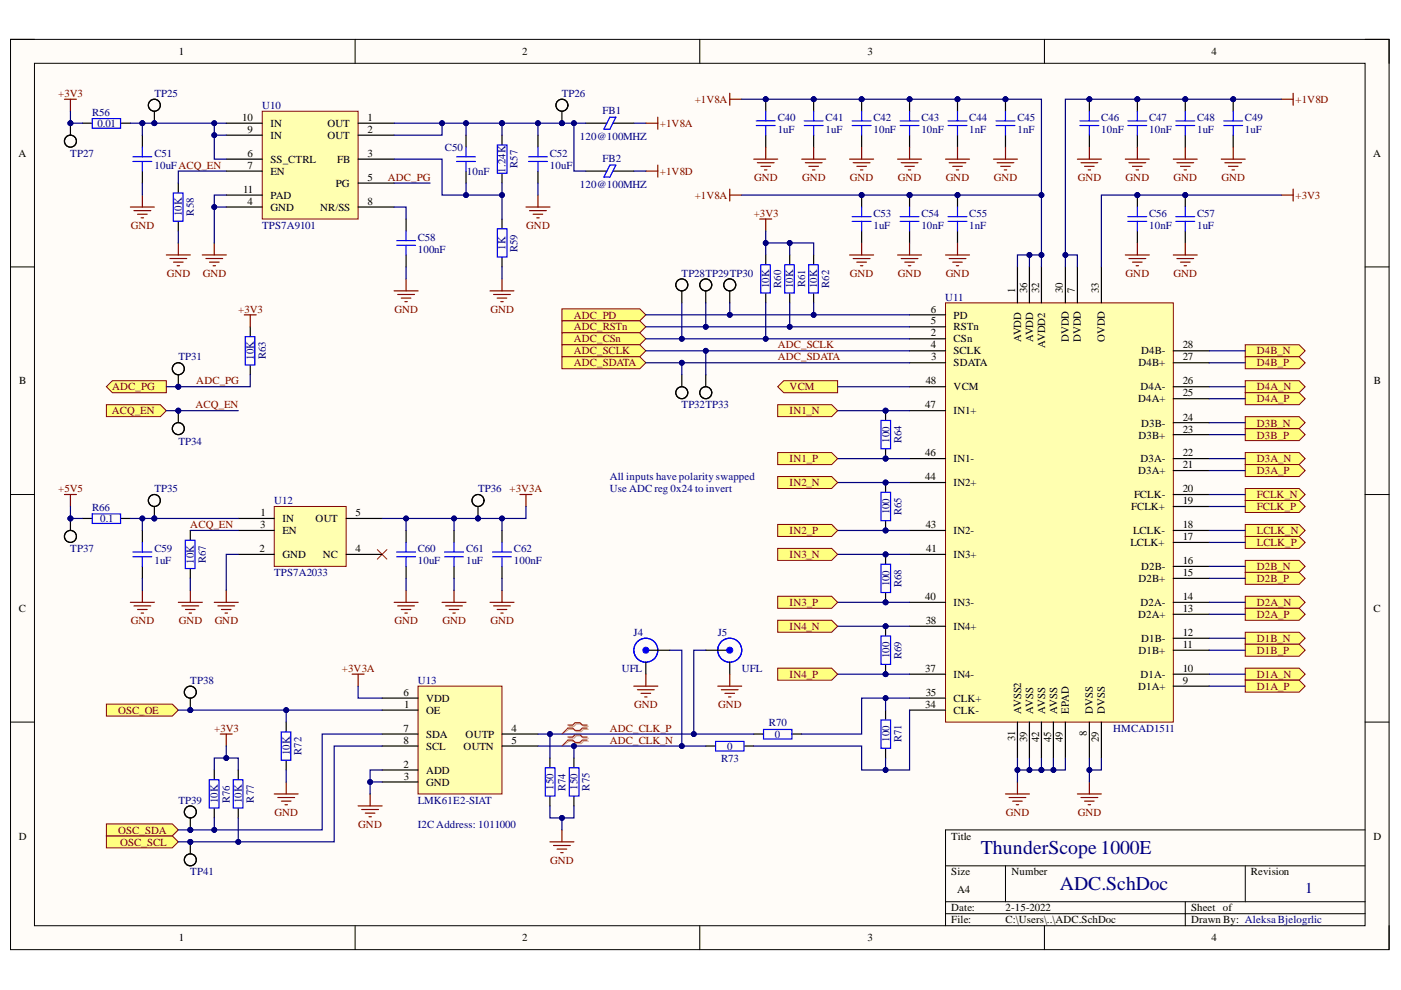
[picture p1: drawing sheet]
<svg xmlns="http://www.w3.org/2000/svg" width="297mm" height="210mm" viewBox="0 0 297 210" stroke-linecap="round" stroke-linejoin="round" font-family="sans-serif">
<defs><g id="words">
<g font-size="4.1" fill="#000080">
<text x="207.9" y="181.1">ThunderScope1000E</text>
<text x="224.7" y="188.8">ADC.SchDoc</text>
</g>
<text font-size="3.2" fill="#000080" x="276.7" y="189.3">1</text>
<g font-size="2.3">
<text x="37.9" y="11.7">1</text>
<text x="110.7" y="11.7">2</text>
<text x="183.9" y="11.7">3</text>
<text x="256.8" y="11.7">4</text>
<text x="51.4" y="25.6">10</text>
<text x="52.5" y="28.1">9</text>
<text x="57.4" y="29.5">IN</text>
<text x="57.4" y="26.9">IN</text>
<text x="69.5" y="26.9">OUT</text>
<text x="69.5" y="29.5">OUT</text>
<text x="77.9" y="25.6">1</text>
<text x="77.9" y="28.1">2</text>
<text x="3.9" y="33.3">A</text>
<text x="52.5" y="33.3">6</text>
<text x="52.5" y="35.8">7</text>
<text x="57.4" y="34.6">SS_CTRL</text>
<text x="71.5" y="34.6">FB</text>
<text x="77.9" y="33.3">3</text>
<text x="291.1" y="33.3">A</text>
<text x="51.5" y="40.9">11</text>
<text x="57.4" y="37.1">EN</text>
<text x="71.2" y="39.6">PG</text>
<text x="77.9" y="38.4">5</text>
<text x="52.5" y="43.4">4</text>
<text x="57.4" y="44.7">GND</text>
<text x="57.4" y="42.2">PAD</text>
<text x="67.8" y="44.7">NR/SS</text>
<text x="77.9" y="43.4">8</text>
<text x="215.2" y="62.2" transform="rotate(-90 215.2 62.2)">1</text>
<text x="217.8" y="62.2" transform="rotate(-90 217.8 62.2)">36</text>
<text x="220.3" y="62.2" transform="rotate(-90 220.3 62.2)">32</text>
<text x="225.4" y="62.2" transform="rotate(-90 225.4 62.2)">30</text>
<text x="227.9" y="62.2" transform="rotate(-90 227.9 62.2)">7</text>
<text x="233" y="62.2" transform="rotate(-90 233 62.2)">33</text>
<text x="197.4" y="66.3">6</text>
<text x="197.4" y="68.8">5</text>
<text x="197.4" y="71.3">2</text>
<text x="202.2" y="67.5">PD</text>
<text x="202.2" y="70.1">RSTn</text>
<text x="197.4" y="73.9">4</text>
<text x="197.5" y="76.4">3</text>
<text x="202.2" y="72.6">CSn</text>
<text x="202.2" y="75.1">SCLK</text>
<text x="202.2" y="77.7">SDATA</text>
<text x="216.5" y="72.5" transform="rotate(-90 216.5 72.5)">AVDD</text>
<text x="219" y="72.5" transform="rotate(-90 219 72.5)">AVDD</text>
<text x="221.6" y="73.7" transform="rotate(-90 221.6 73.7)">AVDD2</text>
<text x="226.6" y="72.5" transform="rotate(-90 226.6 72.5)">DVDD</text>
<text x="229.2" y="72.5" transform="rotate(-90 229.2 72.5)">DVDD</text>
<text x="234.3" y="72.5" transform="rotate(-90 234.3 72.5)">OVDD</text>
<text x="241.4" y="77.7">D4B+</text>
<text x="242" y="75.1">D4B-</text>
<text x="250.8" y="76.4">27</text>
<text x="250.8" y="73.9">28</text>
<text x="4.1" y="81.5">B</text>
<text x="196.3" y="81.5">48</text>
<text x="202.2" y="82.7">VCM</text>
<text x="241.8" y="82.7">D4A-</text>
<text x="250.8" y="81.5">26</text>
<text x="291.3" y="81.5">B</text>
<text x="196.2" y="86.6">47</text>
<text x="202.2" y="87.8">IN1+</text>
<text x="241.3" y="85.3">D4A+</text>
<text x="250.8" y="89.2">24</text>
<text x="250.8" y="84">25</text>
<text x="241.4" y="93">D3B+</text>
<text x="242" y="90.4">D3B-</text>
<text x="250.8" y="91.7">23</text>
<text x="196.2" y="96.8">46</text>
<text x="196.2" y="101.9">44</text>
<text x="202.2" y="98">IN1-</text>
<text x="241.3" y="100.6">D3A+</text>
<text x="241.8" y="98">D3A-</text>
<text x="250.8" y="99.3">21</text>
<text x="250.8" y="96.8">22</text>
<text x="202.2" y="103.1">IN2+</text>
<text x="240.4" y="105.7">FCLK-</text>
<text x="250.8" y="106.9">19</text>
<text x="250.8" y="104.4">20</text>
<text x="55.2" y="112">3</text>
<text x="55.2" y="109.5">1</text>
<text x="59.9" y="110.7">IN</text>
<text x="59.9" y="113.3">EN</text>
<text x="66.9" y="110.7">OUT</text>
<text x="75.4" y="109.5">5</text>
<text x="196.3" y="112">43</text>
<text x="202.2" y="113.3">IN2-</text>
<text x="239.8" y="108.2">FCLK+</text>
<text x="240.3" y="113.3">LCLK-</text>
<text x="250.8" y="112">18</text>
<text x="55" y="117.1">2</text>
<text x="59.9" y="118.3">GND</text>
<text x="68.4" y="118.3">NC</text>
<text x="75.4" y="117.1">4</text>
<text x="196.4" y="117.1">41</text>
<text x="202.2" y="118.3">IN3+</text>
<text x="239.7" y="115.8">LCLK+</text>
<text x="250.8" y="119.6">16</text>
<text x="250.8" y="114.5">17</text>
<text x="241.4" y="123.4">D2B+</text>
<text x="242" y="120.9">D2B-</text>
<text x="250.8" y="122.1">15</text>
<text x="4" y="129.7">C</text>
<text x="196.2" y="127.2">40</text>
<text x="202.2" y="128.5">IN3-</text>
<text x="241.3" y="131">D2A+</text>
<text x="241.8" y="128.5">D2A-</text>
<text x="250.8" y="129.7">13</text>
<text x="250.8" y="127.2">14</text>
<text x="291.2" y="129.7">C</text>
<text x="196.3" y="132.3">38</text>
<text x="202.2" y="133.6">IN4+</text>
<text x="242" y="136.1">D1B-</text>
<text x="250.8" y="137.4">11</text>
<text x="250.8" y="134.8">12</text>
<text x="196.2" y="142.4">37</text>
<text x="202.2" y="143.7">IN4-</text>
<text x="241.4" y="138.6">D1B+</text>
<text x="241.8" y="143.7">D1A-</text>
<text x="250.8" y="142.4">10</text>
<text x="85.5" y="147.5">6</text>
<text x="90.4" y="148.9">VDD</text>
<text x="196.3" y="147.5">35</text>
<text x="202.2" y="148.9">CLK+</text>
<text x="241.3" y="146.2">D1A+</text>
<text x="250.8" y="145">9</text>
<text x="85.5" y="155.2">7</text>
<text x="85.7" y="150.1">1</text>
<text x="90.4" y="151.4">OE</text>
<text x="108.5" y="155.2">4</text>
<text x="196.2" y="150.1">34</text>
<text x="202.2" y="151.4">CLK-</text>
<text x="216.5" y="151.3" transform="rotate(-90 216.5 151.3)">AVSS2</text>
<text x="219" y="151.3" transform="rotate(-90 219 151.3)">AVSS</text>
<text x="221.6" y="151.3" transform="rotate(-90 221.6 151.3)">AVSS</text>
<text x="224.1" y="151.3" transform="rotate(-90 224.1 151.3)">AVSS</text>
<text x="226.6" y="151.3" transform="rotate(-90 226.6 151.3)">EPAD</text>
<text x="231.7" y="151.3" transform="rotate(-90 231.7 151.3)">DVSS</text>
<text x="234.3" y="151.3" transform="rotate(-90 234.3 151.3)">DVSS</text>
<text x="85.5" y="157.7">8</text>
<text x="90.4" y="156.5">SDA</text>
<text x="90.4" y="159">SCL</text>
<text x="98.3" y="159">OUTN</text>
<text x="98.7" y="156.5">OUTP</text>
<text x="108.5" y="157.7">5</text>
<text x="215.2" y="157.1" transform="rotate(-90 215.2 157.1)">31</text>
<text x="217.8" y="157.3" transform="rotate(-90 217.8 157.3)">39</text>
<text x="220.3" y="157.3" transform="rotate(-90 220.3 157.3)">42</text>
<text x="222.8" y="157.3" transform="rotate(-90 222.8 157.3)">45</text>
<text x="225.4" y="157.3" transform="rotate(-90 225.4 157.3)">49</text>
<text x="230.4" y="156.1" transform="rotate(-90 230.4 156.1)">8</text>
<text x="233" y="157.3" transform="rotate(-90 233 157.3)">29</text>
<text x="85.5" y="162.8">2</text>
<text x="85.6" y="165.3">3</text>
<text x="90.4" y="164.1">ADD</text>
<text x="90.4" y="166.6">GND</text>
<text x="4" y="178">D</text>
<text x="201.7" y="178">Title</text>
<text x="291.2" y="178">D</text>
<text x="201.7" y="185.6">Size</text>
<text x="214.5" y="185.6">Number</text>
<text x="265.2" y="185.6">Revision</text>
<text x="203" y="189.4">A4</text>
<text x="201.7" y="193.2">Date:</text>
<text x="201.7" y="195.8">File:</text>
<text x="213.2" y="193.2">2-15-2022</text>
<text x="213.2" y="195.8">C:\Users\..\ADC.SchDoc</text>
<text x="252.5" y="193.2">Sheet of</text>
<text x="252.5" y="195.8">Drawn By: Aleksa Bjelogrlic</text>
<text x="37.9" y="199.6">1</text>
<text x="110.7" y="199.6">2</text>
<text x="183.9" y="199.6">3</text>
<text x="256.8" y="199.6">4</text>
</g>
<g font-size="2.3" fill="#800000">
<text x="12.4" y="20.5">+3V3</text>
<text x="147.3" y="21.8">+1V8A</text>
<text x="274.7" y="21.8">+1V8D</text>
<text x="139.9" y="26.9">+1V8A</text>
<text x="82.2" y="38.4">ADC_PG</text>
<text x="139.9" y="37.1">+1V8D</text>
<text x="159.9" y="38.4">GND</text>
<text x="170" y="38.4">GND</text>
<text x="180.2" y="38.4">GND</text>
<text x="190.3" y="38.4">GND</text>
<text x="200.5" y="38.4">GND</text>
<text x="210.7" y="38.4">GND</text>
<text x="228.5" y="38.4">GND</text>
<text x="238.7" y="38.4">GND</text>
<text x="248.8" y="38.4">GND</text>
<text x="259" y="38.4">GND</text>
<text x="147.3" y="42.2">+1V8A</text>
<text x="159.8" y="46">+3V3</text>
<text x="274.7" y="42.2">+3V3</text>
<text x="27.7" y="48.5">GND</text>
<text x="111.6" y="48.5">GND</text>
<text x="35.4" y="58.7">GND</text>
<text x="43" y="58.7">GND</text>
<text x="180.2" y="58.7">GND</text>
<text x="190.3" y="58.7">GND</text>
<text x="200.5" y="58.7">GND</text>
<text x="238.7" y="58.7">GND</text>
<text x="248.8" y="58.7">GND</text>
<text x="50.5" y="66.3">+3V3</text>
<text x="83.7" y="66.3">GND</text>
<text x="104" y="66.3">GND</text>
<text x="121.7" y="67.5">ADC_PD</text>
<text x="121.7" y="70.1">ADC_RSTn</text>
<text x="121.7" y="72.6">ADC_CSn</text>
<text x="121.7" y="75.1">ADC_SCLK</text>
<text x="121.7" y="77.7">ADC_SDATA</text>
<text x="164.9" y="73.9">ADC_SCLK</text>
<text x="164.9" y="76.4">ADC_SDATA</text>
<text x="266.5" y="75.1">D4B_N</text>
<text x="266.5" y="77.7">D4B_P</text>
<text x="23.8" y="82.7">ADC_PG</text>
<text x="41.6" y="81.5">ADC_PG</text>
<text x="167.4" y="82.7">VCM</text>
<text x="266.5" y="82.7">D4A_N</text>
<text x="23.7" y="87.8">ACQ_EN</text>
<text x="41.5" y="86.6">ACQ_EN</text>
<text x="167.4" y="87.8">IN1_N</text>
<text x="266.5" y="85.3">D4A_P</text>
<text x="266.5" y="90.4">D3B_N</text>
<text x="266.5" y="93">D3B_P</text>
<text x="167.4" y="98">IN1_P</text>
<text x="266.5" y="98">D3A_N</text>
<text x="266.5" y="100.6">D3A_P</text>
<text x="12.4" y="104.4">+5V5</text>
<text x="108" y="104.4">+3V3A</text>
<text x="167.4" y="103.1">IN2_N</text>
<text x="266.5" y="105.7">FCLK_N</text>
<text x="40.4" y="112">ACQ_EN</text>
<text x="167.4" y="113.3">IN2_P</text>
<text x="266.5" y="108.2">FCLK_P</text>
<text x="266.5" y="113.3">LCLK_N</text>
<text x="167.4" y="118.3">IN3_N</text>
<text x="266.5" y="115.8">LCLK_P</text>
<text x="266.5" y="120.9">D2B_N</text>
<text x="266.5" y="123.4">D2B_P</text>
<text x="167.4" y="128.5">IN3_P</text>
<text x="266.5" y="128.5">D2A_N</text>
<text x="266.5" y="131">D2A_P</text>
<text x="27.7" y="132.3">GND</text>
<text x="37.9" y="132.3">GND</text>
<text x="45.5" y="132.3">GND</text>
<text x="83.7" y="132.3">GND</text>
<text x="93.8" y="132.3">GND</text>
<text x="104" y="132.3">GND</text>
<text x="167.4" y="133.6">IN4_N</text>
<text x="266.5" y="136.1">D1B_N</text>
<text x="72.5" y="142.4">+3V3A</text>
<text x="167.4" y="143.7">IN4_P</text>
<text x="266.5" y="138.6">D1B_P</text>
<text x="266.5" y="143.7">D1A_N</text>
<text x="266.5" y="146.2">D1A_P</text>
<text x="25" y="151.4">OSC_OE</text>
<text x="45.4" y="155.2">+3V3</text>
<text x="129.3" y="155.2">ADC_CLK_P</text>
<text x="134.4" y="150.1">GND</text>
<text x="152.3" y="150.1">GND</text>
<text x="129.3" y="157.7">ADC_CLK_N</text>
<text x="58.2" y="172.9">GND</text>
<text x="213.3" y="172.9">GND</text>
<text x="228.5" y="172.9">GND</text>
<text x="25" y="176.7">OSC_SDA</text>
<text x="25.5" y="179.3">OSC_SCL</text>
<text x="76" y="175.5">GND</text>
<text x="116.7" y="183.1">GND</text>
</g>
<g font-size="2.3" fill="#000080">
<text x="32.7" y="20.5">TP25</text>
<text x="55.6" y="23.1">U10</text>
<text x="119.1" y="20.5">TP26</text>
<text x="19.5" y="24.7">R56</text>
<text x="20.6" y="26.9">0.01</text>
<text x="122.9" y="29.7">120@100MHZ</text>
<text x="127.7" y="24.1">FB1</text>
<text x="164.9" y="25.6">C40</text>
<text x="164.9" y="28.1">1uF</text>
<text x="175" y="25.6">C41</text>
<text x="175" y="28.1">1uF</text>
<text x="185.2" y="25.6">C42</text>
<text x="185.2" y="28.1">10nF</text>
<text x="195.3" y="25.6">C43</text>
<text x="195.3" y="28.1">10nF</text>
<text x="205.5" y="25.6">C44</text>
<text x="205.5" y="28.1">1nF</text>
<text x="215.7" y="25.6">C45</text>
<text x="215.7" y="28.1">1nF</text>
<text x="233.5" y="25.6">C46</text>
<text x="233.5" y="28.1">10nF</text>
<text x="243.6" y="25.6">C47</text>
<text x="243.6" y="28.1">10nF</text>
<text x="253.8" y="25.6">C48</text>
<text x="253.8" y="28.1">1uF</text>
<text x="264" y="25.6">C49</text>
<text x="264" y="28.1">1uF</text>
<text x="14.9" y="33.3">TP27</text>
<text x="32.7" y="33.3">C51</text>
<text x="32.7" y="35.8">10uFACQ_EN</text>
<text x="94.3" y="32">C50</text>
<text x="109.7" y="35.6" transform="rotate(-90 109.7 35.6)">R57</text>
<text x="116.6" y="33.3">C52</text>
<text x="116.6" y="35.8">10uF</text>
<text x="127.7" y="34.3">FB2</text>
<text x="99" y="37.1">10nF</text>
<text x="107.2" y="36.6" transform="rotate(-90 107.2 36.6)">1.24K</text>
<text x="122.9" y="39.9">120@100MHZ</text>
<text x="38.6" y="45.9" transform="rotate(-90 38.6 45.9)">10K</text>
<text x="41.1" y="45.7" transform="rotate(-90 41.1 45.7)">R58</text>
<text x="185.2" y="46">C53</text>
<text x="195.3" y="46">C54</text>
<text x="205.5" y="46">C55</text>
<text x="243.6" y="46">C56</text>
<text x="253.8" y="46">C57</text>
<text x="55.6" y="48.5">TPS7A9101</text>
<text x="88.6" y="51">C58</text>
<text x="88.6" y="53.6">100nF</text>
<text x="107.2" y="52.9" transform="rotate(-90 107.2 52.9)">1K</text>
<text x="109.7" y="53.4" transform="rotate(-90 109.7 53.4)">R59</text>
<text x="185.2" y="48.5">1uF</text>
<text x="195.3" y="48.5">10nF</text>
<text x="205.5" y="48.5">1nF</text>
<text x="243.6" y="48.5">10nF</text>
<text x="253.8" y="48.5">1uF</text>
<text x="144.5" y="58.7">TP28TP29TP30</text>
<text x="163.1" y="61.1" transform="rotate(-90 163.1 61.1)">10K</text>
<text x="165.6" y="61" transform="rotate(-90 165.6 61)">R60</text>
<text x="168.2" y="61.1" transform="rotate(-90 168.2 61.1)">10K</text>
<text x="170.7" y="60.9" transform="rotate(-90 170.7 60.9)">R61</text>
<text x="173.3" y="61.1" transform="rotate(-90 173.3 61.1)">10K</text>
<text x="175.8" y="61" transform="rotate(-90 175.8 61)">R62</text>
<text x="200.4" y="63.7">U11</text>
<text x="37.8" y="76.4">TP31</text>
<text x="53.8" y="76.3" transform="rotate(-90 53.8 76.3)">10K</text>
<text x="56.3" y="76.2" transform="rotate(-90 56.3 76.2)">R63</text>
<text x="144.5" y="86.6">TP32TP33</text>
<text x="37.8" y="94.2">TP34</text>
<text x="188.6" y="93.8" transform="rotate(-90 188.6 93.8)">100</text>
<text x="191.1" y="94" transform="rotate(-90 191.1 94)">R64</text>
<text x="129.3" y="101.9">All inputs have polarity swapped</text>
<text x="32.7" y="104.4">TP35</text>
<text x="58.1" y="106.9">U12</text>
<text x="101.4" y="104.4">TP36</text>
<text x="129.3" y="104.4">Use ADC reg 0x24 to invert</text>
<text x="19.5" y="108.4">R66</text>
<text x="21.2" y="110.7">0.1</text>
<text x="188.6" y="109" transform="rotate(-90 188.6 109)">100</text>
<text x="191.1" y="109.2" transform="rotate(-90 191.1 109.2)">R65</text>
<text x="14.9" y="117.1">TP37</text>
<text x="32.7" y="117.1">C59</text>
<text x="32.7" y="119.6">1uF</text>
<text x="41.1" y="119.5" transform="rotate(-90 41.1 119.5)">10K</text>
<text x="43.7" y="119.4" transform="rotate(-90 43.7 119.4)">R67</text>
<text x="88.6" y="117.1">C60</text>
<text x="88.6" y="119.6">10uF</text>
<text x="98.8" y="117.1">C61</text>
<text x="98.8" y="119.6">1uF</text>
<text x="109" y="117.1">C62</text>
<text x="109" y="119.6">100nF</text>
<text x="58.1" y="122.1">TPS7A2033</text>
<text x="188.6" y="124.3" transform="rotate(-90 188.6 124.3)">100</text>
<text x="191.1" y="124.5" transform="rotate(-90 191.1 124.5)">R68</text>
<text x="134.3" y="134.8">J4</text>
<text x="152.2" y="134.8">J5</text>
<text x="131.8" y="142.4">UFL</text>
<text x="157.3" y="142.4">UFL</text>
<text x="188.6" y="139.6" transform="rotate(-90 188.6 139.6)">100</text>
<text x="191.1" y="139.7" transform="rotate(-90 191.1 139.7)">R69</text>
<text x="40.4" y="145">TP38</text>
<text x="88.6" y="145">U13</text>
<text x="163" y="153.9">R70</text>
<text x="236" y="155.2">HMCAD1511</text>
<text x="61.4" y="160.2" transform="rotate(-90 61.4 160.2)">10K</text>
<text x="64" y="160" transform="rotate(-90 64 160)">R72</text>
<text x="152.9" y="161.5">R73</text>
<text x="154.1" y="159">0</text>
<text x="164.3" y="156.5">0</text>
<text x="188.6" y="157.3" transform="rotate(-90 188.6 157.3)">100</text>
<text x="191.1" y="157.4" transform="rotate(-90 191.1 157.4)">R71</text>
<text x="117.3" y="167.4" transform="rotate(-90 117.3 167.4)">150</text>
<text x="119.9" y="167.7" transform="rotate(-90 119.9 167.7)">R74</text>
<text x="122.4" y="167.4" transform="rotate(-90 122.4 167.4)">150</text>
<text x="125" y="167.6" transform="rotate(-90 125 167.6)">R75</text>
<text x="37.8" y="170.4">TP39</text>
<text x="46.2" y="170.3" transform="rotate(-90 46.2 170.3)">10K</text>
<text x="48.7" y="170.2" transform="rotate(-90 48.7 170.2)">R76</text>
<text x="51.3" y="170.3" transform="rotate(-90 51.3 170.3)">10K</text>
<text x="53.8" y="170.2" transform="rotate(-90 53.8 170.2)">R77</text>
<text x="88.6" y="170.4">LMK61E2-SIAT</text>
<text x="88.6" y="175.5">I2C Address: 1011000</text>
<text x="40.4" y="185.6">TP41</text>
</g>
</g></defs>
<path d="M2.2 8.3h292.3v193h-292.3z" fill-rule="evenodd" fill="#fffcf8"/>
<path d="M2.2 8.3h292.3v193h-292.3z" fill="none" stroke="#000" stroke-width=".21"/>
<path d="M7.3 13.4h282.1v182.9h-282.1z" fill-rule="evenodd" fill="#fffcf8"/>
<g fill="none" stroke="#000" stroke-width=".21">
<path d="M2.2 8.3h5.1M7.3 13.4h282.1v182.9h-282.1zM75.3 8.3v5.1M148.4 8.3v5.1M221.4 8.3v5.1M289.4 8.3h5.1v5.1M2.2 56.6h5.1M289.4 56.6h5.1M2.2 104.8h5.1M289.4 104.9h5.1M2.2 153.1h5.1M289.4 153.1h5.1"/>
<path d="M289.4 176h-88.9v20.3M75.3 196.3v5M148.4 196.3v5M200.5 183.6h88.9M200.5 191.2h88.9M200.5 193.7h88.9M213.2 183.6v7.6M221.4 196.3v5M251.3 191.2v5.1M264 183.6v7.6M294.5 196.3v5"/>
</g>
<path d="M55.6 23.6h20.3v22.8h-20.3z" fill-rule="evenodd" fill="#ffffb0"/>
<path d="M55.6 23.6h20.3v22.8h-20.3z" fill="none" stroke="#800000" stroke-width=".21"/>
<g fill="none" stroke="#000" stroke-width=".25">
<path d="M30.2 28.7v2.5M30.2 36.3v2.5M48 26.1h7.6M48 28.7h7.6M48 33.7h7.6M48 36.3h7.6M75.9 26.1h7.7M75.9 28.7h7.7M75.9 33.7h7.7M75.9 38.8h7.7M98.8 28.7v2.5M98.8 36.3v2.5"/>
<path d="M106.4 28.7v2M106.4 36.8v2M114.1 28.7v2.5M114.1 36.3v2.5M48 43.9h7.6M48 41.4h7.6M75.9 43.9h7.7M86.1 46.4v2.6M86.1 54.1v2.5M106.4 46.4v2M106.4 54.6v2"/>
</g>
<g fill="none" stroke="#800000" stroke-width=".25">
<path d="M13.7 21h2.5M14.9 21v2.6M27.6 43.9h5.1M28.4 44.7h3.6M29.2 45.4h2M29.9 46.2h.5M30.2 41.4v2.5M42.9 54.1h5.1M43.7 54.8h3.5M44.4 55.6h2.1M45.2 56.3h.5M45.4 51.5v2.6"/>
<path d="M86.1 59.1v2.6M106.4 59.1v2.6M111.5 43.9h5.1M112.3 44.7h3.5M113 45.4h2.1M113.8 46.2h.5M114.1 41.4v2.5M83.6 61.7h5M84.3 62.4h3.6M85.1 63.2h2M85.8 64h.5M103.9 61.7h5.1"/>
<path d="M104.6 62.4h3.6M105.4 63.2h2M106.2 64h.5"/>
</g>
<g fill="none" stroke="#00f" stroke-width=".25">
<path d="M28.2 34.2h4M28.2 33.2h4M30.2 31.2v2M30.2 34.2v2.1M96.8 34.2h4M96.8 33.2h4M98.8 31.2v2M98.8 34.2v2.1M105.5 30.7h2v6h-2zM112.1 34.2h4M112.1 33.2h4M114.1 31.2v2"/>
<path d="M114.1 34.2v2.1M84.1 52h4M84.1 51h4M86.1 49v2M86.1 52v2.1M105.5 48.5h2v6h-2z"/>
</g>
<circle cx="241.1" cy="41.4" r=".51" fill="#000080"/>
<circle cx="241.1" cy="41.4" r=".51" fill="none" stroke="#000080" stroke-width=".21"/>
<path d="M241.1 41.4v2.5M241.1 49v2.5" fill="none" stroke="#000" stroke-width=".25"/>
<circle cx="241.1" cy="41.4" r=".51" fill="#000080"/>
<circle cx="241.1" cy="41.4" r=".51" fill="none" stroke="#000080" stroke-width=".21"/>
<path d="M239.1 46.9h4M239.1 45.9h4M241.1 43.9v2M241.1 46.9v2.1" fill="none" stroke="#00f" stroke-width=".25"/>
<circle cx="251.3" cy="41.4" r=".51" fill="#000080"/>
<circle cx="251.3" cy="41.4" r=".51" fill="none" stroke="#000080" stroke-width=".21"/>
<path d="M251.3 41.4v2.5M251.3 49v2.5" fill="none" stroke="#000" stroke-width=".25"/>
<circle cx="251.3" cy="41.4" r=".51" fill="#000080"/>
<circle cx="251.3" cy="41.4" r=".51" fill="none" stroke="#000080" stroke-width=".21"/>
<path d="M249.3 46.9h4M249.3 45.9h4M251.3 43.9v2M251.3 46.9v2.1" fill="none" stroke="#00f" stroke-width=".25"/>
<path d="M238.6 54.1h5.1M239.4 54.8h3.5M240.1 55.6h2.1M240.9 56.3h.5M241.1 51.5v2.6M248.8 54.1h5M249.5 54.8h3.6M250.3 55.6h2M251 56.3h.6M251.3 51.5v2.6M271.6 41.4h2.6M274.2 40.1v2.5" fill="none" stroke="#800000" stroke-width=".25"/>
<circle cx="231" cy="21" r=".51" fill="#000080"/>
<circle cx="231" cy="21" r=".51" fill="none" stroke="#000080" stroke-width=".21"/>
<path d="M231 21v2.6M231 28.7v2.5" fill="none" stroke="#000" stroke-width=".25"/>
<circle cx="231" cy="21" r=".51" fill="#000080"/>
<circle cx="231" cy="21" r=".51" fill="none" stroke="#000080" stroke-width=".21"/>
<path d="M229 26.6h4M229 25.6h4M231 23.6v2M231 26.6v2.1" fill="none" stroke="#00f" stroke-width=".25"/>
<circle cx="261.5" cy="21" r=".51" fill="#000080"/>
<circle cx="261.5" cy="21" r=".51" fill="none" stroke="#000080" stroke-width=".21"/>
<path d="M261.5 21v2.6M261.5 28.7v2.5" fill="none" stroke="#000" stroke-width=".25"/>
<circle cx="261.5" cy="21" r=".51" fill="#000080"/>
<circle cx="261.5" cy="21" r=".51" fill="none" stroke="#000080" stroke-width=".21"/>
<path d="M259.5 26.6h4M259.5 25.6h4M261.5 23.6v2M261.5 26.6v2.1" fill="none" stroke="#00f" stroke-width=".25"/>
<path d="M228.4 33.7h5.1M229.2 34.5h3.5M230 35.3h2M230.7 36h.5M231 31.2v2.5M258.9 33.7h5.1M259.7 34.5h3.5M260.5 35.3h2M261.2 36h.5M261.5 31.2v2.5" fill="none" stroke="#800000" stroke-width=".25"/>
<circle cx="241.1" cy="21" r=".51" fill="#000080"/>
<circle cx="241.1" cy="21" r=".51" fill="none" stroke="#000080" stroke-width=".21"/>
<path d="M241.1 21v2.6M241.1 28.7v2.5" fill="none" stroke="#000" stroke-width=".25"/>
<circle cx="241.1" cy="21" r=".51" fill="#000080"/>
<circle cx="241.1" cy="21" r=".51" fill="none" stroke="#000080" stroke-width=".21"/>
<path d="M239.1 26.6h4M239.1 25.6h4M241.1 23.6v2M241.1 26.6v2.1" fill="none" stroke="#00f" stroke-width=".25"/>
<circle cx="251.3" cy="21" r=".51" fill="#000080"/>
<circle cx="251.3" cy="21" r=".51" fill="none" stroke="#000080" stroke-width=".21"/>
<path d="M251.3 21v2.6M251.3 28.7v2.5" fill="none" stroke="#000" stroke-width=".25"/>
<circle cx="251.3" cy="21" r=".51" fill="#000080"/>
<circle cx="251.3" cy="21" r=".51" fill="none" stroke="#000080" stroke-width=".21"/>
<path d="M249.3 26.6h4M249.3 25.6h4M251.3 23.6v2M251.3 26.6v2.1" fill="none" stroke="#00f" stroke-width=".25"/>
<path d="M274.2 19.8v2.5M238.6 33.7h5.1M239.4 34.5h3.5M240.1 35.3h2.1M240.9 36h.5M241.1 31.2v2.5M248.8 33.7h5M249.5 34.5h3.6M250.3 35.3h2M251 36h.6M251.3 31.2v2.5M271.6 21h2.6" fill="none" stroke="#800000" stroke-width=".25"/>
<circle cx="192.8" cy="21" r=".51" fill="#000080"/>
<circle cx="192.8" cy="21" r=".51" fill="none" stroke="#000080" stroke-width=".21"/>
<path d="M192.8 21v2.6M192.8 28.7v2.5" fill="none" stroke="#000" stroke-width=".25"/>
<circle cx="192.8" cy="21" r=".51" fill="#000080"/>
<circle cx="192.8" cy="21" r=".51" fill="none" stroke="#000080" stroke-width=".21"/>
<path d="M190.8 26.6h4M190.8 25.6h4M192.8 23.6v2M192.8 26.6v2.1" fill="none" stroke="#00f" stroke-width=".25"/>
<circle cx="162.3" cy="21" r=".51" fill="#000080"/>
<circle cx="162.3" cy="21" r=".51" fill="none" stroke="#000080" stroke-width=".21"/>
<path d="M162.3 21v2.6M162.3 28.7v2.5" fill="none" stroke="#000" stroke-width=".25"/>
<circle cx="162.3" cy="21" r=".51" fill="#000080"/>
<circle cx="162.3" cy="21" r=".51" fill="none" stroke="#000080" stroke-width=".21"/>
<path d="M160.3 26.6h4M160.3 25.6h4M162.3 23.6v2M162.3 26.6v2.1" fill="none" stroke="#00f" stroke-width=".25"/>
<path d="M159.8 33.7h5.1M160.6 34.5h3.5M161.3 35.3h2.1M162.1 36h.5M162.3 31.2v2.5M190.3 33.7h5.1M191.1 34.5h3.5M191.8 35.3h2.1M192.6 36h.5M192.8 31.2v2.5" fill="none" stroke="#800000" stroke-width=".25"/>
<circle cx="182.7" cy="21" r=".51" fill="#000080"/>
<circle cx="182.7" cy="21" r=".51" fill="none" stroke="#000080" stroke-width=".21"/>
<path d="M182.7 21v2.6M182.7 28.7v2.5" fill="none" stroke="#000" stroke-width=".25"/>
<circle cx="182.7" cy="21" r=".51" fill="#000080"/>
<circle cx="182.7" cy="21" r=".51" fill="none" stroke="#000080" stroke-width=".21"/>
<path d="M180.7 26.6h4M180.7 25.6h4M182.7 23.6v2M182.7 26.6v2.1" fill="none" stroke="#00f" stroke-width=".25"/>
<circle cx="172.5" cy="21" r=".51" fill="#000080"/>
<circle cx="172.5" cy="21" r=".51" fill="none" stroke="#000080" stroke-width=".21"/>
<path d="M172.5 21v2.6M172.5 28.7v2.5" fill="none" stroke="#000" stroke-width=".25"/>
<circle cx="172.5" cy="21" r=".51" fill="#000080"/>
<circle cx="172.5" cy="21" r=".51" fill="none" stroke="#000080" stroke-width=".21"/>
<path d="M170.5 26.6h4M170.5 25.6h4M172.5 23.6v2M172.5 26.6v2.1" fill="none" stroke="#00f" stroke-width=".25"/>
<path d="M170 33.7h5.1M170.7 34.5h3.6M171.5 35.3h2M172.3 36h.5M172.5 31.2v2.5M180.1 33.7h5.1M180.9 34.5h3.6M181.7 35.3h2M182.4 36h.5M182.7 31.2v2.5" fill="none" stroke="#800000" stroke-width=".25"/>
<circle cx="203" cy="21" r=".51" fill="#000080"/>
<circle cx="203" cy="21" r=".51" fill="none" stroke="#000080" stroke-width=".21"/>
<path d="M203 21v2.6M203 28.7v2.5" fill="none" stroke="#000" stroke-width=".25"/>
<circle cx="203" cy="21" r=".51" fill="#000080"/>
<circle cx="203" cy="21" r=".51" fill="none" stroke="#000080" stroke-width=".21"/>
<path d="M201 26.6h4M201 25.6h4M203 23.6v2M203 26.6v2.1" fill="none" stroke="#00f" stroke-width=".25"/>
<path d="M200.5 33.7h5.1M201.2 34.5h3.6M202 35.3h2M202.8 36h.5M203 31.2v2.5" fill="none" stroke="#800000" stroke-width=".25"/>
<circle cx="213.2" cy="21" r=".51" fill="#000080"/>
<circle cx="213.2" cy="21" r=".51" fill="none" stroke="#000080" stroke-width=".21"/>
<path d="M213.2 21v2.6M213.2 28.7v2.5" fill="none" stroke="#000" stroke-width=".25"/>
<circle cx="213.2" cy="21" r=".51" fill="#000080"/>
<circle cx="213.2" cy="21" r=".51" fill="none" stroke="#000080" stroke-width=".21"/>
<path d="M211.2 26.6h4M211.2 25.6h4M213.2 23.6v2M213.2 26.6v2.1" fill="none" stroke="#00f" stroke-width=".25"/>
<path d="M210.6 33.7h5.1M211.4 34.5h3.6M212.2 35.3h2M212.9 36h.5M213.2 31.2v2.5" fill="none" stroke="#800000" stroke-width=".25"/>
<circle cx="182.7" cy="41.4" r=".51" fill="#000080"/>
<circle cx="182.7" cy="41.4" r=".51" fill="none" stroke="#000080" stroke-width=".21"/>
<path d="M182.7 41.4v2.5M182.7 49v2.5" fill="none" stroke="#000" stroke-width=".25"/>
<circle cx="182.7" cy="41.4" r=".51" fill="#000080"/>
<circle cx="182.7" cy="41.4" r=".51" fill="none" stroke="#000080" stroke-width=".21"/>
<path d="M180.7 46.9h4M180.7 45.9h4M182.7 43.9v2M182.7 46.9v2.1" fill="none" stroke="#00f" stroke-width=".25"/>
<path d="M180.1 54.1h5.1M180.9 54.8h3.6M181.7 55.6h2M182.4 56.3h.5M182.7 51.5v2.6" fill="none" stroke="#800000" stroke-width=".25"/>
<circle cx="192.8" cy="41.4" r=".51" fill="#000080"/>
<circle cx="192.8" cy="41.4" r=".51" fill="none" stroke="#000080" stroke-width=".21"/>
<path d="M192.8 41.4v2.5M192.8 49v2.5" fill="none" stroke="#000" stroke-width=".25"/>
<circle cx="192.8" cy="41.4" r=".51" fill="#000080"/>
<circle cx="192.8" cy="41.4" r=".51" fill="none" stroke="#000080" stroke-width=".21"/>
<path d="M190.8 46.9h4M190.8 45.9h4M192.8 43.9v2M192.8 46.9v2.1" fill="none" stroke="#00f" stroke-width=".25"/>
<path d="M190.3 54.1h5.1M191.1 54.8h3.5M191.8 55.6h2.1M192.6 56.3h.5M192.8 51.5v2.6" fill="none" stroke="#800000" stroke-width=".25"/>
<circle cx="203" cy="41.4" r=".51" fill="#000080"/>
<circle cx="203" cy="41.4" r=".51" fill="none" stroke="#000080" stroke-width=".21"/>
<path d="M203 41.4v2.5M203 49v2.5" fill="none" stroke="#000" stroke-width=".25"/>
<circle cx="203" cy="41.4" r=".51" fill="#000080"/>
<circle cx="203" cy="41.4" r=".51" fill="none" stroke="#000080" stroke-width=".21"/>
<path d="M161.3 56.1h2v6h-2zM166.4 56.1h2v6h-2zM171.5 56.1h2v6h-2zM201 46.9h4M201 45.9h4M203 43.9v2M203 46.9v2.1" fill="none" stroke="#00f" stroke-width=".25"/>
<path d="M200.5 54.1h5.1M201.2 54.8h3.6M202 55.6h2M202.8 56.3h.5M203 51.5v2.6" fill="none" stroke="#800000" stroke-width=".25"/>
<path d="M162.3 54.1v2M167.4 54.1v2M172.5 54.1v2M162.3 62.2v2M167.4 62.2v2M172.5 62.2v2" fill="none" stroke="#000" stroke-width=".25"/>
<path d="M200.5 64.2h48.3v88.9h-48.3z" fill-rule="evenodd" fill="#ffffb0"/>
<path d="M200.5 64.2h48.3v88.9h-48.3z" fill="none" stroke="#800000" stroke-width=".21"/>
<g fill="none" stroke="#000" stroke-width=".25">
<path d="M215.7 56.6v7.6M218.3 56.6v7.6M220.8 56.6v7.6M225.9 56.6v7.6M228.4 56.6v7.6M233.5 56.6v7.6M192.8 66.8h7.7M192.8 69.3h7.7M192.8 71.8h7.7M192.8 74.4h7.7M192.8 76.9h7.7M248.8 74.4h7.6"/>
<path d="M248.8 76.9h7.6M192.8 82h7.7M192.8 87.1h7.7M192.8 97.2h7.7M248.8 82h7.6M248.8 97.2h7.6M248.8 99.8h7.6M248.8 92.2h7.6M248.8 89.6h7.6M248.8 84.5h7.6M192.8 102.3h7.7M192.8 112.5h7.7"/>
<path d="M192.8 117.5h7.7M248.8 112.5h7.6M248.8 115h7.6M248.8 107.4h7.6M248.8 104.9h7.6M192.8 127.7h7.7M192.8 132.8h7.7M248.8 127.7h7.6M248.8 137.9h7.6M248.8 135.3h7.6M248.8 130.2h7.6M248.8 122.6h7.6"/>
<path d="M248.8 120.1h7.6M192.8 142.9h7.7M192.8 148h7.7M192.8 150.6h7.7M215.7 153.1v7.6M218.3 153.1v7.6M220.8 153.1v7.6M223.3 153.1v7.6M225.9 153.1v7.6M231 153.1v7.6M233.5 153.1v7.6M248.8 142.9h7.6"/>
<path d="M248.8 145.5h7.6"/>
</g>
<g fill="none" stroke="#800000" stroke-width=".25">
<path d="M154.7 19.8v2.5M154.7 21h2.6M154.7 40.1v2.5M154.7 41.4h2.6M161.1 46.4h2.5M162.3 46.4v2.6M213.2 168.3h5.1M213.9 169.1h3.6M214.7 169.9h2M215.5 170.6h.5M215.7 165.8v2.5M228.4 168.3h5.1"/>
<path d="M229.2 169.1h3.5M230 169.9h2M230.7 170.6h.5M231 165.8v2.5"/>
</g>
<circle cx="187.8" cy="87.1" r=".51" fill="#000080"/>
<circle cx="187.8" cy="87.1" r=".51" fill="none" stroke="#000080" stroke-width=".21"/>
<circle cx="187.8" cy="97.2" r=".51" fill="#000080"/>
<circle cx="187.8" cy="97.2" r=".51" fill="none" stroke="#000080" stroke-width=".21"/>
<path d="M187.8 87.1v2" fill="none" stroke="#000" stroke-width=".25"/>
<circle cx="187.8" cy="87.1" r=".51" fill="#000080"/>
<circle cx="187.8" cy="87.1" r=".51" fill="none" stroke="#000080" stroke-width=".21"/>
<path d="M187.8 95.2v2" fill="none" stroke="#000" stroke-width=".25"/>
<circle cx="187.8" cy="97.2" r=".51" fill="#000080"/>
<circle cx="187.8" cy="97.2" r=".51" fill="none" stroke="#000080" stroke-width=".21"/>
<path d="M186.8 89.2h2v6h-2z" fill="none" stroke="#00f" stroke-width=".25"/>
<circle cx="187.8" cy="102.3" r=".51" fill="#000080"/>
<circle cx="187.8" cy="102.3" r=".51" fill="none" stroke="#000080" stroke-width=".21"/>
<circle cx="187.8" cy="112.5" r=".51" fill="#000080"/>
<circle cx="187.8" cy="112.5" r=".51" fill="none" stroke="#000080" stroke-width=".21"/>
<path d="M187.8 102.3v2" fill="none" stroke="#000" stroke-width=".25"/>
<circle cx="187.8" cy="102.3" r=".51" fill="#000080"/>
<circle cx="187.8" cy="102.3" r=".51" fill="none" stroke="#000080" stroke-width=".21"/>
<path d="M187.8 110.5v2" fill="none" stroke="#000" stroke-width=".25"/>
<circle cx="187.8" cy="112.5" r=".51" fill="#000080"/>
<circle cx="187.8" cy="112.5" r=".51" fill="none" stroke="#000080" stroke-width=".21"/>
<path d="M186.8 104.4h2v6h-2z" fill="none" stroke="#00f" stroke-width=".25"/>
<circle cx="187.8" cy="117.5" r=".51" fill="#000080"/>
<circle cx="187.8" cy="117.5" r=".51" fill="none" stroke="#000080" stroke-width=".21"/>
<circle cx="187.8" cy="127.7" r=".51" fill="#000080"/>
<circle cx="187.8" cy="127.7" r=".51" fill="none" stroke="#000080" stroke-width=".21"/>
<path d="M187.8 117.5v2.1" fill="none" stroke="#000" stroke-width=".25"/>
<circle cx="187.8" cy="117.5" r=".51" fill="#000080"/>
<circle cx="187.8" cy="117.5" r=".51" fill="none" stroke="#000080" stroke-width=".21"/>
<path d="M187.8 125.7v2" fill="none" stroke="#000" stroke-width=".25"/>
<circle cx="187.8" cy="127.7" r=".51" fill="#000080"/>
<circle cx="187.8" cy="127.7" r=".51" fill="none" stroke="#000080" stroke-width=".21"/>
<path d="M186.8 119.6h2v6h-2z" fill="none" stroke="#00f" stroke-width=".25"/>
<circle cx="187.8" cy="132.8" r=".51" fill="#000080"/>
<circle cx="187.8" cy="132.8" r=".51" fill="none" stroke="#000080" stroke-width=".21"/>
<circle cx="187.8" cy="142.9" r=".51" fill="#000080"/>
<circle cx="187.8" cy="142.9" r=".51" fill="none" stroke="#000080" stroke-width=".21"/>
<path d="M187.8 132.8v2" fill="none" stroke="#000" stroke-width=".25"/>
<circle cx="187.8" cy="132.8" r=".51" fill="#000080"/>
<circle cx="187.8" cy="132.8" r=".51" fill="none" stroke="#000080" stroke-width=".21"/>
<path d="M187.8 140.9v2" fill="none" stroke="#000" stroke-width=".25"/>
<circle cx="187.8" cy="142.9" r=".51" fill="#000080"/>
<circle cx="187.8" cy="142.9" r=".51" fill="none" stroke="#000080" stroke-width=".21"/>
<path d="M186.8 134.9h2v6h-2z" fill="none" stroke="#00f" stroke-width=".25"/>
<path d="M264 73.1h11.4l1.3 1.3-1.3 1.2h-11.4z" fill-rule="evenodd" fill="#ffff80"/>
<path d="M264 73.1h11.4l1.3 1.3-1.3 1.2h-11.4z" fill="none" stroke="#800000" stroke-width=".21"/>
<path d="M264 75.6h11.4l1.3 1.3-1.3 1.3h-11.4z" fill-rule="evenodd" fill="#ffff80"/>
<path d="M264 75.6h11.4l1.3 1.3-1.3 1.3h-11.4z" fill="none" stroke="#800000" stroke-width=".21"/>
<path d="M264 80.7h11.4l1.3 1.3-1.3 1.3h-11.4z" fill-rule="evenodd" fill="#ffff80"/>
<path d="M264 80.7h11.4l1.3 1.3-1.3 1.3h-11.4z" fill="none" stroke="#800000" stroke-width=".21"/>
<path d="M264 83.3h11.4l1.3 1.2-1.3 1.3h-11.4z" fill-rule="evenodd" fill="#ffff80"/>
<path d="M264 83.3h11.4l1.3 1.2-1.3 1.3h-11.4z" fill="none" stroke="#800000" stroke-width=".21"/>
<path d="M264 88.3h11.4l1.3 1.3-1.3 1.3h-11.4z" fill-rule="evenodd" fill="#ffff80"/>
<path d="M264 88.3h11.4l1.3 1.3-1.3 1.3h-11.4z" fill="none" stroke="#800000" stroke-width=".21"/>
<path d="M264 90.9h11.4l1.3 1.3-1.3 1.2h-11.4z" fill-rule="evenodd" fill="#ffff80"/>
<path d="M264 90.9h11.4l1.3 1.3-1.3 1.2h-11.4z" fill="none" stroke="#800000" stroke-width=".21"/>
<path d="M264 96h11.4l1.3 1.2-1.3 1.3h-11.4z" fill-rule="evenodd" fill="#ffff80"/>
<path d="M264 96h11.4l1.3 1.2-1.3 1.3h-11.4z" fill="none" stroke="#800000" stroke-width=".21"/>
<path d="M264 98.5h11.4l1.3 1.3-1.3 1.2h-11.4z" fill-rule="evenodd" fill="#ffff80"/>
<path d="M264 98.5h11.4l1.3 1.3-1.3 1.2h-11.4z" fill="none" stroke="#800000" stroke-width=".21"/>
<path d="M264 103.6h11.4l1.3 1.3-1.3 1.2h-11.4z" fill-rule="evenodd" fill="#ffff80"/>
<path d="M264 103.6h11.4l1.3 1.3-1.3 1.2h-11.4z" fill="none" stroke="#800000" stroke-width=".21"/>
<path d="M264 106.1h11.4l1.3 1.3-1.3 1.3h-11.4z" fill-rule="evenodd" fill="#ffff80"/>
<path d="M264 106.1h11.4l1.3 1.3-1.3 1.3h-11.4z" fill="none" stroke="#800000" stroke-width=".21"/>
<path d="M264 111.2h11.4l1.3 1.3-1.3 1.2h-11.4z" fill-rule="evenodd" fill="#ffff80"/>
<path d="M264 111.2h11.4l1.3 1.3-1.3 1.2h-11.4z" fill="none" stroke="#800000" stroke-width=".21"/>
<path d="M264 113.7h11.4l1.3 1.3-1.3 1.3h-11.4z" fill-rule="evenodd" fill="#ffff80"/>
<path d="M264 113.7h11.4l1.3 1.3-1.3 1.3h-11.4z" fill="none" stroke="#800000" stroke-width=".21"/>
<path d="M264 118.8h11.4l1.3 1.3-1.3 1.3h-11.4z" fill-rule="evenodd" fill="#ffff80"/>
<path d="M264 118.8h11.4l1.3 1.3-1.3 1.3h-11.4z" fill="none" stroke="#800000" stroke-width=".21"/>
<path d="M264 121.4h11.4l1.3 1.2-1.3 1.3h-11.4z" fill-rule="evenodd" fill="#ffff80"/>
<path d="M264 121.4h11.4l1.3 1.2-1.3 1.3h-11.4z" fill="none" stroke="#800000" stroke-width=".21"/>
<path d="M264 126.4h11.4l1.3 1.3-1.3 1.3h-11.4z" fill-rule="evenodd" fill="#ffff80"/>
<path d="M264 126.4h11.4l1.3 1.3-1.3 1.3h-11.4z" fill="none" stroke="#800000" stroke-width=".21"/>
<path d="M264 129h11.4l1.3 1.2-1.3 1.3h-11.4z" fill-rule="evenodd" fill="#ffff80"/>
<path d="M264 129h11.4l1.3 1.2-1.3 1.3h-11.4z" fill="none" stroke="#800000" stroke-width=".21"/>
<path d="M264 134h11.4l1.3 1.3-1.3 1.3h-11.4z" fill-rule="evenodd" fill="#ffff80"/>
<path d="M264 134h11.4l1.3 1.3-1.3 1.3h-11.4z" fill="none" stroke="#800000" stroke-width=".21"/>
<path d="M264 136.6h11.4l1.3 1.3-1.3 1.2h-11.4z" fill-rule="evenodd" fill="#ffff80"/>
<path d="M264 136.6h11.4l1.3 1.3-1.3 1.2h-11.4z" fill="none" stroke="#800000" stroke-width=".21"/>
<path d="M264 141.7h11.4l1.3 1.2-1.3 1.3h-11.4z" fill-rule="evenodd" fill="#ffff80"/>
<path d="M264 141.7h11.4l1.3 1.2-1.3 1.3h-11.4z" fill="none" stroke="#800000" stroke-width=".21"/>
<path d="M264 144.2h11.4l1.3 1.3-1.3 1.2h-11.4z" fill-rule="evenodd" fill="#ffff80"/>
<path d="M264 144.2h11.4l1.3 1.3-1.3 1.2h-11.4z" fill="none" stroke="#800000" stroke-width=".21"/>
<path d="M119.1 65.5h16.6l1.2 1.3-1.2 1.2h-16.6z" fill-rule="evenodd" fill="#ffff80"/>
<path d="M119.1 65.5h16.6l1.2 1.3-1.2 1.2h-16.6z" fill="none" stroke="#800000" stroke-width=".21"/>
<path d="M119.1 68h16.6l1.2 1.3-1.2 1.3h-16.6z" fill-rule="evenodd" fill="#ffff80"/>
<path d="M119.1 68h16.6l1.2 1.3-1.2 1.3h-16.6z" fill="none" stroke="#800000" stroke-width=".21"/>
<path d="M119.1 70.6h16.6l1.2 1.2-1.2 1.3h-16.6z" fill-rule="evenodd" fill="#ffff80"/>
<path d="M119.1 70.6h16.6l1.2 1.2-1.2 1.3h-16.6z" fill="none" stroke="#800000" stroke-width=".21"/>
<path d="M164.9 82l1.3-1.3h11.4v2.6h-11.4z" fill-rule="evenodd" fill="#ffff80"/>
<path d="M164.9 82l1.3-1.3h11.4v2.6h-11.4z" fill="none" stroke="#800000" stroke-width=".21"/>
<path d="M119.1 73.1h16.6l1.2 1.3-1.2 1.2h-16.6z" fill-rule="evenodd" fill="#ffff80"/>
<path d="M119.1 73.1h16.6l1.2 1.3-1.2 1.2h-16.6z" fill="none" stroke="#800000" stroke-width=".21"/>
<path d="M119.1 75.6h16.6l1.2 1.3-1.2 1.3h-16.6z" fill-rule="evenodd" fill="#ffff80"/>
<path d="M119.1 75.6h16.6l1.2 1.3-1.2 1.3h-16.6z" fill="none" stroke="#800000" stroke-width=".21"/>
<path d="M30.2 112.5v2.5M96.3 112.5v2.5M30.2 120.1v2.5M96.3 120.1v2.5" fill="none" stroke="#000" stroke-width=".25"/>
<path d="M28.2 118h4M28.2 117h4M30.2 115v2M30.2 118v2.1M94.3 118h4M94.3 117h4M96.3 115v2M96.3 118v2.1" fill="none" stroke="#00f" stroke-width=".25"/>
<g fill="none" stroke="#800000" stroke-width=".25">
<path d="M13.7 104.8h2.5M14.9 104.8v2.6M27.6 127.7h5.1M28.4 128.5h3.6M29.2 129.2h2M29.9 130h.5M30.2 125.2v2.5M45.4 127.7h5.1M46.2 128.5h3.5M47 129.2h2M47.7 130h.5M48 125.2v2.5"/>
<path d="M93.7 127.7h5.1M94.5 128.5h3.5M95.2 129.2h2.1M96 130h.5M96.3 125.2v2.5"/>
</g>
<path d="M80 116.5l2 2.1M82 116.5l-2 2.1" fill="none" stroke="#f00" stroke-width=".21"/>
<path d="M58.1 107.4h15.3v12.7h-15.3z" fill-rule="evenodd" fill="#ffffb0"/>
<path d="M58.1 107.4h15.3v12.7h-15.3z" fill="none" stroke="#800000" stroke-width=".21"/>
<path d="M37.8 38.8v2M37.8 47v2M40.3 112.5v2M50.5 109.9h7.6M50.5 117.5h7.6M50.5 112.5h7.6M73.4 109.9h7.6M73.4 117.5h7.6M40.3 120.6v2" fill="none" stroke="#000" stroke-width=".25"/>
<path d="M36.7 40.9h2.1v6h-2.1zM39.3 114.5h2v6h-2z" fill="none" stroke="#00f" stroke-width=".25"/>
<path d="M35.3 54.1h5M36 54.8h3.6M36.8 55.6h2M37.6 56.3h.5M37.8 51.5v2.6M37.8 127.7h5.1M38.6 128.5h3.5M39.3 129.2h2.1M40.1 130h.5M40.3 125.2v2.5" fill="none" stroke="#800000" stroke-width=".25"/>
<path d="M22.6 85.8h11.4l1.3 1.3-1.3 1.2h-11.4z" fill-rule="evenodd" fill="#ffff80"/>
<path d="M22.6 85.8h11.4l1.3 1.3-1.3 1.2h-11.4z" fill="none" stroke="#800000" stroke-width=".21"/>
<path d="M17.5 26.1h2M25.6 26.1h2M124.2 26.1h4.5M124.2 36.3h4.5M129.9 26.1h4.5M129.9 36.3h4.5M17.5 109.9h2M25.6 109.9h2" fill="none" stroke="#000" stroke-width=".25"/>
<path d="M19.6 25.1h6v2.1h-6zM129.3 24.8h1.3l-1.3 2.6h-1.3zM129.3 35h1.3l-1.3 2.6h-1.3zM19.6 108.9h6v2.1h-6z" fill="none" stroke="#00f" stroke-width=".25"/>
<path d="M136.9 26.1h2.6M136.9 36.3h2.6M139.5 24.8v2.6M139.5 35v2.6" fill="none" stroke="#800000" stroke-width=".25"/>
<path d="M22.6 82l1.2-1.3h11.5v2.6h-11.5z" fill-rule="evenodd" fill="#ffff80"/>
<path d="M22.6 82l1.2-1.3h11.5v2.6h-11.5z" fill="none" stroke="#800000" stroke-width=".21"/>
<path d="M53.1 69.3v2M53.1 77.4v2.1M187.8 150.6v2M187.8 158.7v2" fill="none" stroke="#000" stroke-width=".25"/>
<path d="M52 71.4h2v6h-2zM186.8 152.6h2v6h-2z" fill="none" stroke="#00f" stroke-width=".25"/>
<path d="M51.8 66.8h2.5M53.1 66.8v2.5" fill="none" stroke="#800000" stroke-width=".25"/>
<path d="M88.6 145.5h17.8v22.8h-17.8z" fill-rule="evenodd" fill="#ffffb0"/>
<path d="M88.6 145.5h17.8v22.8h-17.8z" fill="none" stroke="#800000" stroke-width=".21"/>
<path d="M81 148h7.6M81 150.6h7.6M81 155.6h7.6M81 158.2h7.6M106.4 155.6h7.7M106.4 158.2h7.7M45.4 163.3v2M45.4 171.4v2M50.5 163.3v2M50.5 171.4v2M81 163.3h7.6M81 165.8h7.6" fill="none" stroke="#000" stroke-width=".25"/>
<path d="M46.7 155.6h2.5M48 155.6v2.6M75.9 170.9h5.1M76.7 171.6h3.6M77.5 172.4h2M78.2 173.2h.5M78.5 168.3v2.6" fill="none" stroke="#800000" stroke-width=".25"/>
<path d="M44.4 165.3h2v6h-2zM49.5 165.3h2v6h-2z" fill="none" stroke="#00f" stroke-width=".25"/>
<path d="M22.6 177.2h13.9l1.3 1.3-1.3 1.3h-13.9z" fill-rule="evenodd" fill="#ffff80"/>
<path d="M22.6 177.2h13.9l1.3 1.3-1.3 1.3h-13.9z" fill="none" stroke="#800000" stroke-width=".21"/>
<path d="M22.6 174.7h13.9l1.3 1.3-1.3 1.2h-13.9z" fill-rule="evenodd" fill="#ffff80"/>
<path d="M22.6 174.7h13.9l1.3 1.3-1.3 1.2h-13.9z" fill="none" stroke="#800000" stroke-width=".21"/>
<path d="M86.1 112.5v2.5M106.4 112.5v2.5M86.1 120.1v2.5M106.4 120.1v2.5M60.7 153.1v2M60.7 161.3v2" fill="none" stroke="#000" stroke-width=".25"/>
<path d="M84.1 118h4M84.1 117h4M86.1 115v2M86.1 118v2.1M104.4 118h4M104.4 117h4M106.4 115v2M106.4 118v2.1M59.6 155.2h2.1v6h-2.1z" fill="none" stroke="#00f" stroke-width=".25"/>
<g fill="none" stroke="#800000" stroke-width=".25">
<path d="M83.6 127.7h5M84.3 128.5h3.6M85.1 129.2h2M85.8 130h.5M86.1 125.2v2.5M103.9 127.7h5.1M104.6 128.5h3.6M105.4 129.2h2M106.2 130h.5M106.4 125.2v2.5M58.1 168.3h5.1M58.9 169.1h3.6"/>
<path d="M59.7 169.9h2M60.4 170.6h.5M60.7 165.8v2.5"/>
</g>
<path d="M22.6 149.3h13.9l1.3 1.3-1.3 1.2h-13.9z" fill-rule="evenodd" fill="#ffff80"/>
<path d="M22.6 149.3h13.9l1.3 1.3-1.3 1.2h-13.9z" fill="none" stroke="#800000" stroke-width=".21"/>
<path d="M116.6 160.7v2M116.6 168.9v2M121.7 160.7v2M121.7 168.9v2" fill="none" stroke="#000" stroke-width=".25"/>
<path d="M115.6 162.8h2.1v6h-2.1zM120.7 162.8h2v6h-2z" fill="none" stroke="#00f" stroke-width=".25"/>
<path d="M116.6 178.5h5.1M117.4 179.3h3.5M119.1 176v2.5M118.1 180h2.1M118.9 180.8h.5" fill="none" stroke="#800000" stroke-width=".25"/>
<path d="M120.7 154h1l.5-.5h1l.5 .5h1M120.7 154.6h1l.5 .5h1l.5-.5h1M120.7 156.5h1l.5-.5h1l.5 .5h1M120.7 157.2h1l.5 .5h1l.5-.5h1" fill="none" stroke="#d0a19e" stroke-width=".25"/>
<path d="M120.7 154.6l-1.6 1M120.7 157.2l-1.6 1" fill="none" stroke="#d0a19e" stroke-width=".21"/>
<path d="M120.4 153.7h1l.5-.5h1l.6 .5h1M120.4 154.4h1l.5 .5h1l.6-.5h1M120.4 156.3h1l.5-.5h1l.6 .5h1M120.4 156.9h1l.5 .5h1l.6-.5h1" fill="none" stroke="#f00" stroke-width=".25"/>
<path d="M120.4 154.4l-1.3 1.2M120.4 156.9l-1.3 1.3" fill="none" stroke="#f00" stroke-width=".21"/>
<circle cx="14.9" cy="26.1" r=".51" fill="#000080"/>
<circle cx="14.9" cy="26.1" r=".51" fill="none" stroke="#000080" stroke-width=".21"/>
<path d="M14.9 26.1v2.6" fill="none" stroke="#000" stroke-width=".25"/>
<circle cx="14.9" cy="26.1" r=".51" fill="#000080"/>
<circle cx="14.9" cy="26.1" r=".51" fill="none" stroke="#000080" stroke-width=".21"/>
<circle cx="14.9" cy="29.9" r="1.27" fill="none" stroke="#000" stroke-width=".25"/>
<circle cx="32.7" cy="26.1" r=".51" fill="#000080"/>
<circle cx="32.7" cy="26.1" r=".51" fill="none" stroke="#000080" stroke-width=".21"/>
<path d="M32.7 23.6v2.5" fill="none" stroke="#000" stroke-width=".25"/>
<circle cx="32.7" cy="26.1" r=".51" fill="#000080"/>
<circle cx="32.7" cy="26.1" r=".51" fill="none" stroke="#000080" stroke-width=".21"/>
<circle cx="32.7" cy="22.3" r="1.27" fill="none" stroke="#000" stroke-width=".25"/>
<circle cx="14.9" cy="109.9" r=".51" fill="#000080"/>
<circle cx="14.9" cy="109.9" r=".51" fill="none" stroke="#000080" stroke-width=".21"/>
<path d="M14.9 109.9v2.6" fill="none" stroke="#000" stroke-width=".25"/>
<circle cx="14.9" cy="109.9" r=".51" fill="#000080"/>
<circle cx="14.9" cy="109.9" r=".51" fill="none" stroke="#000080" stroke-width=".21"/>
<circle cx="14.9" cy="113.7" r="1.27" fill="none" stroke="#000" stroke-width=".25"/>
<circle cx="32.7" cy="109.9" r=".51" fill="#000080"/>
<circle cx="32.7" cy="109.9" r=".51" fill="none" stroke="#000080" stroke-width=".21"/>
<path d="M32.7 107.4v2.5" fill="none" stroke="#000" stroke-width=".25"/>
<circle cx="32.7" cy="109.9" r=".51" fill="#000080"/>
<circle cx="32.7" cy="109.9" r=".51" fill="none" stroke="#000080" stroke-width=".21"/>
<circle cx="32.7" cy="106.1" r="1.27" fill="none" stroke="#000" stroke-width=".25"/>
<circle cx="37.8" cy="82" r=".51" fill="#000080"/>
<circle cx="37.8" cy="82" r=".51" fill="none" stroke="#000080" stroke-width=".21"/>
<path d="M37.8 79.5v2.5" fill="none" stroke="#000" stroke-width=".25"/>
<circle cx="37.8" cy="82" r=".51" fill="#000080"/>
<circle cx="37.8" cy="82" r=".51" fill="none" stroke="#000080" stroke-width=".21"/>
<circle cx="37.8" cy="78.2" r="1.27" fill="none" stroke="#000" stroke-width=".25"/>
<circle cx="37.8" cy="87.1" r=".51" fill="#000080"/>
<circle cx="37.8" cy="87.1" r=".51" fill="none" stroke="#000080" stroke-width=".21"/>
<path d="M37.8 87.1v2.5" fill="none" stroke="#000" stroke-width=".25"/>
<circle cx="37.8" cy="87.1" r=".51" fill="#000080"/>
<circle cx="37.8" cy="87.1" r=".51" fill="none" stroke="#000080" stroke-width=".21"/>
<circle cx="37.8" cy="90.9" r="1.27" fill="none" stroke="#000" stroke-width=".25"/>
<circle cx="40.3" cy="150.6" r=".51" fill="#000080"/>
<circle cx="40.3" cy="150.6" r=".51" fill="none" stroke="#000080" stroke-width=".21"/>
<path d="M40.3 148v2.6" fill="none" stroke="#000" stroke-width=".25"/>
<circle cx="40.3" cy="150.6" r=".51" fill="#000080"/>
<circle cx="40.3" cy="150.6" r=".51" fill="none" stroke="#000080" stroke-width=".21"/>
<circle cx="40.3" cy="146.8" r="1.27" fill="none" stroke="#000" stroke-width=".25"/>
<circle cx="40.4" cy="176" r=".51" fill="#000080"/>
<circle cx="40.4" cy="176" r=".51" fill="none" stroke="#000080" stroke-width=".21"/>
<path d="M40.4 173.4v2.6" fill="none" stroke="#000" stroke-width=".25"/>
<circle cx="40.4" cy="176" r=".51" fill="#000080"/>
<circle cx="40.4" cy="176" r=".51" fill="none" stroke="#000080" stroke-width=".21"/>
<circle cx="40.4" cy="172.1" r="1.27" fill="none" stroke="#000" stroke-width=".25"/>
<circle cx="40.4" cy="178.5" r=".51" fill="#000080"/>
<circle cx="40.4" cy="178.5" r=".51" fill="none" stroke="#000080" stroke-width=".21"/>
<path d="M40.4 178.5v2.5" fill="none" stroke="#000" stroke-width=".25"/>
<circle cx="40.4" cy="178.5" r=".51" fill="#000080"/>
<circle cx="40.4" cy="178.5" r=".51" fill="none" stroke="#000080" stroke-width=".21"/>
<g fill="none" stroke="#000" stroke-width=".25">
<path d="M136.9 137.9h5.1M136.9 140.4v2.5M149.6 158.2h2M157.8 158.2h2M159.8 155.6h2M168 155.6h2"/>
<circle cx="40.4" cy="182.3" r="1.27"/>
</g>
<path d="M110.2 104.8h2.6M111.5 104.8v2.6M74.7 142.9h2.5M75.9 142.9v2.6" fill="none" stroke="#800000" stroke-width=".25"/>
<g fill="none" stroke="#00f" stroke-width=".25">
<path d="M151.7 157.2h6v2h-6zM161.9 154.7h6v2h-6z"/>
<circle cx="136.9" cy="137.9" r="2.54"/>
</g>
<circle cx="136.9" cy="137.9" r=".64" fill="#00f"/>
<circle cx="136.9" cy="137.9" r=".64" fill="none" stroke="#00f" stroke-width=".21"/>
<path d="M134.4 145.5h5.1M135.1 146.2h3.6M135.9 147h2M136.7 147.8h.5M136.9 142.9v2.6" fill="none" stroke="#800000" stroke-width=".25"/>
<circle cx="154.7" cy="137.9" r="2.54" fill="none" stroke="#00f" stroke-width=".25"/>
<path d="M149.6 137.9h5.1M154.7 140.4v2.5" fill="none" stroke="#000" stroke-width=".25"/>
<circle cx="154.7" cy="137.9" r=".64" fill="#00f"/>
<circle cx="154.7" cy="137.9" r=".64" fill="none" stroke="#00f" stroke-width=".21"/>
<path d="M152.2 145.5h5.1M152.9 146.2h3.6M153.7 147h2M154.5 147.8h.5M154.7 142.9v2.6" fill="none" stroke="#800000" stroke-width=".25"/>
<path d="M48 41.4h-2.6v2.5h2.6" fill="none" stroke="#000080" stroke-width=".25"/>
<circle cx="45.4" cy="43.9" r=".51" fill="#000080"/>
<circle cx="45.4" cy="43.9" r=".51" fill="none" stroke="#000080" stroke-width=".21"/>
<path d="M45.4 43.9v7.6" fill="none" stroke="#000080" stroke-width=".25"/>
<circle cx="45.4" cy="43.9" r=".51" fill="#000080"/>
<circle cx="45.4" cy="43.9" r=".51" fill="none" stroke="#000080" stroke-width=".21"/>
<path d="M45.4 26.1v2.6h2.6" fill="none" stroke="#000080" stroke-width=".25"/>
<circle cx="45.4" cy="28.7" r=".51" fill="#000080"/>
<circle cx="45.4" cy="28.7" r=".51" fill="none" stroke="#000080" stroke-width=".21"/>
<circle cx="45.4" cy="26.1" r=".51" fill="#000080"/>
<circle cx="45.4" cy="26.1" r=".51" fill="none" stroke="#000080" stroke-width=".21"/>
<path d="M45.4 28.7v5h2.6" fill="none" stroke="#000080" stroke-width=".25"/>
<circle cx="45.4" cy="28.7" r=".51" fill="#000080"/>
<circle cx="45.4" cy="28.7" r=".51" fill="none" stroke="#000080" stroke-width=".21"/>
<path d="M30.2 38.8v2.6M98.8 38.8v2.6M83.6 43.9h2.5v2.5M86.1 56.6v2.5" fill="none" stroke="#000080" stroke-width=".25"/>
<circle cx="98.8" cy="41.4" r=".51" fill="#000080"/>
<circle cx="98.8" cy="41.4" r=".51" fill="none" stroke="#000080" stroke-width=".21"/>
<path d="M98.8 26.1v2.6M114.1 38.8v2.6M106.4 56.6v2.5" fill="none" stroke="#000080" stroke-width=".25"/>
<circle cx="98.8" cy="26.1" r=".51" fill="#000080"/>
<circle cx="98.8" cy="26.1" r=".51" fill="none" stroke="#000080" stroke-width=".21"/>
<path d="M106.4 38.8v2.6" fill="none" stroke="#000080" stroke-width=".25"/>
<circle cx="106.4" cy="41.4" r=".51" fill="#000080"/>
<circle cx="106.4" cy="41.4" r=".51" fill="none" stroke="#000080" stroke-width=".21"/>
<path d="M106.4 26.1v2.6" fill="none" stroke="#000080" stroke-width=".25"/>
<circle cx="106.4" cy="26.1" r=".51" fill="#000080"/>
<circle cx="106.4" cy="26.1" r=".51" fill="none" stroke="#000080" stroke-width=".21"/>
<path d="M172.5 64.2v2.6h20.3" fill="none" stroke="#000080" stroke-width=".25"/>
<circle cx="172.5" cy="66.8" r=".51" fill="#000080"/>
<circle cx="172.5" cy="66.8" r=".51" fill="none" stroke="#000080" stroke-width=".21"/>
<path d="M167.4 64.2v5.1h25.4" fill="none" stroke="#000080" stroke-width=".25"/>
<circle cx="167.4" cy="69.3" r=".51" fill="#000080"/>
<circle cx="167.4" cy="69.3" r=".51" fill="none" stroke="#000080" stroke-width=".21"/>
<path d="M162.3 64.2v7.6h30.5" fill="none" stroke="#000080" stroke-width=".25"/>
<circle cx="162.3" cy="71.8" r=".51" fill="#000080"/>
<circle cx="162.3" cy="71.8" r=".51" fill="none" stroke="#000080" stroke-width=".21"/>
<path d="M136.9 66.8h35.6" fill="none" stroke="#000080" stroke-width=".25"/>
<circle cx="172.5" cy="66.8" r=".51" fill="#000080"/>
<circle cx="172.5" cy="66.8" r=".51" fill="none" stroke="#000080" stroke-width=".21"/>
<circle cx="154.7" cy="66.8" r=".51" fill="#000080"/>
<circle cx="154.7" cy="66.8" r=".51" fill="none" stroke="#000080" stroke-width=".21"/>
<path d="M136.9 69.3h30.5" fill="none" stroke="#000080" stroke-width=".25"/>
<circle cx="167.4" cy="69.3" r=".51" fill="#000080"/>
<circle cx="167.4" cy="69.3" r=".51" fill="none" stroke="#000080" stroke-width=".21"/>
<circle cx="149.6" cy="69.3" r=".51" fill="#000080"/>
<circle cx="149.6" cy="69.3" r=".51" fill="none" stroke="#000080" stroke-width=".21"/>
<path d="M136.9 71.8h25.4" fill="none" stroke="#000080" stroke-width=".25"/>
<circle cx="144.6" cy="71.8" r=".51" fill="#000080"/>
<circle cx="144.6" cy="71.8" r=".51" fill="none" stroke="#000080" stroke-width=".21"/>
<circle cx="162.3" cy="71.8" r=".51" fill="#000080"/>
<circle cx="162.3" cy="71.8" r=".51" fill="none" stroke="#000080" stroke-width=".21"/>
<path d="M220.8 163.3h-5.1v2.5" fill="none" stroke="#000080" stroke-width=".25"/>
<circle cx="215.7" cy="163.3" r=".51" fill="#000080"/>
<circle cx="215.7" cy="163.3" r=".51" fill="none" stroke="#000080" stroke-width=".21"/>
<circle cx="218.3" cy="163.3" r=".51" fill="#000080"/>
<circle cx="218.3" cy="163.3" r=".51" fill="none" stroke="#000080" stroke-width=".21"/>
<circle cx="220.8" cy="163.3" r=".51" fill="#000080"/>
<circle cx="220.8" cy="163.3" r=".51" fill="none" stroke="#000080" stroke-width=".21"/>
<path d="M218.3 160.7v2.6" fill="none" stroke="#000080" stroke-width=".25"/>
<circle cx="218.3" cy="163.3" r=".51" fill="#000080"/>
<circle cx="218.3" cy="163.3" r=".51" fill="none" stroke="#000080" stroke-width=".21"/>
<path d="M220.8 160.7v2.6" fill="none" stroke="#000080" stroke-width=".25"/>
<circle cx="220.8" cy="163.3" r=".51" fill="#000080"/>
<circle cx="220.8" cy="163.3" r=".51" fill="none" stroke="#000080" stroke-width=".21"/>
<path d="M223.3 160.7v2.6" fill="none" stroke="#000080" stroke-width=".25"/>
<circle cx="223.3" cy="163.3" r=".51" fill="#000080"/>
<circle cx="223.3" cy="163.3" r=".51" fill="none" stroke="#000080" stroke-width=".21"/>
<path d="M231 160.7v2.6h2.5v-2.6" fill="none" stroke="#000080" stroke-width=".25"/>
<circle cx="231" cy="163.3" r=".51" fill="#000080"/>
<circle cx="231" cy="163.3" r=".51" fill="none" stroke="#000080" stroke-width=".21"/>
<path d="M231 163.3v2.5" fill="none" stroke="#000080" stroke-width=".25"/>
<circle cx="231" cy="163.3" r=".51" fill="#000080"/>
<circle cx="231" cy="163.3" r=".51" fill="none" stroke="#000080" stroke-width=".21"/>
<path d="M225.9 160.7v2.6h-5.1" fill="none" stroke="#000080" stroke-width=".25"/>
<circle cx="223.3" cy="163.3" r=".51" fill="#000080"/>
<circle cx="223.3" cy="163.3" r=".51" fill="none" stroke="#000080" stroke-width=".21"/>
<circle cx="220.8" cy="163.3" r=".51" fill="#000080"/>
<circle cx="220.8" cy="163.3" r=".51" fill="none" stroke="#000080" stroke-width=".21"/>
<path d="M215.7 160.7v2.6" fill="none" stroke="#000080" stroke-width=".25"/>
<circle cx="215.7" cy="163.3" r=".51" fill="#000080"/>
<circle cx="215.7" cy="163.3" r=".51" fill="none" stroke="#000080" stroke-width=".21"/>
<path d="M192.8 41.4h28v12.7" fill="none" stroke="#000080" stroke-width=".25"/>
<circle cx="220.8" cy="54.1" r=".51" fill="#000080"/>
<circle cx="220.8" cy="54.1" r=".51" fill="none" stroke="#000080" stroke-width=".21"/>
<circle cx="220.8" cy="41.4" r=".51" fill="#000080"/>
<circle cx="220.8" cy="41.4" r=".51" fill="none" stroke="#000080" stroke-width=".21"/>
<circle cx="203" cy="41.4" r=".51" fill="#000080"/>
<circle cx="203" cy="41.4" r=".51" fill="none" stroke="#000080" stroke-width=".21"/>
<circle cx="192.8" cy="41.4" r=".51" fill="#000080"/>
<circle cx="192.8" cy="41.4" r=".51" fill="none" stroke="#000080" stroke-width=".21"/>
<path d="M271.6 21h-45.7v33.1" fill="none" stroke="#000080" stroke-width=".25"/>
<circle cx="225.9" cy="54.1" r=".51" fill="#000080"/>
<circle cx="225.9" cy="54.1" r=".51" fill="none" stroke="#000080" stroke-width=".21"/>
<circle cx="231" cy="21" r=".51" fill="#000080"/>
<circle cx="231" cy="21" r=".51" fill="none" stroke="#000080" stroke-width=".21"/>
<circle cx="241.1" cy="21" r=".51" fill="#000080"/>
<circle cx="241.1" cy="21" r=".51" fill="none" stroke="#000080" stroke-width=".21"/>
<circle cx="251.3" cy="21" r=".51" fill="#000080"/>
<circle cx="251.3" cy="21" r=".51" fill="none" stroke="#000080" stroke-width=".21"/>
<circle cx="261.5" cy="21" r=".51" fill="#000080"/>
<circle cx="261.5" cy="21" r=".51" fill="none" stroke="#000080" stroke-width=".21"/>
<path d="M162.3 54.1v-2.6h10.2v2.6" fill="none" stroke="#000080" stroke-width=".25"/>
<circle cx="162.3" cy="51.5" r=".51" fill="#000080"/>
<circle cx="162.3" cy="51.5" r=".51" fill="none" stroke="#000080" stroke-width=".21"/>
<circle cx="167.4" cy="51.5" r=".51" fill="#000080"/>
<circle cx="167.4" cy="51.5" r=".51" fill="none" stroke="#000080" stroke-width=".21"/>
<path d="M167.4 51.5v2.6" fill="none" stroke="#000080" stroke-width=".25"/>
<circle cx="167.4" cy="51.5" r=".51" fill="#000080"/>
<circle cx="167.4" cy="51.5" r=".51" fill="none" stroke="#000080" stroke-width=".21"/>
<path d="M162.3 49v2.5" fill="none" stroke="#000080" stroke-width=".25"/>
<circle cx="162.3" cy="51.5" r=".51" fill="#000080"/>
<circle cx="162.3" cy="51.5" r=".51" fill="none" stroke="#000080" stroke-width=".21"/>
<path d="M271.6 41.4h-38.1v15.2" fill="none" stroke="#000080" stroke-width=".25"/>
<circle cx="251.3" cy="41.4" r=".51" fill="#000080"/>
<circle cx="251.3" cy="41.4" r=".51" fill="none" stroke="#000080" stroke-width=".21"/>
<circle cx="241.1" cy="41.4" r=".51" fill="#000080"/>
<circle cx="241.1" cy="41.4" r=".51" fill="none" stroke="#000080" stroke-width=".21"/>
<path d="M218.3 54.1v2.5" fill="none" stroke="#000080" stroke-width=".25"/>
<circle cx="218.3" cy="54.1" r=".51" fill="#000080"/>
<circle cx="218.3" cy="54.1" r=".51" fill="none" stroke="#000080" stroke-width=".21"/>
<path d="M225.9 56.6v-2.5h2.5v2.5" fill="none" stroke="#000080" stroke-width=".25"/>
<circle cx="225.9" cy="54.1" r=".51" fill="#000080"/>
<circle cx="225.9" cy="54.1" r=".51" fill="none" stroke="#000080" stroke-width=".21"/>
<path d="M215.7 56.6v-2.5h5.1v2.5" fill="none" stroke="#000080" stroke-width=".25"/>
<circle cx="218.3" cy="54.1" r=".51" fill="#000080"/>
<circle cx="218.3" cy="54.1" r=".51" fill="none" stroke="#000080" stroke-width=".21"/>
<circle cx="220.8" cy="54.1" r=".51" fill="#000080"/>
<circle cx="220.8" cy="54.1" r=".51" fill="none" stroke="#000080" stroke-width=".21"/>
<path d="M157.3 21h63.5v20.4" fill="none" stroke="#000080" stroke-width=".25"/>
<circle cx="220.8" cy="41.4" r=".51" fill="#000080"/>
<circle cx="220.8" cy="41.4" r=".51" fill="none" stroke="#000080" stroke-width=".21"/>
<circle cx="213.2" cy="21" r=".51" fill="#000080"/>
<circle cx="213.2" cy="21" r=".51" fill="none" stroke="#000080" stroke-width=".21"/>
<circle cx="203" cy="21" r=".51" fill="#000080"/>
<circle cx="203" cy="21" r=".51" fill="none" stroke="#000080" stroke-width=".21"/>
<circle cx="192.8" cy="21" r=".51" fill="#000080"/>
<circle cx="192.8" cy="21" r=".51" fill="none" stroke="#000080" stroke-width=".21"/>
<circle cx="182.7" cy="21" r=".51" fill="#000080"/>
<circle cx="182.7" cy="21" r=".51" fill="none" stroke="#000080" stroke-width=".21"/>
<circle cx="172.5" cy="21" r=".51" fill="#000080"/>
<circle cx="172.5" cy="21" r=".51" fill="none" stroke="#000080" stroke-width=".21"/>
<circle cx="162.3" cy="21" r=".51" fill="#000080"/>
<circle cx="162.3" cy="21" r=".51" fill="none" stroke="#000080" stroke-width=".21"/>
<path d="M157.3 41.4h35.5" fill="none" stroke="#000080" stroke-width=".25"/>
<circle cx="182.7" cy="41.4" r=".51" fill="#000080"/>
<circle cx="182.7" cy="41.4" r=".51" fill="none" stroke="#000080" stroke-width=".21"/>
<circle cx="192.8" cy="41.4" r=".51" fill="#000080"/>
<circle cx="192.8" cy="41.4" r=".51" fill="none" stroke="#000080" stroke-width=".21"/>
<path d="M177.6 87.1h15.2" fill="none" stroke="#000080" stroke-width=".25"/>
<circle cx="187.8" cy="87.1" r=".51" fill="#000080"/>
<circle cx="187.8" cy="87.1" r=".51" fill="none" stroke="#000080" stroke-width=".21"/>
<path d="M177.6 97.2h15.2" fill="none" stroke="#000080" stroke-width=".25"/>
<circle cx="187.8" cy="97.2" r=".51" fill="#000080"/>
<circle cx="187.8" cy="97.2" r=".51" fill="none" stroke="#000080" stroke-width=".21"/>
<path d="M177.6 102.3h15.2" fill="none" stroke="#000080" stroke-width=".25"/>
<circle cx="187.8" cy="102.3" r=".51" fill="#000080"/>
<circle cx="187.8" cy="102.3" r=".51" fill="none" stroke="#000080" stroke-width=".21"/>
<path d="M177.6 112.5h15.2" fill="none" stroke="#000080" stroke-width=".25"/>
<circle cx="187.8" cy="112.5" r=".51" fill="#000080"/>
<circle cx="187.8" cy="112.5" r=".51" fill="none" stroke="#000080" stroke-width=".21"/>
<path d="M177.6 117.5h15.2" fill="none" stroke="#000080" stroke-width=".25"/>
<circle cx="187.8" cy="117.5" r=".51" fill="#000080"/>
<circle cx="187.8" cy="117.5" r=".51" fill="none" stroke="#000080" stroke-width=".21"/>
<path d="M177.6 127.7h15.2" fill="none" stroke="#000080" stroke-width=".25"/>
<circle cx="187.8" cy="127.7" r=".51" fill="#000080"/>
<circle cx="187.8" cy="127.7" r=".51" fill="none" stroke="#000080" stroke-width=".21"/>
<path d="M177.6 132.8h15.2" fill="none" stroke="#000080" stroke-width=".25"/>
<circle cx="187.8" cy="132.8" r=".51" fill="#000080"/>
<circle cx="187.8" cy="132.8" r=".51" fill="none" stroke="#000080" stroke-width=".21"/>
<path d="M177.6 142.9h15.2" fill="none" stroke="#000080" stroke-width=".25"/>
<circle cx="187.8" cy="142.9" r=".51" fill="#000080"/>
<circle cx="187.8" cy="142.9" r=".51" fill="none" stroke="#000080" stroke-width=".21"/>
<g fill="none" stroke="#000080" stroke-width=".25">
<path d="M136.9 74.4h55.9M256.4 74.4h7.6M256.4 76.9h7.6M256.4 82h7.6M256.4 84.5h7.6M256.4 89.6h7.6M256.4 92.2h7.6M256.4 97.2h7.6M256.4 99.8h7.6M256.4 104.9h7.6M256.4 107.4h7.6M256.4 112.5h7.6"/>
<path d="M256.4 115h7.6M256.4 120.1h7.6M256.4 122.6h7.6M256.4 127.7h7.6M256.4 130.2h7.6M256.4 135.3h7.6M256.4 137.9h7.6M256.4 142.9h7.6M256.4 145.5h7.6"/>
</g>
<circle cx="149.6" cy="74.4" r=".51" fill="#000080"/>
<circle cx="149.6" cy="74.4" r=".51" fill="none" stroke="#000080" stroke-width=".21"/>
<path d="M136.9 76.9h55.9" fill="none" stroke="#000080" stroke-width=".25"/>
<circle cx="144.6" cy="76.9" r=".51" fill="#000080"/>
<circle cx="144.6" cy="76.9" r=".51" fill="none" stroke="#000080" stroke-width=".21"/>
<path d="M48 36.3h-10.2v2.5M37.8 49v2.5M177.6 82h15.2M50.5 117.5h-2.5v7.7M50.5 109.9h-20.3v2.6" fill="none" stroke="#000080" stroke-width=".25"/>
<circle cx="32.7" cy="109.9" r=".51" fill="#000080"/>
<circle cx="32.7" cy="109.9" r=".51" fill="none" stroke="#000080" stroke-width=".21"/>
<circle cx="30.2" cy="109.9" r=".51" fill="#000080"/>
<circle cx="30.2" cy="109.9" r=".51" fill="none" stroke="#000080" stroke-width=".21"/>
<path d="M35.3 87.1h15.2M40.3 112.5h10.2M30.2 122.6v2.6M40.3 122.6v2.6" fill="none" stroke="#000080" stroke-width=".25"/>
<circle cx="37.8" cy="87.1" r=".51" fill="#000080"/>
<circle cx="37.8" cy="87.1" r=".51" fill="none" stroke="#000080" stroke-width=".21"/>
<path d="M30.2 26.1h17.8" fill="none" stroke="#000080" stroke-width=".25"/>
<circle cx="30.2" cy="26.1" r=".51" fill="#000080"/>
<circle cx="30.2" cy="26.1" r=".51" fill="none" stroke="#000080" stroke-width=".21"/>
<circle cx="32.7" cy="26.1" r=".51" fill="#000080"/>
<circle cx="32.7" cy="26.1" r=".51" fill="none" stroke="#000080" stroke-width=".21"/>
<circle cx="45.4" cy="26.1" r=".51" fill="#000080"/>
<circle cx="45.4" cy="26.1" r=".51" fill="none" stroke="#000080" stroke-width=".21"/>
<path d="M14.9 23.6v2.5h2.6" fill="none" stroke="#000080" stroke-width=".25"/>
<circle cx="14.9" cy="26.1" r=".51" fill="#000080"/>
<circle cx="14.9" cy="26.1" r=".51" fill="none" stroke="#000080" stroke-width=".21"/>
<path d="M27.6 26.1h2.6" fill="none" stroke="#000080" stroke-width=".25"/>
<circle cx="30.2" cy="26.1" r=".51" fill="#000080"/>
<circle cx="30.2" cy="26.1" r=".51" fill="none" stroke="#000080" stroke-width=".21"/>
<path d="M30.2 26.1v2.6" fill="none" stroke="#000080" stroke-width=".25"/>
<circle cx="30.2" cy="26.1" r=".51" fill="#000080"/>
<circle cx="30.2" cy="26.1" r=".51" fill="none" stroke="#000080" stroke-width=".21"/>
<path d="M14.9 107.4v2.5h2.6" fill="none" stroke="#000080" stroke-width=".25"/>
<circle cx="14.9" cy="109.9" r=".51" fill="#000080"/>
<circle cx="14.9" cy="109.9" r=".51" fill="none" stroke="#000080" stroke-width=".21"/>
<path d="M27.6 109.9h2.6" fill="none" stroke="#000080" stroke-width=".25"/>
<circle cx="30.2" cy="109.9" r=".51" fill="#000080"/>
<circle cx="30.2" cy="109.9" r=".51" fill="none" stroke="#000080" stroke-width=".21"/>
<path d="M121.7 26.1v10.2h2.5" fill="none" stroke="#000080" stroke-width=".25"/>
<circle cx="121.7" cy="26.1" r=".51" fill="#000080"/>
<circle cx="121.7" cy="26.1" r=".51" fill="none" stroke="#000080" stroke-width=".21"/>
<path d="M106.4 26.1h17.8M134.4 26.1h2.5M134.4 36.3h2.5" fill="none" stroke="#000080" stroke-width=".25"/>
<circle cx="106.4" cy="26.1" r=".51" fill="#000080"/>
<circle cx="106.4" cy="26.1" r=".51" fill="none" stroke="#000080" stroke-width=".21"/>
<circle cx="114.1" cy="26.1" r=".51" fill="#000080"/>
<circle cx="114.1" cy="26.1" r=".51" fill="none" stroke="#000080" stroke-width=".21"/>
<circle cx="119.1" cy="26.1" r=".51" fill="#000080"/>
<circle cx="119.1" cy="26.1" r=".51" fill="none" stroke="#000080" stroke-width=".21"/>
<circle cx="121.7" cy="26.1" r=".51" fill="#000080"/>
<circle cx="121.7" cy="26.1" r=".51" fill="none" stroke="#000080" stroke-width=".21"/>
<path d="M83.6 33.7h10.1v7.7h12.7v5" fill="none" stroke="#000080" stroke-width=".25"/>
<circle cx="106.4" cy="41.4" r=".51" fill="#000080"/>
<circle cx="106.4" cy="41.4" r=".51" fill="none" stroke="#000080" stroke-width=".21"/>
<circle cx="98.8" cy="41.4" r=".51" fill="#000080"/>
<circle cx="98.8" cy="41.4" r=".51" fill="none" stroke="#000080" stroke-width=".21"/>
<path d="M83.6 26.1h10.1v2.6h-10.1" fill="none" stroke="#000080" stroke-width=".25"/>
<circle cx="93.7" cy="26.1" r=".51" fill="#000080"/>
<circle cx="93.7" cy="26.1" r=".51" fill="none" stroke="#000080" stroke-width=".21"/>
<path d="M93.7 26.1h12.7" fill="none" stroke="#000080" stroke-width=".25"/>
<circle cx="93.7" cy="26.1" r=".51" fill="#000080"/>
<circle cx="93.7" cy="26.1" r=".51" fill="none" stroke="#000080" stroke-width=".21"/>
<circle cx="98.8" cy="26.1" r=".51" fill="#000080"/>
<circle cx="98.8" cy="26.1" r=".51" fill="none" stroke="#000080" stroke-width=".21"/>
<circle cx="106.4" cy="26.1" r=".51" fill="#000080"/>
<circle cx="106.4" cy="26.1" r=".51" fill="none" stroke="#000080" stroke-width=".21"/>
<path d="M114.1 26.1v2.6" fill="none" stroke="#000080" stroke-width=".25"/>
<circle cx="114.1" cy="26.1" r=".51" fill="#000080"/>
<circle cx="114.1" cy="26.1" r=".51" fill="none" stroke="#000080" stroke-width=".21"/>
<path d="M83.6 38.8h7.6M53.1 79.5v2.5h-17.8" fill="none" stroke="#000080" stroke-width=".25"/>
<circle cx="37.8" cy="82" r=".51" fill="#000080"/>
<circle cx="37.8" cy="82" r=".51" fill="none" stroke="#000080" stroke-width=".21"/>
<path d="M81 163.3h-2.5v5" fill="none" stroke="#000080" stroke-width=".25"/>
<circle cx="78.5" cy="165.8" r=".51" fill="#000080"/>
<circle cx="78.5" cy="165.8" r=".51" fill="none" stroke="#000080" stroke-width=".21"/>
<path d="M78.5 165.8h2.5" fill="none" stroke="#000080" stroke-width=".25"/>
<circle cx="78.5" cy="165.8" r=".51" fill="#000080"/>
<circle cx="78.5" cy="165.8" r=".51" fill="none" stroke="#000080" stroke-width=".21"/>
<path d="M48 160.7h-2.6v2.6" fill="none" stroke="#000080" stroke-width=".25"/>
<circle cx="48" cy="160.7" r=".51" fill="#000080"/>
<circle cx="48" cy="160.7" r=".51" fill="none" stroke="#000080" stroke-width=".21"/>
<path d="M48 158.2v2.5h2.5v2.6" fill="none" stroke="#000080" stroke-width=".25"/>
<circle cx="48" cy="160.7" r=".51" fill="#000080"/>
<circle cx="48" cy="160.7" r=".51" fill="none" stroke="#000080" stroke-width=".21"/>
<path d="M45.4 173.4v2.6" fill="none" stroke="#000080" stroke-width=".25"/>
<circle cx="45.4" cy="176" r=".51" fill="#000080"/>
<circle cx="45.4" cy="176" r=".51" fill="none" stroke="#000080" stroke-width=".21"/>
<path d="M50.5 173.4v5.1" fill="none" stroke="#000080" stroke-width=".25"/>
<circle cx="50.5" cy="178.5" r=".51" fill="#000080"/>
<circle cx="50.5" cy="178.5" r=".51" fill="none" stroke="#000080" stroke-width=".21"/>
<path d="M86.1 109.9v2.6" fill="none" stroke="#000080" stroke-width=".25"/>
<circle cx="86.1" cy="109.9" r=".51" fill="#000080"/>
<circle cx="86.1" cy="109.9" r=".51" fill="none" stroke="#000080" stroke-width=".21"/>
<path d="M187.8 160.7v2.6" fill="none" stroke="#000080" stroke-width=".25"/>
<circle cx="187.8" cy="163.3" r=".51" fill="#000080"/>
<circle cx="187.8" cy="163.3" r=".51" fill="none" stroke="#000080" stroke-width=".21"/>
<path d="M187.8 148v2.6" fill="none" stroke="#000080" stroke-width=".25"/>
<circle cx="187.8" cy="148" r=".51" fill="#000080"/>
<circle cx="187.8" cy="148" r=".51" fill="none" stroke="#000080" stroke-width=".21"/>
<path d="M96.3 109.9v2.6" fill="none" stroke="#000080" stroke-width=".25"/>
<circle cx="96.3" cy="109.9" r=".51" fill="#000080"/>
<circle cx="96.3" cy="109.9" r=".51" fill="none" stroke="#000080" stroke-width=".21"/>
<path d="M86.1 122.6v2.6M96.3 122.6v2.6M106.4 122.6v2.6M81 155.6h-12.7v20.4h-30.5" fill="none" stroke="#000080" stroke-width=".25"/>
<circle cx="40.4" cy="176" r=".51" fill="#000080"/>
<circle cx="40.4" cy="176" r=".51" fill="none" stroke="#000080" stroke-width=".21"/>
<circle cx="45.4" cy="176" r=".51" fill="#000080"/>
<circle cx="45.4" cy="176" r=".51" fill="none" stroke="#000080" stroke-width=".21"/>
<path d="M81 158.2h-10.1v20.3h-33.1" fill="none" stroke="#000080" stroke-width=".25"/>
<circle cx="40.4" cy="178.5" r=".51" fill="#000080"/>
<circle cx="40.4" cy="178.5" r=".51" fill="none" stroke="#000080" stroke-width=".21"/>
<circle cx="50.5" cy="178.5" r=".51" fill="#000080"/>
<circle cx="50.5" cy="178.5" r=".51" fill="none" stroke="#000080" stroke-width=".21"/>
<path d="M81 150.6h-20.3v2.5" fill="none" stroke="#000080" stroke-width=".25"/>
<circle cx="60.7" cy="150.6" r=".51" fill="#000080"/>
<circle cx="60.7" cy="150.6" r=".51" fill="none" stroke="#000080" stroke-width=".21"/>
<path d="M37.8 150.6h22.9" fill="none" stroke="#000080" stroke-width=".25"/>
<circle cx="60.7" cy="150.6" r=".51" fill="#000080"/>
<circle cx="60.7" cy="150.6" r=".51" fill="none" stroke="#000080" stroke-width=".21"/>
<circle cx="40.3" cy="150.6" r=".51" fill="#000080"/>
<circle cx="40.3" cy="150.6" r=".51" fill="none" stroke="#000080" stroke-width=".21"/>
<path d="M60.7 163.3v2.5M116.6 170.9v2.5h5.1v-2.5" fill="none" stroke="#000080" stroke-width=".25"/>
<circle cx="119.1" cy="173.4" r=".51" fill="#000080"/>
<circle cx="119.1" cy="173.4" r=".51" fill="none" stroke="#000080" stroke-width=".21"/>
<path d="M119.1 173.4v2.6" fill="none" stroke="#000080" stroke-width=".25"/>
<circle cx="119.1" cy="173.4" r=".51" fill="#000080"/>
<circle cx="119.1" cy="173.4" r=".51" fill="none" stroke="#000080" stroke-width=".21"/>
<path d="M116.6 155.6v5.1" fill="none" stroke="#000080" stroke-width=".25"/>
<circle cx="116.6" cy="155.6" r=".51" fill="#000080"/>
<circle cx="116.6" cy="155.6" r=".51" fill="none" stroke="#000080" stroke-width=".21"/>
<path d="M121.7 158.2v2.5" fill="none" stroke="#000080" stroke-width=".25"/>
<circle cx="121.7" cy="158.2" r=".51" fill="#000080"/>
<circle cx="121.7" cy="158.2" r=".51" fill="none" stroke="#000080" stroke-width=".21"/>
<path d="M81 109.9h25.4v2.6" fill="none" stroke="#000080" stroke-width=".25"/>
<circle cx="86.1" cy="109.9" r=".51" fill="#000080"/>
<circle cx="86.1" cy="109.9" r=".51" fill="none" stroke="#000080" stroke-width=".21"/>
<circle cx="96.3" cy="109.9" r=".51" fill="#000080"/>
<circle cx="96.3" cy="109.9" r=".51" fill="none" stroke="#000080" stroke-width=".21"/>
<circle cx="101.3" cy="109.9" r=".51" fill="#000080"/>
<circle cx="101.3" cy="109.9" r=".51" fill="none" stroke="#000080" stroke-width=".21"/>
<circle cx="106.4" cy="109.9" r=".51" fill="#000080"/>
<circle cx="106.4" cy="109.9" r=".51" fill="none" stroke="#000080" stroke-width=".21"/>
<path d="M111.5 107.4v2.5h-5.1" fill="none" stroke="#000080" stroke-width=".25"/>
<circle cx="106.4" cy="109.9" r=".51" fill="#000080"/>
<circle cx="106.4" cy="109.9" r=".51" fill="none" stroke="#000080" stroke-width=".21"/>
<path d="M75.9 145.5v2.5h5.1M114.1 158.2h35.5" fill="none" stroke="#000080" stroke-width=".25"/>
<circle cx="121.7" cy="158.2" r=".51" fill="#000080"/>
<circle cx="121.7" cy="158.2" r=".51" fill="none" stroke="#000080" stroke-width=".21"/>
<circle cx="144.6" cy="158.2" r=".51" fill="#000080"/>
<circle cx="144.6" cy="158.2" r=".51" fill="none" stroke="#000080" stroke-width=".21"/>
<path d="M114.1 155.6h45.7" fill="none" stroke="#000080" stroke-width=".25"/>
<circle cx="116.6" cy="155.6" r=".51" fill="#000080"/>
<circle cx="116.6" cy="155.6" r=".51" fill="none" stroke="#000080" stroke-width=".21"/>
<circle cx="147.1" cy="155.6" r=".51" fill="#000080"/>
<circle cx="147.1" cy="155.6" r=".51" fill="none" stroke="#000080" stroke-width=".21"/>
<path d="M192.8 150.6v12.7h-10.1v-5.1h-22.9" fill="none" stroke="#000080" stroke-width=".25"/>
<circle cx="187.8" cy="163.3" r=".51" fill="#000080"/>
<circle cx="187.8" cy="163.3" r=".51" fill="none" stroke="#000080" stroke-width=".21"/>
<path d="M192.8 148h-10.1v7.6h-12.7" fill="none" stroke="#000080" stroke-width=".25"/>
<circle cx="187.8" cy="148" r=".51" fill="#000080"/>
<circle cx="187.8" cy="148" r=".51" fill="none" stroke="#000080" stroke-width=".21"/>
<path d="M142 137.9h2.6v20.3" fill="none" stroke="#000080" stroke-width=".25"/>
<circle cx="144.6" cy="158.2" r=".51" fill="#000080"/>
<circle cx="144.6" cy="158.2" r=".51" fill="none" stroke="#000080" stroke-width=".21"/>
<path d="M149.6 137.9h-2.5v17.7" fill="none" stroke="#000080" stroke-width=".25"/>
<circle cx="147.1" cy="155.6" r=".51" fill="#000080"/>
<circle cx="147.1" cy="155.6" r=".51" fill="none" stroke="#000080" stroke-width=".21"/>
<circle cx="119.1" cy="26.1" r=".51" fill="#000080"/>
<circle cx="119.1" cy="26.1" r=".51" fill="none" stroke="#000080" stroke-width=".21"/>
<path d="M119.1 23.6v2.5" fill="none" stroke="#000" stroke-width=".25"/>
<circle cx="119.1" cy="26.1" r=".51" fill="#000080"/>
<circle cx="119.1" cy="26.1" r=".51" fill="none" stroke="#000080" stroke-width=".21"/>
<circle cx="119.1" cy="22.3" r="1.27" fill="none" stroke="#000" stroke-width=".25"/>
<circle cx="101.3" cy="109.9" r=".51" fill="#000080"/>
<circle cx="101.3" cy="109.9" r=".51" fill="none" stroke="#000080" stroke-width=".21"/>
<path d="M101.3 107.4v2.5" fill="none" stroke="#000" stroke-width=".25"/>
<circle cx="101.3" cy="109.9" r=".51" fill="#000080"/>
<circle cx="101.3" cy="109.9" r=".51" fill="none" stroke="#000080" stroke-width=".21"/>
<g fill="none" stroke="#000" stroke-width=".25">
<path d="M144.6 61.7v2.5M144.6 79.5v2.5M149.6 61.7v2.5M149.6 79.5v2.5M154.7 61.7v2.5"/>
<circle cx="144.6" cy="60.4" r="1.27"/>
<circle cx="149.6" cy="60.4" r="1.27"/>
<circle cx="154.7" cy="60.4" r="1.27"/>
<circle cx="144.6" cy="83.3" r="1.27"/>
<circle cx="149.6" cy="83.3" r="1.27"/>
<circle cx="101.3" cy="106.1" r="1.27"/>
</g>
<path d="M154.7 64.2v2.6" fill="none" stroke="#000080" stroke-width=".25"/>
<circle cx="154.7" cy="66.8" r=".51" fill="#000080"/>
<circle cx="154.7" cy="66.8" r=".51" fill="none" stroke="#000080" stroke-width=".21"/>
<path d="M149.6 64.2v5.1" fill="none" stroke="#000080" stroke-width=".25"/>
<circle cx="149.6" cy="69.3" r=".51" fill="#000080"/>
<circle cx="149.6" cy="69.3" r=".51" fill="none" stroke="#000080" stroke-width=".21"/>
<path d="M144.6 64.2v7.6" fill="none" stroke="#000080" stroke-width=".25"/>
<circle cx="144.6" cy="71.8" r=".51" fill="#000080"/>
<circle cx="144.6" cy="71.8" r=".51" fill="none" stroke="#000080" stroke-width=".21"/>
<path d="M149.6 74.4v5.1" fill="none" stroke="#000080" stroke-width=".25"/>
<circle cx="149.6" cy="74.4" r=".51" fill="#000080"/>
<circle cx="149.6" cy="74.4" r=".51" fill="none" stroke="#000080" stroke-width=".21"/>
<path d="M144.6 76.9v2.6" fill="none" stroke="#000080" stroke-width=".25"/>
<circle cx="144.6" cy="76.9" r=".51" fill="#000080"/>
<circle cx="144.6" cy="76.9" r=".51" fill="none" stroke="#000080" stroke-width=".21"/>
<path d="M164.9 96h11.4l1.3 1.2-1.3 1.3h-11.4z" fill-rule="evenodd" fill="#ffff80"/>
<path d="M164.9 96h11.4l1.3 1.2-1.3 1.3h-11.4z" fill="none" stroke="#800000" stroke-width=".21"/>
<path d="M164.9 85.8h11.4l1.3 1.3-1.3 1.2h-11.4z" fill-rule="evenodd" fill="#ffff80"/>
<path d="M164.9 85.8h11.4l1.3 1.3-1.3 1.2h-11.4z" fill="none" stroke="#800000" stroke-width=".21"/>
<path d="M164.9 111.2h11.4l1.3 1.3-1.3 1.2h-11.4z" fill-rule="evenodd" fill="#ffff80"/>
<path d="M164.9 111.2h11.4l1.3 1.3-1.3 1.2h-11.4z" fill="none" stroke="#800000" stroke-width=".21"/>
<path d="M164.9 101h11.4l1.3 1.3-1.3 1.3h-11.4z" fill-rule="evenodd" fill="#ffff80"/>
<path d="M164.9 101h11.4l1.3 1.3-1.3 1.3h-11.4z" fill="none" stroke="#800000" stroke-width=".21"/>
<path d="M164.9 126.4h11.4l1.3 1.3-1.3 1.3h-11.4z" fill-rule="evenodd" fill="#ffff80"/>
<path d="M164.9 126.4h11.4l1.3 1.3-1.3 1.3h-11.4z" fill="none" stroke="#800000" stroke-width=".21"/>
<path d="M164.9 116.3h11.4l1.3 1.2-1.3 1.3h-11.4z" fill-rule="evenodd" fill="#ffff80"/>
<path d="M164.9 116.3h11.4l1.3 1.2-1.3 1.3h-11.4z" fill="none" stroke="#800000" stroke-width=".21"/>
<path d="M164.9 141.7h11.4l1.3 1.2-1.3 1.3h-11.4z" fill-rule="evenodd" fill="#ffff80"/>
<path d="M164.9 141.7h11.4l1.3 1.2-1.3 1.3h-11.4z" fill="none" stroke="#800000" stroke-width=".21"/>
<path d="M164.9 131.5h11.4l1.3 1.3-1.3 1.2h-11.4z" fill-rule="evenodd" fill="#ffff80"/>
<path d="M164.9 131.5h11.4l1.3 1.3-1.3 1.2h-11.4z" fill="none" stroke="#800000" stroke-width=".21"/>
<use href="#words"/>
</svg>
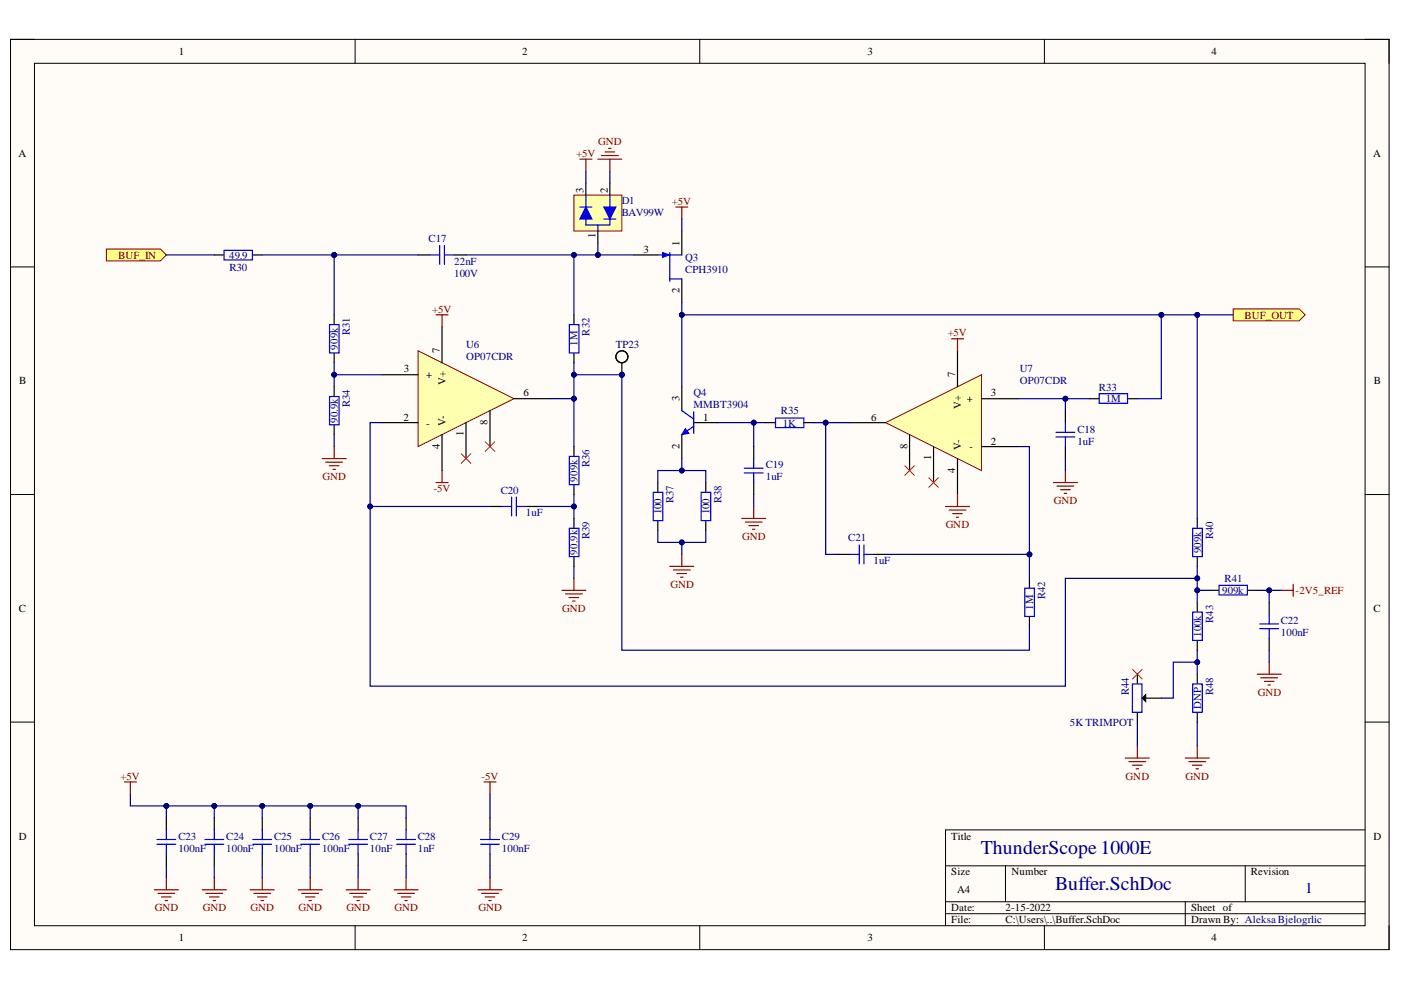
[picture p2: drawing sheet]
<svg xmlns="http://www.w3.org/2000/svg" width="297mm" height="210mm" viewBox="0 0 297 210" stroke-linecap="round" stroke-linejoin="round" font-family="sans-serif">
<defs><g id="words">
<g font-size="4.1" fill="#000080">
<text x="207.9" y="181.1">ThunderScope1000E</text>
<text x="223.7" y="188.8">Buffer.SchDoc</text>
</g>
<text font-size="3.2" fill="#000080" x="276.7" y="189.3">1</text>
<g font-size="2.3">
<text x="37.9" y="11.7">1</text>
<text x="110.7" y="11.7">2</text>
<text x="183.9" y="11.7">3</text>
<text x="256.8" y="11.7">4</text>
<text x="3.9" y="33.3">A</text>
<text x="291.1" y="33.3">A</text>
<text x="123.7" y="40.8" transform="rotate(-90 123.7 40.8)">3</text>
<text x="128.8" y="40.8" transform="rotate(-90 128.8 40.8)">2</text>
<text x="126.2" y="50.4" transform="rotate(-90 126.2 50.4)">1</text>
<text x="136.5" y="53.6">3</text>
<text x="144.1" y="52.1" transform="rotate(-90 144.1 52.1)">1</text>
<text x="144.1" y="62.2" transform="rotate(-90 144.1 62.2)">2</text>
<text x="93.2" y="74.9" transform="rotate(-90 93.2 74.9)">7</text>
<text x="4.1" y="81.5">B</text>
<text x="85.6" y="78.9">3</text>
<text x="90.4" y="80.2">+</text>
<text x="94.5" y="81.6" transform="rotate(-90 94.5 81.6)">V+</text>
<text x="202.5" y="80" transform="rotate(-90 202.5 80)">7</text>
<text x="291.3" y="81.5">B</text>
<text x="85.5" y="89.2">2</text>
<text x="111" y="84">6</text>
<text x="144.1" y="85" transform="rotate(-90 144.1 85)">3</text>
<text x="149.1" y="89.2">1</text>
<text x="184.7" y="89.2">6</text>
<text x="203.8" y="86.6" transform="rotate(-90 203.8 86.6)">V+</text>
<text x="205" y="85.3">+</text>
<text x="210.1" y="84">3</text>
<text x="90.4" y="90.4">-</text>
<text x="93.2" y="95.3" transform="rotate(-90 93.2 95.3)">4</text>
<text x="94.5" y="90.4" transform="rotate(-90 94.5 90.4)">V-</text>
<text x="98.3" y="92.5" transform="rotate(-90 98.3 92.5)">1</text>
<text x="103.4" y="90.1" transform="rotate(-90 103.4 90.1)">8</text>
<text x="144.1" y="95.3" transform="rotate(-90 144.1 95.3)">2</text>
<text x="192.4" y="95.2" transform="rotate(-90 192.4 95.2)">8</text>
<text x="203.8" y="95.4" transform="rotate(-90 203.8 95.4)">V-</text>
<text x="205.6" y="95.5">-</text>
<text x="210.1" y="94.2">2</text>
<text x="197.5" y="97.6" transform="rotate(-90 197.5 97.6)">1</text>
<text x="202.5" y="100.3" transform="rotate(-90 202.5 100.3)">4</text>
<text x="4" y="129.7">C</text>
<text x="291.2" y="129.7">C</text>
<text x="4" y="178">D</text>
<text x="201.7" y="178">Title</text>
<text x="291.2" y="178">D</text>
<text x="201.7" y="185.6">Size</text>
<text x="214.5" y="185.6">Number</text>
<text x="265.2" y="185.6">Revision</text>
<text x="203" y="189.4">A4</text>
<text x="201.7" y="193.2">Date:</text>
<text x="201.7" y="195.8">File:</text>
<text x="213.2" y="193.2">2-15-2022</text>
<text x="213.2" y="195.8">C:\Users\..\Buffer.SchDoc</text>
<text x="252.5" y="193.2">Sheet of</text>
<text x="252.5" y="195.8">Drawn By: Aleksa Bjelogrlic</text>
<text x="37.9" y="199.6">1</text>
<text x="110.7" y="199.6">2</text>
<text x="183.9" y="199.6">3</text>
<text x="256.8" y="199.6">4</text>
</g>
<g font-size="2.3" fill="#800000">
<text x="122.2" y="33.3">+5V</text>
<text x="126.8" y="30.8">GND</text>
<text x="142.5" y="43.4">+5V</text>
<text x="25" y="54.9">BUF_IN</text>
<text x="91.6" y="66.3">+5V</text>
<text x="200.9" y="71.3">+5V</text>
<text x="263.9" y="67.5">BUF_OUT</text>
<text x="68.4" y="101.9">GND</text>
<text x="92" y="104.4">-5V</text>
<text x="223.4" y="106.9">GND</text>
<text x="200.5" y="112">GND</text>
<text x="157.4" y="114.5">GND</text>
<text x="142.1" y="124.7">GND</text>
<text x="274.7" y="125.9">-2V5_REF</text>
<text x="119.2" y="129.7">GND</text>
<text x="266.7" y="147.5">GND</text>
<text x="25.5" y="165.3">+5V</text>
<text x="102.1" y="165.3">-5V</text>
<text x="238.7" y="165.3">GND</text>
<text x="251.3" y="165.3">GND</text>
<text x="32.8" y="193.2">GND</text>
<text x="43" y="193.2">GND</text>
<text x="53.1" y="193.2">GND</text>
<text x="63.3" y="193.2">GND</text>
<text x="73.4" y="193.2">GND</text>
<text x="83.7" y="193.2">GND</text>
<text x="101.4" y="193.2">GND</text>
</g>
<g font-size="2.3" fill="#000080">
<text x="131.8" y="43.2">D1</text>
<text x="131.8" y="45.7">BAV99W</text>
<text x="90.9" y="51.3">C17</text>
<text x="48.6" y="54.9">49.9</text>
<text x="48.6" y="57.4">R30</text>
<text x="96.3" y="58.7">100V</text>
<text x="96.3" y="56.1">22nF</text>
<text x="145.3" y="55.4">Q3</text>
<text x="145.3" y="57.9">CPH3910</text>
<text x="74.2" y="71.1" transform="rotate(-90 74.2 71.1)">R31</text>
<text x="125" y="71.2" transform="rotate(-90 125 71.2)">R32</text>
<text x="71.7" y="74.1" transform="rotate(-90 71.7 74.1)">909k</text>
<text x="98.8" y="73.9">U6</text>
<text x="98.8" y="76.4">OP07CDR</text>
<text x="122.4" y="73.4" transform="rotate(-90 122.4 73.4)">1M</text>
<text x="130.5" y="73.9">TP23</text>
<text x="216.2" y="78.9">U7</text>
<text x="216.2" y="81.5">OP07CDR</text>
<text x="233" y="83">R33</text>
<text x="71.7" y="89.7" transform="rotate(-90 71.7 89.7)">90.9k</text>
<text x="74.2" y="86.4" transform="rotate(-90 74.2 86.4)">R34</text>
<text x="147" y="84">Q4</text>
<text x="147" y="86.6">MMBT3904</text>
<text x="165.6" y="87.8">R35</text>
<text x="234.4" y="85.3">1M</text>
<text x="166" y="90.4">1K</text>
<text x="228.4" y="91.7">C18</text>
<text x="228.4" y="94.2">1uF</text>
<text x="125" y="99.1" transform="rotate(-90 125 99.1)">R36</text>
<text x="162.3" y="99.3">C19</text>
<text x="162.3" y="101.9">1uF</text>
<text x="106.2" y="104.6">C20</text>
<text x="122.4" y="102.1" transform="rotate(-90 122.4 102.1)">909k</text>
<text x="142.8" y="106.7" transform="rotate(-90 142.8 106.7)">R37</text>
<text x="153" y="106.7" transform="rotate(-90 153 106.7)">R38</text>
<text x="111.5" y="109.5">1uF</text>
<text x="140.3" y="109" transform="rotate(-90 140.3 109)">100</text>
<text x="150.4" y="109" transform="rotate(-90 150.4 109)">100</text>
<text x="122.4" y="117.6" transform="rotate(-90 122.4 117.6)">90.9k</text>
<text x="125" y="114.4" transform="rotate(-90 125 114.4)">R39</text>
<text x="179.9" y="114.8">C21</text>
<text x="185.2" y="119.6">1uF</text>
<text x="254.6" y="117.3" transform="rotate(-90 254.6 117.3)">909k</text>
<text x="257.2" y="114.4" transform="rotate(-90 257.2 114.4)">R40</text>
<text x="259.1" y="125.9">909k</text>
<text x="259.6" y="123.4">R41</text>
<text x="219" y="129.2" transform="rotate(-90 219 129.2)">1M</text>
<text x="221.6" y="127" transform="rotate(-90 221.6 127)">R42</text>
<text x="254.6" y="135.1" transform="rotate(-90 254.6 135.1)">100k</text>
<text x="257.2" y="132" transform="rotate(-90 257.2 132)">R43</text>
<text x="271.6" y="132.3">C22</text>
<text x="271.6" y="134.8">100nF</text>
<text x="239.3" y="147.3" transform="rotate(-90 239.3 147.3)">R44</text>
<text x="257.2" y="147.3" transform="rotate(-90 257.2 147.3)">R48</text>
<text x="226.8" y="153.9">5K TRIMPOT</text>
<text x="254.6" y="150.3" transform="rotate(-90 254.6 150.3)">DNP</text>
<text x="37.8" y="178">C23</text>
<text x="48" y="178">C24</text>
<text x="58.1" y="178">C25</text>
<text x="68.3" y="178">C26</text>
<text x="78.4" y="178">C27</text>
<text x="88.6" y="178">C28</text>
<text x="106.4" y="178">C29</text>
<text x="37.8" y="180.6">100nF</text>
<text x="48" y="180.6">100nF</text>
<text x="58.1" y="180.6">100nF</text>
<text x="68.3" y="180.6">100nF</text>
<text x="78.4" y="180.6">10nF</text>
<text x="88.6" y="180.6">1nF</text>
<text x="106.4" y="180.6">100nF</text>
</g>
</g></defs>
<path d="M2.2 8.3h292.3v193h-292.3z" fill-rule="evenodd" fill="#fffcf8"/>
<path d="M2.2 8.3h292.3v193h-292.3z" fill="none" stroke="#000" stroke-width=".21"/>
<path d="M7.3 13.4h282.1v182.9h-282.1z" fill-rule="evenodd" fill="#fffcf8"/>
<g fill="none" stroke="#000" stroke-width=".21">
<path d="M2.2 8.3h5.1M7.3 13.4h282.1v182.9h-282.1zM75.3 8.3v5.1M148.4 8.3v5.1M221.4 8.3v5.1M289.4 8.3h5.1v5.1M2.2 56.6h5.1M289.4 56.6h5.1M2.2 104.8h5.1M289.4 104.9h5.1M2.2 153.1h5.1M289.4 153.1h5.1"/>
<path d="M289.4 176h-88.9v20.3M75.3 196.3v5M148.4 196.3v5M200.5 183.6h88.9M200.5 191.2h88.9M200.5 193.7h88.9M213.2 183.6v7.6M221.4 196.3v5M251.3 191.2v5.1M264 183.6v7.6M294.5 196.3v5"/>
</g>
<path d="M68.3 97.2h5.1M69.1 98h3.5M69.8 98.8h2.1M70.6 99.5h.5M70.8 94.7v2.5" fill="none" stroke="#800000" stroke-width=".25"/>
<path d="M88.6 74.4l20.4 10.1-20.4 10.2z" fill="#ffffb0"/>
<path d="M88.6 74.4l20.4 10.1-20.4 10.2z" fill="none" stroke="#800000" stroke-width=".21"/>
<path d="M81 79.5h7.6M93.7 69.3v7.6M81 89.6h7.6M93.7 92.1v7.7M98.8 89.6v7.6M103.9 87.1v7.6M109 84.5h7.6" fill="none" stroke="#000" stroke-width=".25"/>
<path d="M92.5 66.8h2.5M93.7 66.8v2.5M93.7 99.8v2.5M92.5 102.3h2.5M119.1 125.2h5.1M119.9 125.9h3.6M120.7 126.7h2M121.4 127.5h.5M121.7 122.6v2.6" fill="none" stroke="#800000" stroke-width=".25"/>
<path d="M97.8 96.2l2 2M99.8 96.2l-2 2M102.9 93.7l2 2M104.9 93.7l-2 2" fill="none" stroke="#f00" stroke-width=".21"/>
<path d="M22.6 52.8h11.4l1.3 1.3-1.3 1.2h-11.4z" fill-rule="evenodd" fill="#ffff80"/>
<path d="M22.6 52.8h11.4l1.3 1.3-1.3 1.2h-11.4z" fill="none" stroke="#800000" stroke-width=".21"/>
<path d="M121.7 66.8v2M121.7 74.9v2M144.6 82v5.1M144.6 92.1v5.1M147.1 89.6h5.1M103.9 107.4h2.5M111.5 107.4h2.6" fill="none" stroke="#000" stroke-width=".25"/>
<path d="M120.7 68.8h2v6h-2zM144.6 87.1l2.5 1.7M147.1 90.4l-2.5 1.7M147.1 87.3v4.6M106.4 107.4h2.1M108.5 105.4v4M109.5 107.4h2M109.5 105.4v4" fill="none" stroke="#00f" stroke-width=".25"/>
<path d="M143.3 43.9h2.5M144.6 43.9v2.5" fill="none" stroke="#800000" stroke-width=".25"/>
<path d="M145.3 90.9l.8 1-1.5 .2z" fill="#00f"/>
<path d="M145.3 90.9l.8 1-1.5 .2z" fill="none" stroke="#00f" stroke-width=".21"/>
<path d="M139.5 102.3v2M139.5 110.5v2M149.6 102.3v2M149.6 110.5v2" fill="none" stroke="#000" stroke-width=".25"/>
<path d="M138.5 104.4h2v6h-2zM148.7 104.4h2v6h-2z" fill="none" stroke="#00f" stroke-width=".25"/>
<path d="M144.6 117.5v2.6M142 120.1h5.1M142.8 120.8h3.5M143.5 121.6h2.1M144.3 122.4h.5" fill="none" stroke="#800000" stroke-width=".25"/>
<path d="M187.8 89.6l20.3-10.1v20.3z" fill="#ffffb0"/>
<path d="M187.8 89.6l20.3-10.1v20.3z" fill="none" stroke="#800000" stroke-width=".21"/>
<path d="M203 74.4v7.6M180.1 89.6h7.7M192.8 92.2v7.6M197.9 94.7v7.6M203 97.2v7.7M208.1 84.5h7.6M208.1 94.7h7.6M231 84.5h2M239.1 84.5h2M218.3 122.6v2M218.3 130.8v2" fill="none" stroke="#000" stroke-width=".25"/>
<path d="M201.7 71.8h2.6M203 71.8v2.6M225.9 99.8v2.5M157.3 109.9h5M158 110.7h3.6M158.8 111.4h2M159.5 112.2h.6M159.8 107.4v2.5M223.3 102.3h5.1M224.1 103.1h3.6M224.9 103.8h2M225.6 104.6h.5" fill="none" stroke="#800000" stroke-width=".25"/>
<path d="M191.8 98.8l2.1 2M193.9 98.8l-2.1 2M196.9 101.3l2 2M198.9 101.3l-2 2" fill="none" stroke="#f00" stroke-width=".21"/>
<path d="M233.1 83.5h6v2h-6zM217.3 124.7h2v6h-2z" fill="none" stroke="#00f" stroke-width=".25"/>
<path d="M261.5 65.5h13.9l1.3 1.3-1.3 1.2h-13.9z" fill-rule="evenodd" fill="#ffff80"/>
<path d="M261.5 65.5h13.9l1.3 1.3-1.3 1.2h-13.9z" fill="none" stroke="#800000" stroke-width=".21"/>
<g fill="none" stroke="#000" stroke-width=".25">
<path d="M134.4 54.1h5.1M144.6 49v5.1M144.6 59.1v5.1M225.9 87.1v2.5M225.9 94.7v2.5M177.6 117.5h2.5M185.2 117.5h2.6M45.4 173.4v2.6M55.6 173.4v2.6M65.8 173.4v2.6M75.9 173.4v2.6M86.1 173.4v2.6"/>
<path d="M103.9 173.4v2.6M45.4 181v2.6M55.6 181v2.6M65.8 181v2.6M75.9 181v2.6M86.1 181v2.6M103.9 181v2.6"/>
</g>
<g fill="none" stroke="#00f" stroke-width=".25">
<path d="M139.5 54.1h2.5M142 53.5v6.1M223.9 92.6h4M223.9 91.7h4M225.9 89.6v2.1M225.9 92.6v2.1M180.1 117.5h2.1M182.2 115.5v4.1M183.2 117.5h2M183.2 115.5v4.1M43.4 178h4M43.4 179h4"/>
<path d="M45.4 176v2M45.4 179v2M53.6 178h4M53.6 179h4M55.6 176v2M55.6 179v2M63.8 178h4M63.8 179h4M65.8 176v2M65.8 179v2M73.9 178h4M73.9 179h4"/>
<path d="M75.9 176v2M75.9 179v2M84.1 178h4M84.1 179h4M86.1 176v2M86.1 179v2M101.9 178h4M101.9 179h4M103.9 176v2M103.9 179v2"/>
</g>
<g fill="none" stroke="#800000" stroke-width=".25">
<path d="M200.5 107.4h5.1M201.2 108.2h3.6M202 108.9h2M202.8 109.7h.5M203 104.9v2.5M26.4 165.8h2.5M27.6 165.8v2.5M102.6 165.8h2.6M103.9 165.8v2.5M42.9 188.7h5.1M43.7 189.4h3.5M44.4 190.2h2.1"/>
<path d="M45.2 190.9h.5M45.4 186.1v2.6M53.1 188.7h5M53.8 189.4h3.6M54.6 190.2h2M55.3 190.9h.6M55.6 186.1v2.6M63.2 188.7h5.1M64 189.4h3.5M64.8 190.2h2M65.5 190.9h.5M65.8 186.1v2.6"/>
<path d="M73.4 188.7h5.1M74.2 189.4h3.5M74.9 190.2h2.1M75.7 190.9h.5M75.9 186.1v2.6M83.6 188.7h5M84.3 189.4h3.6M85.1 190.2h2M85.8 190.9h.6M86.1 186.1v2.6M101.4 188.7h5M102.1 189.4h3.6"/>
<path d="M102.9 190.2h2M103.6 190.9h.5M103.9 186.1v2.6"/>
</g>
<path d="M140.5 53.5l1.5 .6-1.5 .5z" fill="#00f"/>
<path d="M140.5 53.5l1.5 .6-1.5 .5z" fill="none" stroke="#00f" stroke-width=".21"/>
<g fill="none" stroke="#00f" stroke-width=".25">
<path d="M91.2 54.1h2M93.2 52.1v4M94.2 54.1h2.1M94.2 52.1v4M142 59.1h2.6M142 54.1h2.6M69.9 68.8h2v6h-2zM69.9 84.1h2v6h-2zM120.7 96.8h2v6h-2zM157.8 99.3h4M159.8 97.2v2.1M164.4 88.6h6v2.1h-6z"/>
<path d="M120.7 112h2v6h-2zM157.8 100.3h4M159.8 100.3v2M252.9 112h2v6h-2zM252.9 129.8h2v6h-2zM258.5 124.1h6v2h-6z"/>
</g>
<g fill="none" stroke="#000" stroke-width=".25">
<path d="M88.6 54.1h2.6M96.3 54.1h2.5M70.8 66.8v2M70.8 74.9v2M70.8 82v2M70.8 90.2v1.9M121.7 94.7v2M159.8 94.7v2.5M162.3 89.6h2M170.5 89.6h2M121.7 102.8v2M121.7 109.9v2"/>
<path d="M121.7 118.1v2M159.8 102.3v2.5M253.8 109.9v2M253.8 118.1v2M253.8 127.7v2M253.8 135.9v2M256.4 125.2h2M264.6 125.2h2"/>
</g>
<path d="M271.6 125.2h2.6M274.2 123.9v2.5" fill="none" stroke="#800000" stroke-width=".25"/>
<path d="M121.7 41.4h10.1v7.6h-10.1z" fill-rule="evenodd" fill="#ffffb0"/>
<path d="M121.7 41.4h10.1v7.6h-10.1z" fill="none" stroke="#800000" stroke-width=".21"/>
<path d="M122.9 43.9h2.6" fill="none" stroke="#00f" stroke-width=".25"/>
<path d="M124.2 43.9l1.3 2.5h-2.6z" fill="#00f"/>
<path d="M124.2 43.9l1.3 2.5h-2.6zM128 46.4h2.6" fill="none" stroke="#00f" stroke-width=".25"/>
<path d="M128 43.9h2.6l-1.3 2.5z" fill="#00f"/>
<g fill="none" stroke="#00f" stroke-width=".25">
<path d="M47.5 53.1h6v2h-6zM124.2 46.4v1.3h5.1v-1.3M124.2 41.4v2.5M126.8 47.7v1.3M128 43.9h2.6l-1.3 2.5zM129.3 41.4v2.5M267.1 132.3h4M267.1 133.3h4M269.1 130.2v2.1M269.1 133.3v2M33.3 178h4M33.3 179h4"/>
<path d="M35.3 176v2M35.3 179v2"/>
</g>
<path d="M124.2 38.8v2.6M129.3 38.8v2.6M45.4 54.1h2M53.6 54.1h2M126.8 49v2.5M269.1 127.7v2.5M269.1 135.3v2.6M35.3 173.4v2.6M35.3 181v2.6" fill="none" stroke="#000" stroke-width=".25"/>
<g fill="none" stroke="#800000" stroke-width=".25">
<path d="M122.9 33.7h2.6M124.2 33.7v2.6M126.8 33.7h5M127.5 33h3.6M128.3 32.2h2M129.1 31.5h.5M129.3 33.7v2.6M266.6 142.9h5M267.3 143.7h3.6M268.1 144.5h2M268.8 145.2h.5M269.1 140.4v2.5"/>
<path d="M32.7 188.7h5.1M33.5 189.4h3.5M34.3 190.2h2M35 190.9h.5M35.3 186.1v2.6"/>
</g>
<circle cx="131.8" cy="79.5" r=".51" fill="#000080"/>
<circle cx="131.8" cy="79.5" r=".51" fill="none" stroke="#000080" stroke-width=".21"/>
<path d="M131.8 76.9v2.6" fill="none" stroke="#000" stroke-width=".25"/>
<circle cx="131.8" cy="79.5" r=".51" fill="#000080"/>
<circle cx="131.8" cy="79.5" r=".51" fill="none" stroke="#000080" stroke-width=".21"/>
<g fill="none" stroke="#000" stroke-width=".25">
<path d="M241.1 142.9v2M241.1 151.1v2M242.2 148h4M253.8 142.9v2M253.8 151.1v2"/>
<circle cx="131.8" cy="75.6" r="1.27"/>
</g>
<path d="M240.1 145h2v6h-2zM252.9 145h2v6h-2z" fill="none" stroke="#00f" stroke-width=".25"/>
<path d="M241.1 158.2v2.5M253.8 158.2v2.5M238.6 160.7h5.1M239.4 161.5h3.5M240.1 162.2h2.1M240.9 163h.5M251.3 160.7h5.1M252.1 161.5h3.5M252.8 162.2h2.1M253.6 163h.5" fill="none" stroke="#800000" stroke-width=".25"/>
<path d="M242.2 148l.7-.7v1.5z" fill="#000"/>
<path d="M242.2 148l.7-.7v1.5z" fill="none" stroke="#000" stroke-width=".21"/>
<path d="M240.1 141.9l2.1 2.1M242.2 141.9l-2.1 2.1" fill="none" stroke="#f00" stroke-width=".21"/>
<path d="M269.1 125.2v2.5" fill="none" stroke="#000080" stroke-width=".25"/>
<circle cx="269.1" cy="125.2" r=".51" fill="#000080"/>
<circle cx="269.1" cy="125.2" r=".51" fill="none" stroke="#000080" stroke-width=".21"/>
<path d="M27.6 168.3v2.6h17.8v2.5" fill="none" stroke="#000080" stroke-width=".25"/>
<circle cx="35.3" cy="170.9" r=".51" fill="#000080"/>
<circle cx="35.3" cy="170.9" r=".51" fill="none" stroke="#000080" stroke-width=".21"/>
<circle cx="45.4" cy="170.9" r=".51" fill="#000080"/>
<circle cx="45.4" cy="170.9" r=".51" fill="none" stroke="#000080" stroke-width=".21"/>
<path d="M35.3 54.1h10.1M55.6 54.1h15.2" fill="none" stroke="#000080" stroke-width=".25"/>
<circle cx="70.8" cy="54.1" r=".51" fill="#000080"/>
<circle cx="70.8" cy="54.1" r=".51" fill="none" stroke="#000080" stroke-width=".21"/>
<path d="M81 79.5h-10.2v2.5" fill="none" stroke="#000080" stroke-width=".25"/>
<circle cx="70.8" cy="79.5" r=".51" fill="#000080"/>
<circle cx="70.8" cy="79.5" r=".51" fill="none" stroke="#000080" stroke-width=".21"/>
<path d="M70.8 54.1h17.8" fill="none" stroke="#000080" stroke-width=".25"/>
<circle cx="70.8" cy="54.1" r=".51" fill="#000080"/>
<circle cx="70.8" cy="54.1" r=".51" fill="none" stroke="#000080" stroke-width=".21"/>
<path d="M78.5 107.4v38.1h147.4v-22.9h27.9" fill="none" stroke="#000080" stroke-width=".25"/>
<circle cx="253.8" cy="122.6" r=".51" fill="#000080"/>
<circle cx="253.8" cy="122.6" r=".51" fill="none" stroke="#000080" stroke-width=".21"/>
<circle cx="78.5" cy="107.4" r=".51" fill="#000080"/>
<circle cx="78.5" cy="107.4" r=".51" fill="none" stroke="#000080" stroke-width=".21"/>
<path d="M81 89.6h-2.5v17.8h25.4" fill="none" stroke="#000080" stroke-width=".25"/>
<circle cx="78.5" cy="107.4" r=".51" fill="#000080"/>
<circle cx="78.5" cy="107.4" r=".51" fill="none" stroke="#000080" stroke-width=".21"/>
<path d="M98.8 54.1h35.6" fill="none" stroke="#000080" stroke-width=".25"/>
<circle cx="121.7" cy="54.1" r=".51" fill="#000080"/>
<circle cx="121.7" cy="54.1" r=".51" fill="none" stroke="#000080" stroke-width=".21"/>
<circle cx="126.8" cy="54.1" r=".51" fill="#000080"/>
<circle cx="126.8" cy="54.1" r=".51" fill="none" stroke="#000080" stroke-width=".21"/>
<path d="M121.7 104.8v2.6h-7.6" fill="none" stroke="#000080" stroke-width=".25"/>
<circle cx="121.7" cy="107.4" r=".51" fill="#000080"/>
<circle cx="121.7" cy="107.4" r=".51" fill="none" stroke="#000080" stroke-width=".21"/>
<path d="M116.6 84.5h5.1v10.2" fill="none" stroke="#000080" stroke-width=".25"/>
<circle cx="121.7" cy="84.5" r=".51" fill="#000080"/>
<circle cx="121.7" cy="84.5" r=".51" fill="none" stroke="#000080" stroke-width=".21"/>
<path d="M121.7 79.5h10.1v58.4h86.5v-5.1" fill="none" stroke="#000080" stroke-width=".25"/>
<circle cx="131.8" cy="79.5" r=".51" fill="#000080"/>
<circle cx="131.8" cy="79.5" r=".51" fill="none" stroke="#000080" stroke-width=".21"/>
<circle cx="121.7" cy="79.5" r=".51" fill="#000080"/>
<circle cx="121.7" cy="79.5" r=".51" fill="none" stroke="#000080" stroke-width=".21"/>
<path d="M139.5 112.5v2.5h5.1v2.5" fill="none" stroke="#000080" stroke-width=".25"/>
<circle cx="144.6" cy="115" r=".51" fill="#000080"/>
<circle cx="144.6" cy="115" r=".51" fill="none" stroke="#000080" stroke-width=".21"/>
<path d="M144.6 97.2v2.6h-5.1v2.5" fill="none" stroke="#000080" stroke-width=".25"/>
<circle cx="144.6" cy="99.8" r=".51" fill="#000080"/>
<circle cx="144.6" cy="99.8" r=".51" fill="none" stroke="#000080" stroke-width=".21"/>
<path d="M149.6 112.5v2.5h-5" fill="none" stroke="#000080" stroke-width=".25"/>
<circle cx="144.6" cy="115" r=".51" fill="#000080"/>
<circle cx="144.6" cy="115" r=".51" fill="none" stroke="#000080" stroke-width=".21"/>
<path d="M144.6 99.8h5v2.5" fill="none" stroke="#000080" stroke-width=".25"/>
<circle cx="144.6" cy="99.8" r=".51" fill="#000080"/>
<circle cx="144.6" cy="99.8" r=".51" fill="none" stroke="#000080" stroke-width=".21"/>
<path d="M144.6 66.8h116.9" fill="none" stroke="#000080" stroke-width=".25"/>
<circle cx="144.6" cy="66.8" r=".51" fill="#000080"/>
<circle cx="144.6" cy="66.8" r=".51" fill="none" stroke="#000080" stroke-width=".21"/>
<circle cx="246.2" cy="66.8" r=".51" fill="#000080"/>
<circle cx="246.2" cy="66.8" r=".51" fill="none" stroke="#000080" stroke-width=".21"/>
<circle cx="253.8" cy="66.8" r=".51" fill="#000080"/>
<circle cx="253.8" cy="66.8" r=".51" fill="none" stroke="#000080" stroke-width=".21"/>
<path d="M152.2 89.6h7.6v5.1" fill="none" stroke="#000080" stroke-width=".25"/>
<circle cx="159.8" cy="89.6" r=".51" fill="#000080"/>
<circle cx="159.8" cy="89.6" r=".51" fill="none" stroke="#000080" stroke-width=".21"/>
<path d="M159.8 89.6h2.5" fill="none" stroke="#000080" stroke-width=".25"/>
<circle cx="159.8" cy="89.6" r=".51" fill="#000080"/>
<circle cx="159.8" cy="89.6" r=".51" fill="none" stroke="#000080" stroke-width=".21"/>
<path d="M172.5 89.6h7.6" fill="none" stroke="#000080" stroke-width=".25"/>
<circle cx="175.1" cy="89.6" r=".51" fill="#000080"/>
<circle cx="175.1" cy="89.6" r=".51" fill="none" stroke="#000080" stroke-width=".21"/>
<path d="M175.1 89.6v27.9h2.5" fill="none" stroke="#000080" stroke-width=".25"/>
<circle cx="175.1" cy="89.6" r=".51" fill="#000080"/>
<circle cx="175.1" cy="89.6" r=".51" fill="none" stroke="#000080" stroke-width=".21"/>
<path d="M187.8 117.5h30.5" fill="none" stroke="#000080" stroke-width=".25"/>
<circle cx="218.3" cy="117.5" r=".51" fill="#000080"/>
<circle cx="218.3" cy="117.5" r=".51" fill="none" stroke="#000080" stroke-width=".21"/>
<path d="M215.7 94.7h2.6v27.9" fill="none" stroke="#000080" stroke-width=".25"/>
<circle cx="218.3" cy="117.5" r=".51" fill="#000080"/>
<circle cx="218.3" cy="117.5" r=".51" fill="none" stroke="#000080" stroke-width=".21"/>
<path d="M215.7 84.5h10.2v2.6" fill="none" stroke="#000080" stroke-width=".25"/>
<circle cx="225.9" cy="84.5" r=".51" fill="#000080"/>
<circle cx="225.9" cy="84.5" r=".51" fill="none" stroke="#000080" stroke-width=".21"/>
<path d="M225.9 84.5h5.1" fill="none" stroke="#000080" stroke-width=".25"/>
<circle cx="225.9" cy="84.5" r=".51" fill="#000080"/>
<circle cx="225.9" cy="84.5" r=".51" fill="none" stroke="#000080" stroke-width=".21"/>
<path d="M246.2 66.8v17.7h-5.1" fill="none" stroke="#000080" stroke-width=".25"/>
<circle cx="246.2" cy="66.8" r=".51" fill="#000080"/>
<circle cx="246.2" cy="66.8" r=".51" fill="none" stroke="#000080" stroke-width=".21"/>
<path d="M253.8 125.2h2.6" fill="none" stroke="#000080" stroke-width=".25"/>
<circle cx="253.8" cy="125.2" r=".51" fill="#000080"/>
<circle cx="253.8" cy="125.2" r=".51" fill="none" stroke="#000080" stroke-width=".21"/>
<path d="M266.6 125.2h5" fill="none" stroke="#000080" stroke-width=".25"/>
<circle cx="269.1" cy="125.2" r=".51" fill="#000080"/>
<circle cx="269.1" cy="125.2" r=".51" fill="none" stroke="#000080" stroke-width=".21"/>
<path d="M35.3 170.9v2.5M35.3 183.6v2.5" fill="none" stroke="#000080" stroke-width=".25"/>
<circle cx="35.3" cy="170.9" r=".51" fill="#000080"/>
<circle cx="35.3" cy="170.9" r=".51" fill="none" stroke="#000080" stroke-width=".21"/>
<path d="M55.6 170.9v2.5M45.4 183.6v2.5M55.6 183.6v2.5" fill="none" stroke="#000080" stroke-width=".25"/>
<circle cx="55.6" cy="170.9" r=".51" fill="#000080"/>
<circle cx="55.6" cy="170.9" r=".51" fill="none" stroke="#000080" stroke-width=".21"/>
<path d="M65.8 170.9v2.5M65.8 183.6v2.5" fill="none" stroke="#000080" stroke-width=".25"/>
<circle cx="65.8" cy="170.9" r=".51" fill="#000080"/>
<circle cx="65.8" cy="170.9" r=".51" fill="none" stroke="#000080" stroke-width=".21"/>
<path d="M70.8 76.9v2.6M70.8 92.1v2.6" fill="none" stroke="#000080" stroke-width=".25"/>
<circle cx="70.8" cy="79.5" r=".51" fill="#000080"/>
<circle cx="70.8" cy="79.5" r=".51" fill="none" stroke="#000080" stroke-width=".21"/>
<path d="M70.8 54.1v12.7" fill="none" stroke="#000080" stroke-width=".25"/>
<circle cx="70.8" cy="54.1" r=".51" fill="#000080"/>
<circle cx="70.8" cy="54.1" r=".51" fill="none" stroke="#000080" stroke-width=".21"/>
<path d="M75.9 170.9v2.5M75.9 183.6v2.5" fill="none" stroke="#000080" stroke-width=".25"/>
<circle cx="75.9" cy="170.9" r=".51" fill="#000080"/>
<circle cx="75.9" cy="170.9" r=".51" fill="none" stroke="#000080" stroke-width=".21"/>
<path d="M121.7 107.4v2.5M121.7 120.1v2.5M103.9 168.3v5.1M86.1 183.6v2.5M103.9 183.6v2.5" fill="none" stroke="#000080" stroke-width=".25"/>
<circle cx="121.7" cy="107.4" r=".51" fill="#000080"/>
<circle cx="121.7" cy="107.4" r=".51" fill="none" stroke="#000080" stroke-width=".21"/>
<path d="M121.7 76.9v7.6" fill="none" stroke="#000080" stroke-width=".25"/>
<circle cx="121.7" cy="79.5" r=".51" fill="#000080"/>
<circle cx="121.7" cy="79.5" r=".51" fill="none" stroke="#000080" stroke-width=".21"/>
<circle cx="121.7" cy="84.5" r=".51" fill="#000080"/>
<circle cx="121.7" cy="84.5" r=".51" fill="none" stroke="#000080" stroke-width=".21"/>
<path d="M121.7 54.1v12.7" fill="none" stroke="#000080" stroke-width=".25"/>
<circle cx="121.7" cy="54.1" r=".51" fill="#000080"/>
<circle cx="121.7" cy="54.1" r=".51" fill="none" stroke="#000080" stroke-width=".21"/>
<path d="M124.2 36.3v2.5M126.8 51.5v2.6" fill="none" stroke="#000080" stroke-width=".25"/>
<circle cx="126.8" cy="54.1" r=".51" fill="#000080"/>
<circle cx="126.8" cy="54.1" r=".51" fill="none" stroke="#000080" stroke-width=".21"/>
<path d="M129.3 36.3v2.5M144.6 64.2v17.8" fill="none" stroke="#000080" stroke-width=".25"/>
<circle cx="144.6" cy="66.8" r=".51" fill="#000080"/>
<circle cx="144.6" cy="66.8" r=".51" fill="none" stroke="#000080" stroke-width=".21"/>
<path d="M144.6 46.4v2.6M253.8 66.8v43.1M225.9 97.2v2.6M159.8 104.8v2.6" fill="none" stroke="#000080" stroke-width=".25"/>
<circle cx="253.8" cy="66.8" r=".51" fill="#000080"/>
<circle cx="253.8" cy="66.8" r=".51" fill="none" stroke="#000080" stroke-width=".21"/>
<path d="M269.1 137.9v2.5M45.4 170.9h40.7v2.5" fill="none" stroke="#000080" stroke-width=".25"/>
<circle cx="45.4" cy="170.9" r=".51" fill="#000080"/>
<circle cx="45.4" cy="170.9" r=".51" fill="none" stroke="#000080" stroke-width=".21"/>
<circle cx="55.6" cy="170.9" r=".51" fill="#000080"/>
<circle cx="55.6" cy="170.9" r=".51" fill="none" stroke="#000080" stroke-width=".21"/>
<circle cx="65.8" cy="170.9" r=".51" fill="#000080"/>
<circle cx="65.8" cy="170.9" r=".51" fill="none" stroke="#000080" stroke-width=".21"/>
<circle cx="75.9" cy="170.9" r=".51" fill="#000080"/>
<circle cx="75.9" cy="170.9" r=".51" fill="none" stroke="#000080" stroke-width=".21"/>
<path d="M253.8 137.9v5M241.1 153.1v5.1M253.8 153.1v5.1" fill="none" stroke="#000080" stroke-width=".25"/>
<circle cx="253.8" cy="140.4" r=".51" fill="#000080"/>
<circle cx="253.8" cy="140.4" r=".51" fill="none" stroke="#000080" stroke-width=".21"/>
<path d="M253.8 120.1v7.6" fill="none" stroke="#000080" stroke-width=".25"/>
<circle cx="253.8" cy="122.6" r=".51" fill="#000080"/>
<circle cx="253.8" cy="122.6" r=".51" fill="none" stroke="#000080" stroke-width=".21"/>
<circle cx="253.8" cy="125.2" r=".51" fill="#000080"/>
<circle cx="253.8" cy="125.2" r=".51" fill="none" stroke="#000080" stroke-width=".21"/>
<path d="M253.8 140.4h-5v7.6h-2.6" fill="none" stroke="#000080" stroke-width=".25"/>
<circle cx="253.8" cy="140.4" r=".51" fill="#000080"/>
<circle cx="253.8" cy="140.4" r=".51" fill="none" stroke="#000080" stroke-width=".21"/>
<use href="#words"/>
</svg>
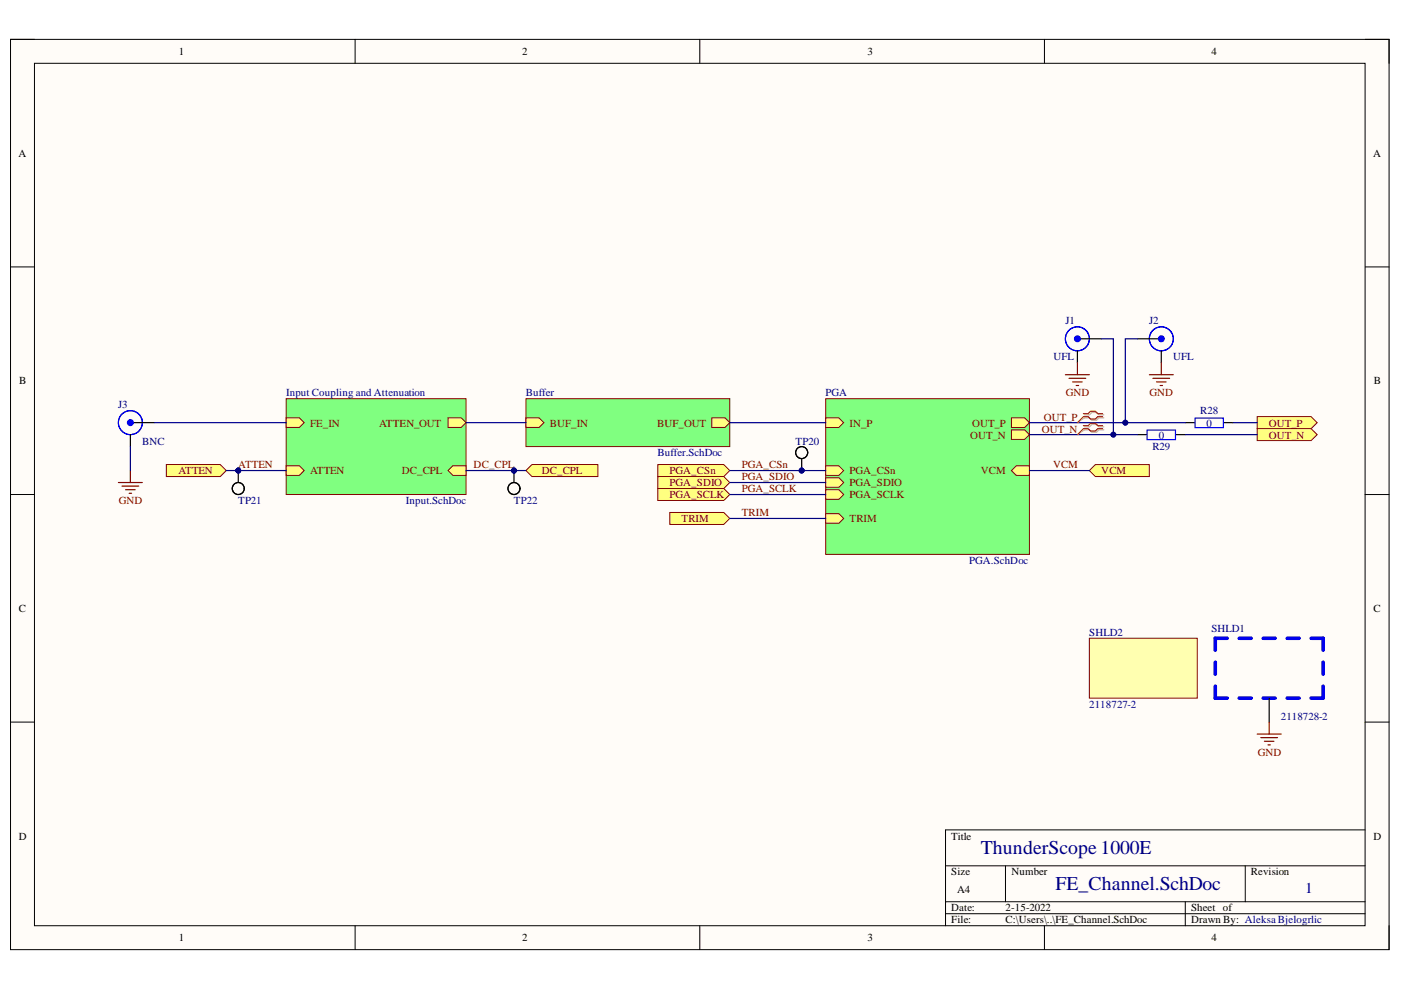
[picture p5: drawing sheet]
<svg xmlns="http://www.w3.org/2000/svg" width="297mm" height="210mm" viewBox="0 0 297 210" stroke-linecap="round" stroke-linejoin="round" font-family="sans-serif">
<defs><g id="words">
<g font-size="4.1" fill="#000080">
<text x="207.9" y="181.1">ThunderScope1000E</text>
<text x="223.8" y="188.8">FE_Channel.SchDoc</text>
</g>
<text font-size="3.2" fill="#000080" x="276.7" y="189.3">1</text>
<g font-size="2.3">
<text x="37.9" y="11.7">1</text>
<text x="110.7" y="11.7">2</text>
<text x="183.9" y="11.7">3</text>
<text x="256.8" y="11.7">4</text>
<text x="3.9" y="33.3">A</text>
<text x="291.1" y="33.3">A</text>
<text x="4.1" y="81.5">B</text>
<text x="291.3" y="81.5">B</text>
<text x="4" y="129.7">C</text>
<text x="291.2" y="129.7">C</text>
<text x="4" y="178">D</text>
<text x="201.7" y="178">Title</text>
<text x="291.2" y="178">D</text>
<text x="201.7" y="185.6">Size</text>
<text x="214.5" y="185.6">Number</text>
<text x="265.2" y="185.6">Revision</text>
<text x="203" y="189.4">A4</text>
<text x="201.7" y="193.2">Date:</text>
<text x="201.7" y="195.8">File:</text>
<text x="213.2" y="193.2">2-15-2022</text>
<text x="213.2" y="195.8">C:\Users\..\FE_Channel.SchDoc</text>
<text x="252.5" y="193.2">Sheet of</text>
<text x="252.5" y="195.8">Drawn By: Aleksa Bjelogrlic</text>
<text x="37.9" y="199.6">1</text>
<text x="110.7" y="199.6">2</text>
<text x="183.9" y="199.6">3</text>
<text x="256.8" y="199.6">4</text>
</g>
<g font-size="2.3" fill="#000080">
<text x="225.9" y="68.8">J1</text>
<text x="243.6" y="68.8">J2</text>
<text x="223.3" y="76.4">UFL</text>
<text x="248.7" y="76.4">UFL</text>
<text x="25" y="86.6">J3</text>
<text x="60.7" y="84">Input Coupling and Attenuation</text>
<text x="111.5" y="84">Buffer</text>
<text x="175" y="84">PGA</text>
<text x="254.5" y="87.8">R28</text>
<text x="30.1" y="94.2">BNC</text>
<text x="168.7" y="94.2">TP20</text>
<text x="244.3" y="95.5">R29</text>
<text x="245.7" y="93">0</text>
<text x="255.8" y="90.4">0</text>
<text x="139.4" y="96.8">Buffer.SchDoc</text>
<text x="50.5" y="106.9">TP21</text>
<text x="86" y="106.9">Input.SchDoc</text>
<text x="109" y="106.9">TP22</text>
<text x="205.5" y="119.6">PGA.SchDoc</text>
<text x="231" y="134.8">SHLD2</text>
<text x="256.8" y="134.1">SHLD1</text>
<text x="231" y="150.1">2118727-2</text>
<text x="271.6" y="152.7">2118728-2</text>
</g>
<g font-size="2.3" fill="#800000">
<text x="221.3" y="89.2">OUT_P</text>
<text x="226" y="84">GND</text>
<text x="243.7" y="84">GND</text>
<text x="65.7" y="90.4">FE_IN</text>
<text x="80.4" y="90.4">ATTEN_OUT</text>
<text x="116.6" y="90.4">BUF_IN</text>
<text x="139.3" y="90.4">BUF_OUT</text>
<text x="180.1" y="90.4">IN_P</text>
<text x="205.7" y="93">OUT_N</text>
<text x="206.1" y="90.4">OUT_P</text>
<text x="220.9" y="91.7">OUT_N</text>
<text x="269" y="90.4">OUT_P</text>
<text x="269" y="93">OUT_N</text>
<text x="37.8" y="100.6">ATTEN</text>
<text x="50.5" y="99.3">ATTEN</text>
<text x="65.7" y="100.6">ATTEN</text>
<text x="85.2" y="100.6">DC_CPL</text>
<text x="100.4" y="99.3">DC_CPL</text>
<text x="114.9" y="100.6">DC_CPL</text>
<text x="142" y="100.6">PGA_CSn</text>
<text x="157.3" y="99.3">PGA_CSn</text>
<text x="157.3" y="101.9">PGA_SDIO</text>
<text x="180.1" y="100.6">PGA_CSn</text>
<text x="207.9" y="100.6">VCM</text>
<text x="223.3" y="99.3">VCM</text>
<text x="233.5" y="100.6">VCM</text>
<text x="25.2" y="106.9">GND</text>
<text x="142" y="105.7">PGA_SCLK</text>
<text x="142" y="103.1">PGA_SDIO</text>
<text x="157.3" y="104.4">PGA_SCLK</text>
<text x="180.1" y="103.1">PGA_SDIO</text>
<text x="180.1" y="105.7">PGA_SCLK</text>
<text x="144.5" y="110.7">TRIM</text>
<text x="157.3" y="109.5">TRIM</text>
<text x="180.1" y="110.7">TRIM</text>
<text x="266.7" y="160.3">GND</text>
</g>
</g></defs>
<path d="M2.2 8.3h292.3v193h-292.3z" fill-rule="evenodd" fill="#fffcf8"/>
<path d="M2.2 8.3h292.3v193h-292.3z" fill="none" stroke="#000" stroke-width=".21"/>
<path d="M7.3 13.4h282.1v182.9h-282.1z" fill-rule="evenodd" fill="#fffcf8"/>
<g fill="none" stroke="#000" stroke-width=".21">
<path d="M2.2 8.3h5.1M7.3 13.4h282.1v182.9h-282.1zM75.3 8.3v5.1M148.4 8.3v5.1M221.4 8.3v5.1M289.4 8.3h5.1v5.1M2.2 56.6h5.1M289.4 56.6h5.1M2.2 104.8h5.1M289.4 104.9h5.1M2.2 153.1h5.1M289.4 153.1h5.1"/>
<path d="M289.4 176h-88.9v20.3M75.3 196.3v5M148.4 196.3v5M200.5 183.6h88.9M200.5 191.2h88.9M200.5 193.7h88.9M213.2 183.6v7.6M221.4 196.3v5M251.3 191.2v5.1M264 183.6v7.6M294.5 196.3v5"/>
</g>
<path d="M27.6 99.8v2.5M25.1 102.3h5.1M25.9 103.1h3.5M26.6 103.8h2.1M27.4 104.6h.5" fill="none" stroke="#800000" stroke-width=".25"/>
<circle cx="27.6" cy="89.6" r="2.54" fill="none" stroke="#00f" stroke-width=".25"/>
<path d="M27.6 89.6h5.1M27.6 92.1v2.6" fill="none" stroke="#000" stroke-width=".25"/>
<circle cx="27.6" cy="89.6" r=".64" fill="#00f"/>
<circle cx="27.6" cy="89.6" r=".64" fill="none" stroke="#00f" stroke-width=".21"/>
<path d="M60.7 84.5h38.1v20.3h-38.1z" fill-rule="evenodd" fill="#80ff80"/>
<path d="M60.7 84.5h38.1v20.3h-38.1z" fill="none" stroke="#800000" stroke-width=".21"/>
<path d="M60.7 98.8h2.8l1 1-1 1h-2.8z" fill-rule="evenodd" fill="#ffff80"/>
<path d="M60.7 98.8h2.8l1 1-1 1h-2.8z" fill="none" stroke="#800000" stroke-width=".21"/>
<path d="M60.7 88.6h2.8l1 1-1 1h-2.8z" fill-rule="evenodd" fill="#ffff80"/>
<path d="M60.7 88.6h2.8l1 1-1 1h-2.8z" fill="none" stroke="#800000" stroke-width=".21"/>
<path d="M95 88.6h2.8l1 1-1 1h-2.8z" fill-rule="evenodd" fill="#ffff80"/>
<path d="M95 88.6h2.8l1 1-1 1h-2.8z" fill="none" stroke="#800000" stroke-width=".21"/>
<path d="M95 99.8l1-1h2.8v2h-2.8z" fill-rule="evenodd" fill="#ffff80"/>
<path d="M95 99.8l1-1h2.8v2h-2.8z" fill="none" stroke="#800000" stroke-width=".21"/>
<path d="M111.5 84.5h43.2v10.2h-43.2z" fill-rule="evenodd" fill="#80ff80"/>
<path d="M111.5 84.5h43.2v10.2h-43.2z" fill="none" stroke="#800000" stroke-width=".21"/>
<path d="M111.5 88.6h2.8l1 1-1 1h-2.8z" fill-rule="evenodd" fill="#ffff80"/>
<path d="M111.5 88.6h2.8l1 1-1 1h-2.8z" fill="none" stroke="#800000" stroke-width=".21"/>
<path d="M150.9 88.6h2.8l1 1-1 1h-2.8z" fill-rule="evenodd" fill="#ffff80"/>
<path d="M150.9 88.6h2.8l1 1-1 1h-2.8z" fill="none" stroke="#800000" stroke-width=".21"/>
<path d="M175.1 84.5h43.2v33h-43.2z" fill-rule="evenodd" fill="#80ff80"/>
<path d="M175.1 84.5h43.2v33h-43.2z" fill="none" stroke="#800000" stroke-width=".21"/>
<path d="M175.1 88.6h2.7l1.1 1-1.1 1h-2.7z" fill-rule="evenodd" fill="#ffff80"/>
<path d="M175.1 88.6h2.7l1.1 1-1.1 1h-2.7z" fill="none" stroke="#800000" stroke-width=".21"/>
<path d="M214.4 91.1h2.8l1.1 1.1-1.1 1h-2.8z" fill-rule="evenodd" fill="#ffff80"/>
<path d="M214.4 91.1h2.8l1.1 1.1-1.1 1h-2.8z" fill="none" stroke="#800000" stroke-width=".21"/>
<path d="M175.1 101.3h2.7l1.1 1-1.1 1h-2.7z" fill-rule="evenodd" fill="#ffff80"/>
<path d="M175.1 101.3h2.7l1.1 1-1.1 1h-2.7z" fill="none" stroke="#800000" stroke-width=".21"/>
<path d="M214.4 88.6h2.8l1.1 1-1.1 1h-2.8z" fill-rule="evenodd" fill="#ffff80"/>
<path d="M214.4 88.6h2.8l1.1 1-1.1 1h-2.8z" fill="none" stroke="#800000" stroke-width=".21"/>
<path d="M214.4 99.8l1.1-1h2.8v2h-2.8z" fill-rule="evenodd" fill="#ffff80"/>
<path d="M214.4 99.8l1.1-1h2.8v2h-2.8z" fill="none" stroke="#800000" stroke-width=".21"/>
<path d="M175.1 103.8h2.7l1.1 1.1-1.1 1h-2.7z" fill-rule="evenodd" fill="#ffff80"/>
<path d="M175.1 103.8h2.7l1.1 1.1-1.1 1h-2.7z" fill="none" stroke="#800000" stroke-width=".21"/>
<path d="M175.1 98.8h2.7l1.1 1-1.1 1h-2.7z" fill-rule="evenodd" fill="#ffff80"/>
<path d="M175.1 98.8h2.7l1.1 1-1.1 1h-2.7z" fill="none" stroke="#800000" stroke-width=".21"/>
<path d="M175.1 108.9h2.7l1.1 1-1.1 1h-2.7z" fill-rule="evenodd" fill="#ffff80"/>
<path d="M175.1 108.9h2.7l1.1 1-1.1 1h-2.7z" fill="none" stroke="#800000" stroke-width=".21"/>
<circle cx="50.5" cy="99.8" r=".51" fill="#000080"/>
<circle cx="50.5" cy="99.8" r=".51" fill="none" stroke="#000080" stroke-width=".21"/>
<circle cx="109" cy="99.8" r=".51" fill="#000080"/>
<circle cx="109" cy="99.8" r=".51" fill="none" stroke="#000080" stroke-width=".21"/>
<path d="M266.6 88.3h11.4l1.3 1.3-1.3 1.3h-11.4z" fill-rule="evenodd" fill="#ffff80"/>
<path d="M266.6 88.3h11.4l1.3 1.3-1.3 1.3h-11.4z" fill="none" stroke="#800000" stroke-width=".21"/>
<path d="M266.6 90.9h11.4l1.3 1.3-1.3 1.2h-11.4z" fill-rule="evenodd" fill="#ffff80"/>
<path d="M266.6 90.9h11.4l1.3 1.3-1.3 1.2h-11.4z" fill="none" stroke="#800000" stroke-width=".21"/>
<path d="M35.3 98.5h11.4l1.3 1.3-1.3 1.2h-11.4z" fill-rule="evenodd" fill="#ffff80"/>
<path d="M35.3 98.5h11.4l1.3 1.3-1.3 1.2h-11.4z" fill="none" stroke="#800000" stroke-width=".21"/>
<path d="M111.5 99.8l1.3-1.3h14v2.5h-14z" fill-rule="evenodd" fill="#ffff80"/>
<path d="M111.5 99.8l1.3-1.3h14v2.5h-14z" fill="none" stroke="#800000" stroke-width=".21"/>
<path d="M139.5 98.5h13.9l1.3 1.3-1.3 1.2h-13.9z" fill-rule="evenodd" fill="#ffff80"/>
<path d="M139.5 98.5h13.9l1.3 1.3-1.3 1.2h-13.9z" fill="none" stroke="#800000" stroke-width=".21"/>
<path d="M139.5 103.6h13.9l1.3 1.2-1.3 1.3h-13.9z" fill-rule="evenodd" fill="#ffff80"/>
<path d="M139.5 103.6h13.9l1.3 1.2-1.3 1.3h-13.9z" fill="none" stroke="#800000" stroke-width=".21"/>
<path d="M139.5 101h13.9l1.3 1.3-1.3 1.3h-13.9z" fill-rule="evenodd" fill="#ffff80"/>
<path d="M139.5 101h13.9l1.3 1.3-1.3 1.3h-13.9z" fill="none" stroke="#800000" stroke-width=".21"/>
<path d="M142 108.7h11.4l1.3 1.2-1.3 1.3h-11.4z" fill-rule="evenodd" fill="#ffff80"/>
<path d="M142 108.7h11.4l1.3 1.2-1.3 1.3h-11.4z" fill="none" stroke="#800000" stroke-width=".21"/>
<path d="M231 99.8l1.2-1.3h11.5v2.5h-11.5z" fill-rule="evenodd" fill="#ffff80"/>
<path d="M231 99.8l1.2-1.3h11.5v2.5h-11.5z" fill="none" stroke="#800000" stroke-width=".21"/>
<path d="M228.4 71.8h5.1M228.4 74.4v2.5M241.1 92.2h2M249.3 92.2h2M251.3 89.6h2M259.5 89.6h2" fill="none" stroke="#000" stroke-width=".25"/>
<g fill="none" stroke="#00f" stroke-width=".25">
<path d="M243.2 91.2h6v2h-6zM253.4 88.6h6v2.1h-6z"/>
<circle cx="228.4" cy="71.8" r="2.54"/>
</g>
<circle cx="228.4" cy="71.8" r=".63" fill="#00f"/>
<circle cx="228.4" cy="71.8" r=".63" fill="none" stroke="#00f" stroke-width=".21"/>
<path d="M225.9 79.5h5.1M228.4 76.9v2.6M226.7 80.2h3.5M227.4 81h2M228.2 81.7h.5" fill="none" stroke="#800000" stroke-width=".25"/>
<circle cx="246.2" cy="71.8" r="2.54" fill="none" stroke="#00f" stroke-width=".25"/>
<path d="M241.1 71.8h5.1M246.2 74.4v2.5" fill="none" stroke="#000" stroke-width=".25"/>
<circle cx="246.2" cy="71.8" r=".63" fill="#00f"/>
<circle cx="246.2" cy="71.8" r=".63" fill="none" stroke="#00f" stroke-width=".21"/>
<path d="M243.7 79.5h5.1M246.2 76.9v2.6M244.4 80.2h3.6M245.2 81h2M246 81.7h.5" fill="none" stroke="#800000" stroke-width=".25"/>
<circle cx="50.5" cy="99.8" r=".51" fill="#000080"/>
<circle cx="50.5" cy="99.8" r=".51" fill="none" stroke="#000080" stroke-width=".21"/>
<path d="M50.5 99.8v2.5" fill="none" stroke="#000" stroke-width=".25"/>
<circle cx="50.5" cy="99.8" r=".51" fill="#000080"/>
<circle cx="50.5" cy="99.8" r=".51" fill="none" stroke="#000080" stroke-width=".21"/>
<circle cx="50.5" cy="103.6" r="1.27" fill="none" stroke="#000" stroke-width=".25"/>
<circle cx="109" cy="99.8" r=".51" fill="#000080"/>
<circle cx="109" cy="99.8" r=".51" fill="none" stroke="#000080" stroke-width=".21"/>
<path d="M109 99.8v2.5" fill="none" stroke="#000" stroke-width=".25"/>
<circle cx="109" cy="99.8" r=".51" fill="#000080"/>
<circle cx="109" cy="99.8" r=".51" fill="none" stroke="#000080" stroke-width=".21"/>
<circle cx="109" cy="103.6" r="1.27" fill="none" stroke="#000" stroke-width=".25"/>
<circle cx="170" cy="99.8" r=".51" fill="#000080"/>
<circle cx="170" cy="99.8" r=".51" fill="none" stroke="#000080" stroke-width=".21"/>
<path d="M170 97.2v2.6" fill="none" stroke="#000" stroke-width=".25"/>
<circle cx="170" cy="99.8" r=".51" fill="#000080"/>
<circle cx="170" cy="99.8" r=".51" fill="none" stroke="#000080" stroke-width=".21"/>
<g fill="none" stroke="#000" stroke-width=".25">
<path d="M269.1 148v5.1"/>
<circle cx="170" cy="96" r="1.27"/>
</g>
<path d="M260.2 135.3h-2.5v2.6M262.7 135.3h2.6M267.8 135.3h2.6M272.9 135.3h2.5M278 135.3h2.5v2.6M257.7 140.4v2.5M257.7 145.5v2.5h2.5M262.7 148h2.6M267.8 148h2.6M272.9 148h2.5M280.5 145.5v2.5h-2.5M280.5 140.4v2.5" fill="none" stroke="#00f" stroke-width=".76"/>
<path d="M266.6 155.6h5M267.3 156.4h3.6M268.1 157.2h2M268.8 157.9h.5M269.1 153.1v2.5" fill="none" stroke="#800000" stroke-width=".25"/>
<path d="M32.7 89.6h28M48 99.8h12.7" fill="none" stroke="#000080" stroke-width=".25"/>
<circle cx="50.5" cy="99.8" r=".51" fill="#000080"/>
<circle cx="50.5" cy="99.8" r=".51" fill="none" stroke="#000080" stroke-width=".21"/>
<path d="M98.8 99.8h12.7" fill="none" stroke="#000080" stroke-width=".25"/>
<circle cx="109" cy="99.8" r=".51" fill="#000080"/>
<circle cx="109" cy="99.8" r=".51" fill="none" stroke="#000080" stroke-width=".21"/>
<path d="M27.6 94.7v5.1M98.8 89.6h12.7M154.7 99.8h20.4M154.7 89.6h20.4M154.7 104.9h20.4M154.7 102.3h20.4" fill="none" stroke="#000080" stroke-width=".25"/>
<circle cx="170" cy="99.8" r=".51" fill="#000080"/>
<circle cx="170" cy="99.8" r=".51" fill="none" stroke="#000080" stroke-width=".21"/>
<path d="M218.3 89.6h33M218.3 99.8h12.7M154.7 109.9h20.4" fill="none" stroke="#000080" stroke-width=".25"/>
<circle cx="238.6" cy="89.6" r=".51" fill="#000080"/>
<circle cx="238.6" cy="89.6" r=".51" fill="none" stroke="#000080" stroke-width=".21"/>
<path d="M218.3 92.2h22.8M261.5 89.6h5.1" fill="none" stroke="#000080" stroke-width=".25"/>
<circle cx="236.1" cy="92.2" r=".51" fill="#000080"/>
<circle cx="236.1" cy="92.2" r=".51" fill="none" stroke="#000080" stroke-width=".21"/>
<path d="M233.5 71.8h2.6v20.4M251.3 92.2h15.3" fill="none" stroke="#000080" stroke-width=".25"/>
<circle cx="236.1" cy="92.2" r=".51" fill="#000080"/>
<circle cx="236.1" cy="92.2" r=".51" fill="none" stroke="#000080" stroke-width=".21"/>
<path d="M241.1 71.8h-2.5v17.8" fill="none" stroke="#000080" stroke-width=".25"/>
<circle cx="238.6" cy="89.6" r=".51" fill="#000080"/>
<circle cx="238.6" cy="89.6" r=".51" fill="none" stroke="#000080" stroke-width=".21"/>
<path d="M230 88h1l.5-.5h1l.5 .5h1M230 88.6h1l.5 .5h1l.5-.5h1M230 90.5h1l.5-.5h1l.5 .5h1M230 91.1h1l.5 .5h1l.5-.5h1" fill="none" stroke="#d0a19e" stroke-width=".25"/>
<path d="M230 88.6l-1.6 1M230 91.1l-1.6 1.1" fill="none" stroke="#d0a19e" stroke-width=".21"/>
<path d="M229.7 87.7h1l.5-.5h1l.5 .5h1.1M229.7 88.3h1l.5 .5h1l.5-.5h1.1M229.7 90.3h1l.5-.6h1l.5 .6h1.1M229.7 90.9h1l.5 .5h1l.5-.5h1.1" fill="none" stroke="#f00" stroke-width=".25"/>
<path d="M229.7 88.3l-1.3 1.3M229.7 90.9l-1.3 1.3" fill="none" stroke="#f00" stroke-width=".21"/>
<path d="M231 135.3h22.8v12.7h-22.8z" fill-rule="evenodd" fill="#ffffb0"/>
<path d="M231 135.3h22.8v12.7h-22.8z" fill="none" stroke="#800000" stroke-width=".21"/>
<use href="#words"/>
</svg>
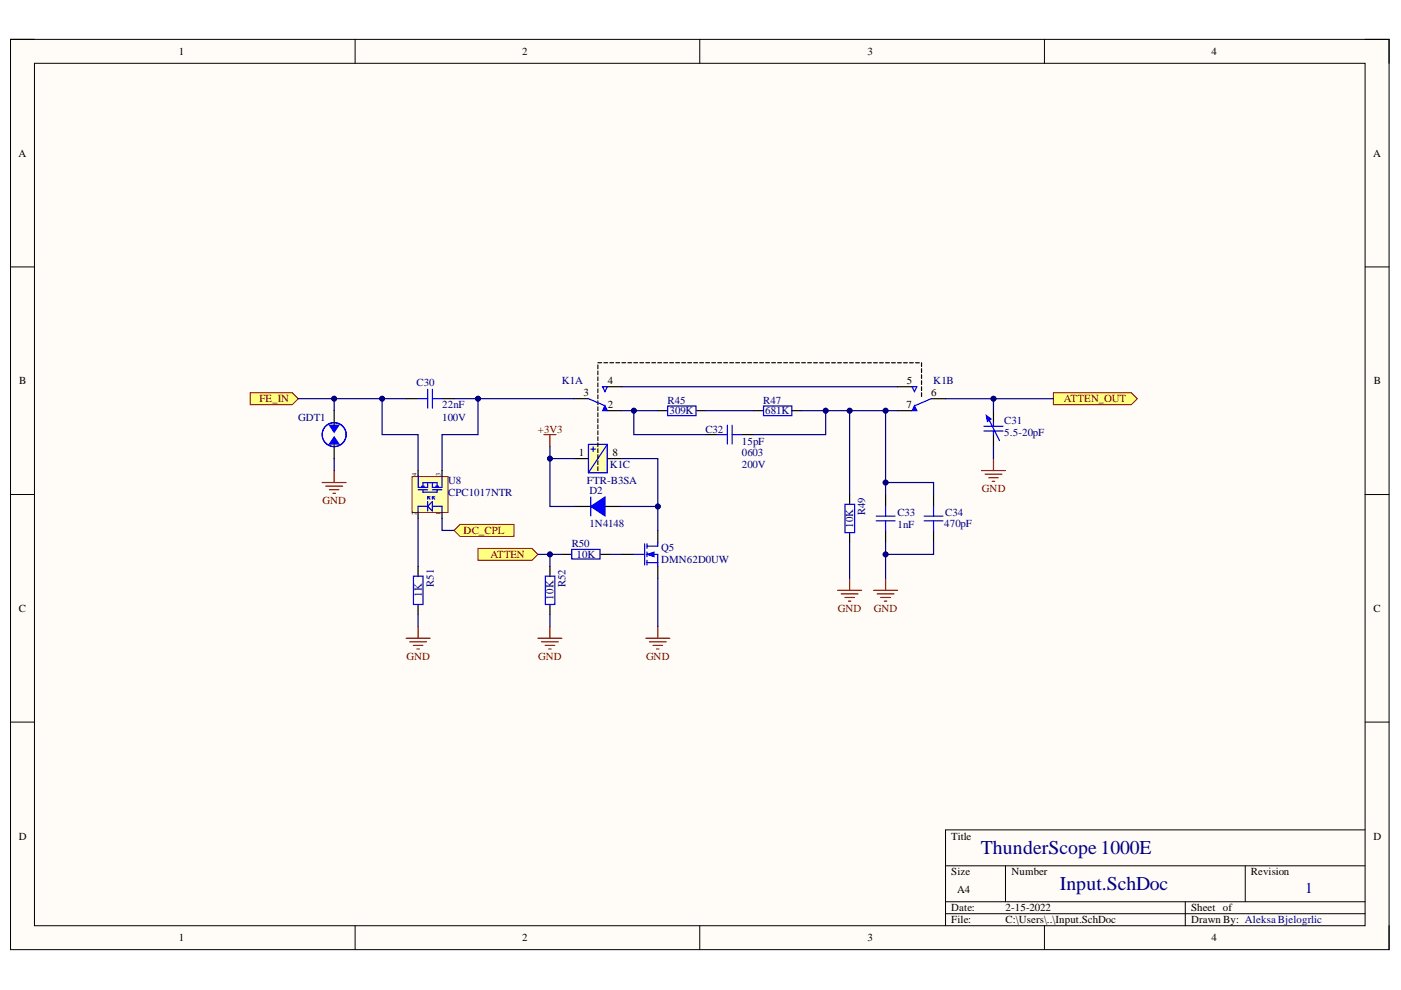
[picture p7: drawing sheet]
<svg xmlns="http://www.w3.org/2000/svg" width="297mm" height="210mm" viewBox="0 0 297 210" stroke-linecap="round" stroke-linejoin="round" font-family="sans-serif">
<defs><g id="words">
<g font-size="4.1" fill="#000080">
<text x="207.9" y="181.1">ThunderScope1000E</text>
<text x="224.7" y="188.8">Input.SchDoc</text>
</g>
<text font-size="3.2" fill="#000080" x="276.7" y="189.3">1</text>
<g font-size="2.3">
<text x="37.9" y="11.7">1</text>
<text x="110.7" y="11.7">2</text>
<text x="183.9" y="11.7">3</text>
<text x="256.8" y="11.7">4</text>
<text x="3.9" y="33.3">A</text>
<text x="291.1" y="33.3">A</text>
<text x="4.1" y="81.5">B</text>
<text x="128.8" y="81.5">4</text>
<text x="192.3" y="81.5">5</text>
<text x="291.3" y="81.5">B</text>
<text x="123.7" y="84">3</text>
<text x="128.8" y="86.6">2</text>
<text x="192.2" y="86.6">7</text>
<text x="197.5" y="84">6</text>
<text x="122.8" y="96.8">1</text>
<text x="129.9" y="96.8">8</text>
<text x="4" y="129.7">C</text>
<text x="291.2" y="129.7">C</text>
<text x="4" y="178">D</text>
<text x="201.7" y="178">Title</text>
<text x="291.2" y="178">D</text>
<text x="201.7" y="185.6">Size</text>
<text x="214.5" y="185.6">Number</text>
<text x="265.2" y="185.6">Revision</text>
<text x="203" y="189.4">A4</text>
<text x="201.7" y="193.2">Date:</text>
<text x="201.7" y="195.8">File:</text>
<text x="213.2" y="193.2">2-15-2022</text>
<text x="213.2" y="195.8">C:\Users\..\Input.SchDoc</text>
<text x="252.5" y="193.2">Sheet of</text>
<text x="252.5" y="195.8">Drawn By: Aleksa Bjelogrlic</text>
<text x="37.9" y="199.6">1</text>
<text x="110.7" y="199.6">2</text>
<text x="183.9" y="199.6">3</text>
<text x="256.8" y="199.6">4</text>
</g>
<g font-size="2.3" fill="#000080">
<text x="88.3" y="81.8">C30</text>
<text x="119.1" y="81.5">K1A</text>
<text x="197.9" y="81.5">K1B</text>
<text x="63.2" y="89.2">GDT1</text>
<text x="93.7" y="89.2">100V</text>
<text x="93.7" y="86.6">22nF</text>
<text x="141.5" y="85.6">R45</text>
<text x="142" y="87.8">309K</text>
<text x="161.8" y="85.6">R47</text>
<text x="162.3" y="87.8">681K</text>
<text x="212.9" y="89.9">C31</text>
<text x="149.6" y="91.7">C32</text>
<text x="157.3" y="94.2">15pF</text>
<text x="212.9" y="92.5">5.5-20pF</text>
<text x="129.3" y="99.3">K1C</text>
<text x="157.3" y="96.8">0603</text>
<text x="157.3" y="99.3">200V</text>
<text x="95" y="102.6">U8</text>
<text x="95" y="105.2">CPC1017NTR</text>
<text x="124.4" y="102.5">FTR-B3SA</text>
<text x="125" y="104.6">D2</text>
<text x="125" y="111.7">1N4148</text>
<text x="180.9" y="111.9" transform="rotate(-90 180.9 111.9)">10K</text>
<text x="183.4" y="109.2" transform="rotate(-90 183.4 109.2)">R49</text>
<text x="190.3" y="109.5">C33</text>
<text x="190.3" y="112">1nF</text>
<text x="200.2" y="111.7">470pF</text>
<text x="200.4" y="109.5">C34</text>
<text x="121.2" y="116">R50</text>
<text x="122.2" y="118.3">10K</text>
<text x="140.2" y="116.8">Q5</text>
<text x="140.2" y="119.4">DMN62D0UW</text>
<text x="92" y="124.4" transform="rotate(-90 92 124.4)">R51</text>
<text x="119.9" y="124.5" transform="rotate(-90 119.9 124.5)">R52</text>
<text x="89.4" y="126.5" transform="rotate(-90 89.4 126.5)">1K</text>
<text x="117.3" y="127.1" transform="rotate(-90 117.3 127.1)">10K</text>
</g>
<g font-size="2.3" fill="#800000">
<text x="55" y="85.3">FE_IN</text>
<text x="225.5" y="85.3">ATTEN_OUT</text>
<text x="114" y="91.7">+3V3</text>
<text x="68.4" y="106.9">GND</text>
<text x="208.2" y="104.4">GND</text>
<text x="98.3" y="113.3">DC_CPL</text>
<text x="104" y="118.3">ATTEN</text>
<text x="177.7" y="129.7">GND</text>
<text x="185.3" y="129.7">GND</text>
<text x="86.2" y="139.9">GND</text>
<text x="114.1" y="139.9">GND</text>
<text x="137" y="139.9">GND</text>
</g>
<g font-size="1.4">
<text x="88.3" y="101" transform="rotate(-90 88.3 101)">4</text>
<text x="93.4" y="101" transform="rotate(-90 93.4 101)">3</text>
<text x="88.3" y="109.3" transform="rotate(-90 88.3 109.3)">2</text>
<text x="93.4" y="109.2" transform="rotate(-90 93.4 109.2)">1</text>
</g>
</g></defs>
<path d="M2.2 8.3h292.3v193h-292.3z" fill-rule="evenodd" fill="#fffcf8"/>
<path d="M2.2 8.3h292.3v193h-292.3z" fill="none" stroke="#000" stroke-width=".21"/>
<path d="M7.3 13.4h282.1v182.9h-282.1z" fill-rule="evenodd" fill="#fffcf8"/>
<g fill="none" stroke="#000" stroke-width=".21">
<path d="M2.2 8.3h5.1M7.3 13.4h282.1v182.9h-282.1zM75.3 8.3v5.1M148.4 8.3v5.1M221.4 8.3v5.1M289.4 8.3h5.1v5.1M2.2 56.6h5.1M289.4 56.6h5.1M2.2 104.8h5.1M289.4 104.9h5.1M2.2 153.1h5.1M289.4 153.1h5.1"/>
<path d="M289.4 176h-88.9v20.3M75.3 196.3v5M148.4 196.3v5M200.5 183.6h88.9M200.5 191.2h88.9M200.5 193.7h88.9M213.2 183.6v7.6M221.4 196.3v5M251.3 191.2v5.1M264 183.6v7.6M294.5 196.3v5"/>
</g>
<path d="M124.8 94.2h4v6h-4z" fill-rule="evenodd" fill="#ffffb0"/>
<path d="M124.8 94.2h4v6h-4z" fill="none" stroke="#800000" stroke-width=".21"/>
<path d="M125.3 95.2h1M125.8 94.7v1M128.8 94.2l-4 6M128.8 94.2h-4v6M128.8 94.2v6h-4" fill="none" stroke="#00f" stroke-width=".25"/>
<path d="M121.7 97.2h3M128.8 97.2h3M121.7 107.4h3.8M128 107.4h3.8" fill="none" stroke="#000" stroke-width=".25"/>
<path d="M115.3 92.1h2.6M116.6 92.1v2.6" fill="none" stroke="#800000" stroke-width=".25"/>
<path d="M125.3 107.4l3-2v4z" fill="#00f"/>
<path d="M125.3 107.4l3-2v4zM125.3 105.4v4M134.4 117.5h2.3M136.7 115.3v4.5M137.2 115.8h2.3M137.2 117.5h2.3v2.6M137.2 119.3h2.3M137.2 115.3v1M137.2 117v1M137.2 118.8v1" fill="none" stroke="#00f" stroke-width=".25"/>
<path d="M131.8 117.5h2.6M139.5 112.5v2.5M139.5 120.1v2.5" fill="none" stroke="#000" stroke-width=".25"/>
<path d="M137.2 117.5l1.5-.5v1z" fill="#00f"/>
<path d="M137.2 117.5l1.5-.5v1z" fill="none" stroke="#00f" stroke-width=".21"/>
<path d="M139.5 115v.8M115.6 122.2h2.1v6h-2.1z" fill="none" stroke="#00f" stroke-width=".25"/>
<path d="M114.1 135.3h5M114.8 136.1h3.6M115.6 136.8h2M116.3 137.6h.5M116.6 132.8v2.5M136.9 135.3h5.1M137.7 136.1h3.5M138.5 136.8h2M139.2 137.6h.5M139.5 132.8v2.5" fill="none" stroke="#800000" stroke-width=".25"/>
<path d="M116.6 120.1v2M116.6 128.2v2" fill="none" stroke="#000" stroke-width=".25"/>
<path d="M101.3 116.3h11.5l1.3 1.2-1.3 1.3h-11.5z" fill-rule="evenodd" fill="#ffff80"/>
<path d="M101.3 116.3h11.5l1.3 1.2-1.3 1.3h-11.5z" fill="none" stroke="#800000" stroke-width=".21"/>
<g fill="none" stroke="#000" stroke-width=".25">
<path d="M126.8 77.4v.8M126.8 78.7v.8M126.8 79.9v.8M126.8 76.9h.8M128 76.9h.8M129.3 76.9h.8M130.6 76.9h.8M131.8 76.9h.8M133.1 76.9h.8M134.4 76.9h.8M135.7 76.9h.8M136.9 76.9h.8"/>
<path d="M138.2 76.9h.8M139.5 76.9h.8M140.7 76.9h.8M142 76.9h.8M143.3 76.9h.8M144.6 76.9h.7M145.8 76.9h.8M147.1 76.9h.8M148.4 76.9h.8M149.6 76.9h.8M150.9 76.9h.8M152.2 76.9h.8"/>
<path d="M153.4 76.9h.8M154.7 76.9h.8M156 76.9h.8M157.3 76.9h.8M158.5 76.9h.8M159.8 76.9h.8M161.1 76.9h.8M162.3 76.9h.8M163.6 76.9h.8M164.9 76.9h.8M166.2 76.9h.8M167.4 76.9h.8"/>
<path d="M168.7 76.9h.8M170 76.9h.8M171.2 76.9h.8M172.5 76.9h.8M173.8 76.9h.8M175.1 76.9h.8M176.3 76.9h.8M177.6 76.9h.8M178.9 76.9h.8M180.1 76.9h.8M181.4 76.9h.8M182.7 76.9h.8"/>
<path d="M184 76.9h.7M185.2 76.9h.8M186.5 76.9h.8M187.8 76.9h.8M189 76.9h.8M190.3 76.9h.8M191.6 76.9h.8M192.8 76.9h.8M194.1 76.9h.8M195.4 76.9v.8M195.4 78.2v.8M195.4 79.5v.7"/>
<path d="M126.8 81.2v.8M126.8 82.5v.8M126.8 83.7v.8M126.8 85v.8M126.8 86.3v.8M126.8 87.5v.8M126.8 88.8v.8M126.8 90.1v.8M126.8 91.4v.7M126.8 92.6v.8M126.8 93.9v.8M126.8 95.2v.8"/>
<path d="M126.8 96.4v.8M126.8 97.7v.8M126.8 99v.8M139.5 87.1h2M147.6 87.1h2M149.6 92.1h2.6M157.3 92.1h2.5M159.8 87.1h2M168 87.1h2M195.4 80.7v.8M195.4 82v.8M195.4 83.3v.8"/>
<path d="M180.1 104.9v2M180.1 113v2M187.8 104.9v2.5M187.8 112.5v2.5M197.9 104.9v2.5M197.9 112.5v2.5"/>
</g>
<g fill="none" stroke="#00f" stroke-width=".25">
<path d="M141.6 86.1h6v2h-6zM152.2 92.1h2M154.2 90.2v3.9M155.2 92.1h2.1M155.2 90.2v3.9M161.9 86.1h6v2h-6zM179.2 106.9h2v6h-2zM185.8 110.4h4M185.8 109.4h4M187.8 107.4v2M187.8 110.4v2.1M195.9 110.4h4"/>
<path d="M195.9 109.4h4M197.9 107.4v2M197.9 110.4v2.1"/>
</g>
<g fill="none" stroke="#800000" stroke-width=".25">
<path d="M208.1 99.8h5.1M210.6 97.2v2.6M208.9 100.5h3.5M209.6 101.3h2.1M210.4 102.1h.5M177.6 125.2h5.1M178.4 125.9h3.5M179.1 126.7h2.1M179.9 127.5h.5M180.1 122.6v2.6M185.2 125.2h5.1M186 125.9h3.5"/>
<path d="M186.7 126.7h2.1M187.5 127.5h.5M187.8 122.6v2.6"/>
</g>
<path d="M223.3 83.3h16.6l1.2 1.2-1.2 1.3h-16.6z" fill-rule="evenodd" fill="#ffff80"/>
<path d="M223.3 83.3h16.6l1.2 1.2-1.2 1.3h-16.6z" fill="none" stroke="#800000" stroke-width=".21"/>
<path d="M121.7 84.5h3" fill="none" stroke="#000" stroke-width=".25"/>
<path d="M124.8 84.5l3.5 1.5" fill="none" stroke="#00f" stroke-width=".25"/>
<path d="M128.3 86l.5 1.1h-1z" fill="#00f"/>
<path d="M127.8 82h1l-.5 1zM128.3 86l.5 1.1h-1zM193.4 82h1l-.5 1zM197.4 84.5l-3.5 1.5" fill="none" stroke="#00f" stroke-width=".25"/>
<path d="M128.8 87.1h3M128.8 82h3M197.5 84.5h3" fill="none" stroke="#000" stroke-width=".25"/>
<path d="M193.9 86l.5 1.1h-1z" fill="#00f"/>
<path d="M193.9 86l.5 1.1h-1zM121.2 116.5h6v2h-6z" fill="none" stroke="#00f" stroke-width=".25"/>
<path d="M190.3 82h3M190.3 87.1h3M119.1 117.5h2M127.3 117.5h2" fill="none" stroke="#000" stroke-width=".25"/>
<path d="M53.1 83.3h8.9l1.2 1.2-1.2 1.3h-8.9z" fill-rule="evenodd" fill="#ffff80"/>
<path d="M53.1 83.3h8.9l1.2 1.2-1.2 1.3h-8.9z" fill="none" stroke="#800000" stroke-width=".21"/>
<path d="M70.8 99.8v2.5M68.3 102.3h5.1M69.1 103.1h3.5M69.8 103.8h2.1M70.6 104.6h.5M86.1 135.3h5.1M86.9 136.1h3.5M87.6 136.8h2.1M88.4 137.6h.5M88.6 132.8v2.5" fill="none" stroke="#800000" stroke-width=".25"/>
<path d="M86.1 84.5h2.5M93.7 84.5h2.6M88.6 120.1v2M88.6 128.2v2" fill="none" stroke="#000" stroke-width=".25"/>
<path d="M88.6 84.5h2.1M90.7 82.5v4M91.7 84.5h2M91.7 82.5v4M87.7 122.2h2v6h-2z" fill="none" stroke="#00f" stroke-width=".25"/>
<path d="M97.5 111.2h11.5v2.5h-11.5l-1.2-1.2z" fill-rule="evenodd" fill="#ffff80"/>
<path d="M97.5 111.2h11.5v2.5h-11.5l-1.2-1.2z" fill="none" stroke="#800000" stroke-width=".21"/>
<circle cx="70.8" cy="92.2" r="2.54" fill="none" stroke="#00f" stroke-width=".25"/>
<path d="M69.8 90.2h2l-1 1.5z" fill="#00f"/>
<path d="M69.8 90.2h2l-1 1.5z" fill="none" stroke="#00f" stroke-width=".25"/>
<path d="M70.8 92.6l1 1.5h-2z" fill="#00f"/>
<path d="M70.8 92.6l1 1.5h-2z" fill="none" stroke="#00f" stroke-width=".25"/>
<path d="M70.8 87.1v2.9M70.8 94.3v2.9" fill="none" stroke="#000" stroke-width=".25"/>
<path d="M87.4 101h7.6v7.7h-7.6z" fill-rule="evenodd" fill="#ffffb0"/>
<path d="M87.4 101h7.6v7.7h-7.6z" fill="none" stroke="#800000" stroke-width=".21"/>
<path d="M88.6 99.8v1.2M93.7 99.8v1.2M210.6 87.1v2.5M210.6 92.2v2.5M88.6 108.7v1.2M93.7 108.7v1.2" fill="none" stroke="#000" stroke-width=".25"/>
<g fill="none" stroke="#00f" stroke-width=".25">
<path d="M209.6 88.8l2.3 4.6M88.7 100.8v2.5h2v-1M88.7 103.8h2M89.4 103.1h.5l-.2 .2zM89.7 103.8v.5h3v-.5M89.7 103.3v-1h3v1M90.7 107.3l1-1v2zM90.7 105.3h.5M90.7 105.3l.5 .5M90.7 105.3v.5M90.7 106.3v2M90.7 107.3h-2.1v1.4"/>
<path d="M91.7 105.3l.5 .5M91.7 102.3v1h2M91.7 105.3v.5M91.7 105.3h.5M91.7 103.8h2M91.7 107.3h2v1.4M92.4 103.1h.5l-.2 .2zM93.7 101v2.3"/>
</g>
<path d="M209.1 88.1l1 .7-.7 .6z" fill="#00f"/>
<path d="M208.6 90.4h4.1M208.6 91.4h4.1M209.1 88.1l1 .7-.7 .6zM210.6 89.6v.8M210.6 91.4v.8" fill="none" stroke="#00f" stroke-width=".25"/>
<path d="M63.2 84.5h22.9M210.6 94.7v2.5" fill="none" stroke="#000080" stroke-width=".25"/>
<circle cx="70.8" cy="84.5" r=".51" fill="#000080"/>
<circle cx="70.8" cy="84.5" r=".51" fill="none" stroke="#000080" stroke-width=".21"/>
<circle cx="81" cy="84.5" r=".51" fill="#000080"/>
<circle cx="81" cy="84.5" r=".51" fill="none" stroke="#000080" stroke-width=".21"/>
<path d="M81 84.5v7.6h7.6v7.7" fill="none" stroke="#000080" stroke-width=".25"/>
<circle cx="81" cy="84.5" r=".51" fill="#000080"/>
<circle cx="81" cy="84.5" r=".51" fill="none" stroke="#000080" stroke-width=".21"/>
<path d="M96.3 84.5h5v7.6h-7.6v7.7" fill="none" stroke="#000080" stroke-width=".25"/>
<circle cx="101.3" cy="84.5" r=".51" fill="#000080"/>
<circle cx="101.3" cy="84.5" r=".51" fill="none" stroke="#000080" stroke-width=".21"/>
<path d="M101.3 84.5h20.4" fill="none" stroke="#000080" stroke-width=".25"/>
<circle cx="101.3" cy="84.5" r=".51" fill="#000080"/>
<circle cx="101.3" cy="84.5" r=".51" fill="none" stroke="#000080" stroke-width=".21"/>
<path d="M114.1 117.5h2.5" fill="none" stroke="#000080" stroke-width=".25"/>
<circle cx="116.6" cy="117.5" r=".51" fill="#000080"/>
<circle cx="116.6" cy="117.5" r=".51" fill="none" stroke="#000080" stroke-width=".21"/>
<path d="M119.1 117.5h-2.5v2.6" fill="none" stroke="#000080" stroke-width=".25"/>
<circle cx="116.6" cy="117.5" r=".51" fill="#000080"/>
<circle cx="116.6" cy="117.5" r=".51" fill="none" stroke="#000080" stroke-width=".21"/>
<path d="M116.6 97.2v10.2h5.1" fill="none" stroke="#000080" stroke-width=".25"/>
<circle cx="116.6" cy="97.2" r=".51" fill="#000080"/>
<circle cx="116.6" cy="97.2" r=".51" fill="none" stroke="#000080" stroke-width=".21"/>
<path d="M116.6 94.7v2.5h5.1" fill="none" stroke="#000080" stroke-width=".25"/>
<circle cx="116.6" cy="97.2" r=".51" fill="#000080"/>
<circle cx="116.6" cy="97.2" r=".51" fill="none" stroke="#000080" stroke-width=".21"/>
<path d="M129.3 117.5h2.5M131.8 107.4h7.7" fill="none" stroke="#000080" stroke-width=".25"/>
<circle cx="139.5" cy="107.4" r=".51" fill="#000080"/>
<circle cx="139.5" cy="107.4" r=".51" fill="none" stroke="#000080" stroke-width=".21"/>
<path d="M131.8 97.2h7.7v15.3" fill="none" stroke="#000080" stroke-width=".25"/>
<circle cx="139.5" cy="107.4" r=".51" fill="#000080"/>
<circle cx="139.5" cy="107.4" r=".51" fill="none" stroke="#000080" stroke-width=".21"/>
<path d="M131.8 87.1h7.7" fill="none" stroke="#000080" stroke-width=".25"/>
<circle cx="134.4" cy="87.1" r=".51" fill="#000080"/>
<circle cx="134.4" cy="87.1" r=".51" fill="none" stroke="#000080" stroke-width=".21"/>
<path d="M131.8 82h58.5M134.4 87.1v5h15.2" fill="none" stroke="#000080" stroke-width=".25"/>
<circle cx="134.4" cy="87.1" r=".51" fill="#000080"/>
<circle cx="134.4" cy="87.1" r=".51" fill="none" stroke="#000080" stroke-width=".21"/>
<path d="M175.1 87.1v5.1h-15.3" fill="none" stroke="#000080" stroke-width=".25"/>
<circle cx="175.1" cy="87.1" r=".51" fill="#000080"/>
<circle cx="175.1" cy="87.1" r=".51" fill="none" stroke="#000080" stroke-width=".21"/>
<path d="M197.9 115v2.5h-10.1" fill="none" stroke="#000080" stroke-width=".25"/>
<circle cx="187.8" cy="117.5" r=".51" fill="#000080"/>
<circle cx="187.8" cy="117.5" r=".51" fill="none" stroke="#000080" stroke-width=".21"/>
<path d="M187.8 102.3h10.1v2.6" fill="none" stroke="#000080" stroke-width=".25"/>
<circle cx="187.8" cy="102.3" r=".51" fill="#000080"/>
<circle cx="187.8" cy="102.3" r=".51" fill="none" stroke="#000080" stroke-width=".21"/>
<path d="M200.5 84.5h22.8" fill="none" stroke="#000080" stroke-width=".25"/>
<circle cx="210.6" cy="84.5" r=".51" fill="#000080"/>
<circle cx="210.6" cy="84.5" r=".51" fill="none" stroke="#000080" stroke-width=".21"/>
<path d="M70.8 84.5v2.6M70.8 97.2v2.6" fill="none" stroke="#000080" stroke-width=".25"/>
<circle cx="70.8" cy="84.5" r=".51" fill="#000080"/>
<circle cx="70.8" cy="84.5" r=".51" fill="none" stroke="#000080" stroke-width=".21"/>
<path d="M180.1 115v7.6M187.8 115v7.6M88.6 130.2v2.6M116.6 130.2v2.6M139.5 122.6v10.2" fill="none" stroke="#000080" stroke-width=".25"/>
<circle cx="187.8" cy="117.5" r=".51" fill="#000080"/>
<circle cx="187.8" cy="117.5" r=".51" fill="none" stroke="#000080" stroke-width=".21"/>
<path d="M187.8 87.1v17.8" fill="none" stroke="#000080" stroke-width=".25"/>
<circle cx="187.8" cy="102.3" r=".51" fill="#000080"/>
<circle cx="187.8" cy="102.3" r=".51" fill="none" stroke="#000080" stroke-width=".21"/>
<circle cx="187.8" cy="87.1" r=".51" fill="#000080"/>
<circle cx="187.8" cy="87.1" r=".51" fill="none" stroke="#000080" stroke-width=".21"/>
<path d="M210.6 84.5v2.6" fill="none" stroke="#000080" stroke-width=".25"/>
<circle cx="210.6" cy="84.5" r=".51" fill="#000080"/>
<circle cx="210.6" cy="84.5" r=".51" fill="none" stroke="#000080" stroke-width=".21"/>
<path d="M180.1 87.1v17.8M88.6 109.9v10.2M93.7 109.9v2.6h2.6" fill="none" stroke="#000080" stroke-width=".25"/>
<circle cx="180.1" cy="87.1" r=".51" fill="#000080"/>
<circle cx="180.1" cy="87.1" r=".51" fill="none" stroke="#000080" stroke-width=".21"/>
<path d="M149.6 87.1h10.2M170 87.1h20.3" fill="none" stroke="#000080" stroke-width=".25"/>
<circle cx="175.1" cy="87.1" r=".51" fill="#000080"/>
<circle cx="175.1" cy="87.1" r=".51" fill="none" stroke="#000080" stroke-width=".21"/>
<circle cx="180.1" cy="87.1" r=".51" fill="#000080"/>
<circle cx="180.1" cy="87.1" r=".51" fill="none" stroke="#000080" stroke-width=".21"/>
<circle cx="187.8" cy="87.1" r=".51" fill="#000080"/>
<circle cx="187.8" cy="87.1" r=".51" fill="none" stroke="#000080" stroke-width=".21"/>
<use href="#words"/>
</svg>
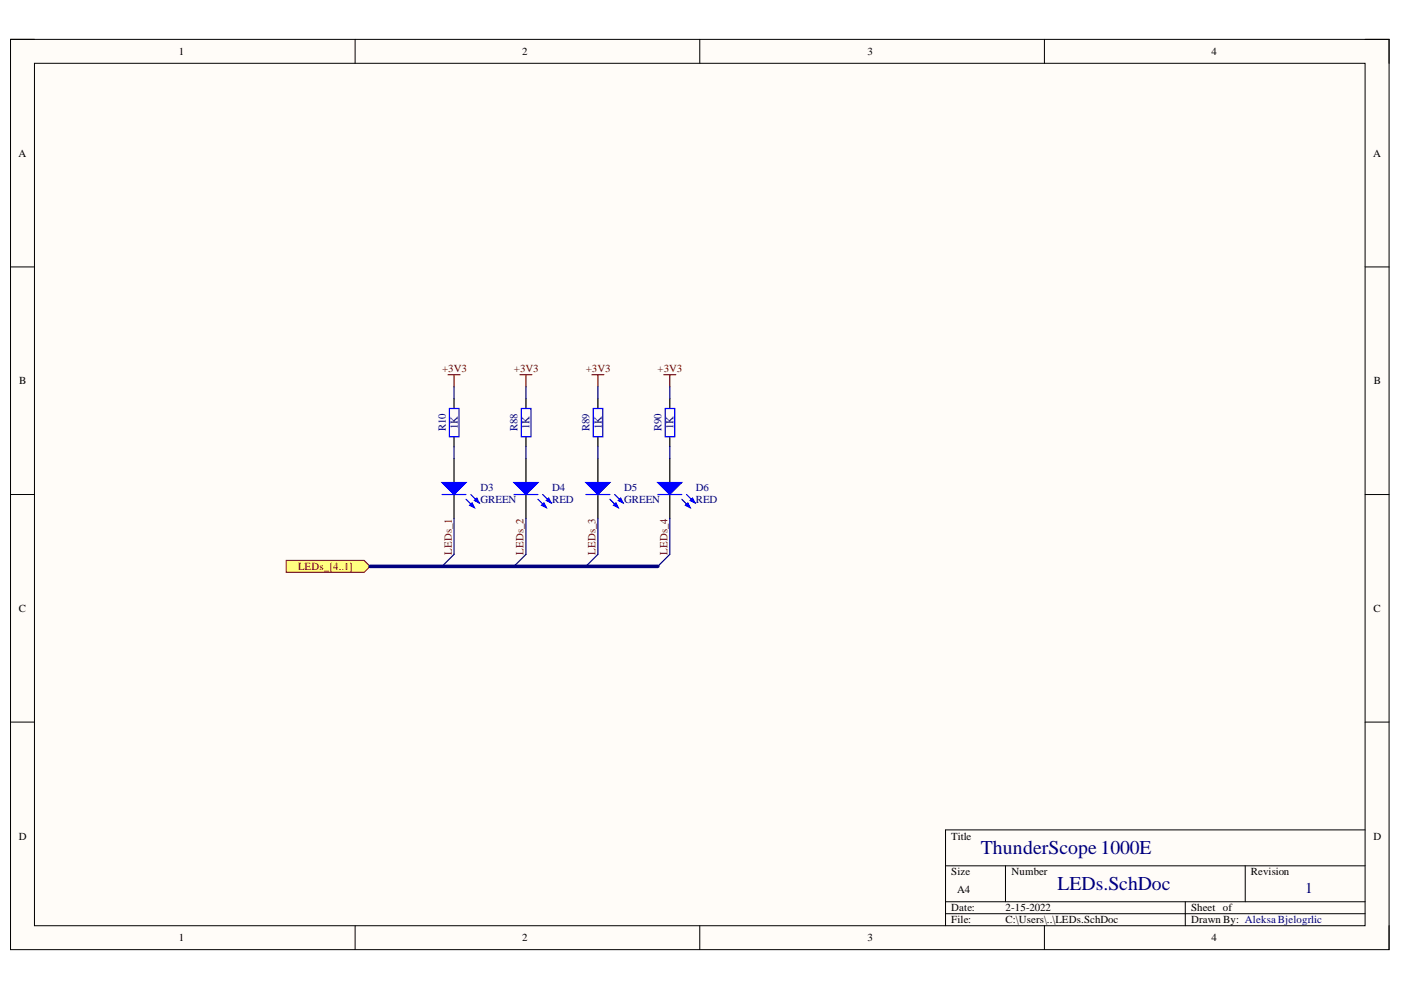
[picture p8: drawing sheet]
<svg xmlns="http://www.w3.org/2000/svg" width="297mm" height="210mm" viewBox="0 0 297 210" stroke-linecap="round" stroke-linejoin="round" font-family="sans-serif">
<defs><g id="words">
<g font-size="4.1" fill="#000080">
<text x="207.9" y="181.1">ThunderScope1000E</text>
<text x="224.2" y="188.8">LEDs.SchDoc</text>
</g>
<text font-size="3.2" fill="#000080" x="276.7" y="189.3">1</text>
<g font-size="2.3">
<text x="37.9" y="11.7">1</text>
<text x="110.7" y="11.7">2</text>
<text x="183.9" y="11.7">3</text>
<text x="256.8" y="11.7">4</text>
<text x="3.9" y="33.3">A</text>
<text x="291.1" y="33.3">A</text>
<text x="4.1" y="81.5">B</text>
<text x="291.3" y="81.5">B</text>
<text x="4" y="129.7">C</text>
<text x="291.2" y="129.7">C</text>
<text x="4" y="178">D</text>
<text x="201.7" y="178">Title</text>
<text x="291.2" y="178">D</text>
<text x="201.7" y="185.6">Size</text>
<text x="214.5" y="185.6">Number</text>
<text x="265.2" y="185.6">Revision</text>
<text x="203" y="189.4">A4</text>
<text x="201.7" y="193.2">Date:</text>
<text x="201.7" y="195.8">File:</text>
<text x="213.2" y="193.2">2-15-2022</text>
<text x="213.2" y="195.8">C:\Users\..\LEDs.SchDoc</text>
<text x="252.5" y="193.2">Sheet of</text>
<text x="252.5" y="195.8">Drawn By: Aleksa Bjelogrlic</text>
<text x="37.9" y="199.6">1</text>
<text x="110.7" y="199.6">2</text>
<text x="183.9" y="199.6">3</text>
<text x="256.8" y="199.6">4</text>
</g>
<g font-size="2.3" fill="#800000">
<text x="93.7" y="78.9">+3V3</text>
<text x="109" y="78.9">+3V3</text>
<text x="124.2" y="78.9">+3V3</text>
<text x="139.4" y="78.9">+3V3</text>
<text x="95.8" y="117.6" transform="rotate(-90 95.8 117.6)">LEDs_1</text>
<text x="111" y="117.6" transform="rotate(-90 111 117.6)">LEDs_2</text>
<text x="126.2" y="117.6" transform="rotate(-90 126.2 117.6)">LEDs_3</text>
<text x="141.5" y="117.6" transform="rotate(-90 141.5 117.6)">LEDs_4</text>
<text x="63.2" y="120.9">LEDs_[4..1]</text>
</g>
<g font-size="2.3" fill="#000080">
<text x="94.5" y="91.5" transform="rotate(-90 94.5 91.5)">R10</text>
<text x="97" y="91" transform="rotate(-90 97 91)">1K</text>
<text x="109.7" y="91.5" transform="rotate(-90 109.7 91.5)">R88</text>
<text x="112.3" y="91" transform="rotate(-90 112.3 91)">1K</text>
<text x="125" y="91.5" transform="rotate(-90 125 91.5)">R89</text>
<text x="127.6" y="91" transform="rotate(-90 127.6 91)">1K</text>
<text x="140.3" y="91.5" transform="rotate(-90 140.3 91.5)">R90</text>
<text x="142.8" y="91" transform="rotate(-90 142.8 91)">1K</text>
<text x="101.9" y="104.1">D3</text>
<text x="101.9" y="106.7">GREEN</text>
<text x="117.1" y="104.1">D4</text>
<text x="117.1" y="106.7">RED</text>
<text x="132.3" y="104.1">D5</text>
<text x="132.3" y="106.7">GREEN</text>
<text x="147.5" y="104.1">D6</text>
<text x="147.5" y="106.7">RED</text>
</g>
</g></defs>
<path d="M2.2 8.3h292.3v193h-292.3z" fill-rule="evenodd" fill="#fffcf8"/>
<path d="M2.2 8.3h292.3v193h-292.3z" fill="none" stroke="#000" stroke-width=".21"/>
<path d="M7.3 13.4h282.1v182.9h-282.1z" fill-rule="evenodd" fill="#fffcf8"/>
<g fill="none" stroke="#000" stroke-width=".21">
<path d="M2.2 8.3h5.1M7.3 13.4h282.1v182.9h-282.1zM75.3 8.3v5.1M148.4 8.3v5.1M221.4 8.3v5.1M289.4 8.3h5.1v5.1M2.2 56.6h5.1M289.4 56.6h5.1M2.2 104.8h5.1M289.4 104.9h5.1M2.2 153.1h5.1M289.4 153.1h5.1"/>
<path d="M289.4 176h-88.9v20.3M75.3 196.3v5M148.4 196.3v5M200.5 183.6h88.9M200.5 191.2h88.9M200.5 193.7h88.9M213.2 183.6v7.6M221.4 196.3v5M251.3 191.2v5.1M264 183.6v7.6M294.5 196.3v5"/>
</g>
<path d="M60.7 118.8h16.5l1.3 1.3-1.3 1.3h-16.5z" fill-rule="evenodd" fill="#ffff80"/>
<path d="M60.7 118.8h16.5l1.3 1.3-1.3 1.3h-16.5z" fill="none" stroke="#800000" stroke-width=".21"/>
<path d="M96.3 97.2v5.1M96.3 104.8v5.1" fill="none" stroke="#000" stroke-width=".25"/>
<path d="M93.7 102.3h5.1l-2.5 2.5z" fill="#00f"/>
<path d="M93.7 102.3h5.1l-2.5 2.5zM98.8 105.9l1.8 1.7M99.8 104.8l1.8 1.8" fill="none" stroke="#00f" stroke-width=".25"/>
<path d="M99.6 107.1l.5-.5 .5 1z" fill="#00f"/>
<path d="M99.6 107.1l.5-.5 .5 1z" fill="none" stroke="#00f" stroke-width=".25"/>
<path d="M100.6 106.1l.5-.5 .5 1z" fill="#00f"/>
<path d="M93.7 104.8h5.1M100.6 106.1l.5-.5 .5 1z" fill="none" stroke="#00f" stroke-width=".25"/>
<path d="M111.5 97.2v5.1M111.5 104.8v5.1" fill="none" stroke="#000" stroke-width=".25"/>
<path d="M109 102.3h5.1l-2.6 2.5z" fill="#00f"/>
<path d="M109 102.3h5.1l-2.6 2.5zM114.1 105.9l1.7 1.7M115.1 104.8l1.7 1.8" fill="none" stroke="#00f" stroke-width=".25"/>
<path d="M114.8 107.1l.5-.5 .5 1z" fill="#00f"/>
<path d="M114.8 107.1l.5-.5 .5 1z" fill="none" stroke="#00f" stroke-width=".25"/>
<path d="M115.8 106.1l.5-.5 .5 1z" fill="#00f"/>
<path d="M109 104.8h5.1M115.8 106.1l.5-.5 .5 1z" fill="none" stroke="#00f" stroke-width=".25"/>
<path d="M126.8 97.2v5.1M126.8 104.8v5.1" fill="none" stroke="#000" stroke-width=".25"/>
<path d="M124.2 102.3h5.1l-2.5 2.5z" fill="#00f"/>
<path d="M124.2 102.3h5.1l-2.5 2.5zM129.3 105.9l1.8 1.7M130.3 104.8l1.8 1.8" fill="none" stroke="#00f" stroke-width=".25"/>
<path d="M130.1 107.1l.5-.5 .5 1z" fill="#00f"/>
<path d="M130.1 107.1l.5-.5 .5 1z" fill="none" stroke="#00f" stroke-width=".25"/>
<path d="M131.1 106.1l.5-.5 .5 1z" fill="#00f"/>
<path d="M124.2 104.8h5.1M131.1 106.1l.5-.5 .5 1z" fill="none" stroke="#00f" stroke-width=".25"/>
<path d="M142 97.2v5.1M142 104.8v5.1" fill="none" stroke="#000" stroke-width=".25"/>
<path d="M139.5 102.3h5.1l-2.6 2.5z" fill="#00f"/>
<path d="M139.5 102.3h5.1l-2.6 2.5zM144.6 105.9l1.7 1.7M145.6 104.8l1.8 1.8" fill="none" stroke="#00f" stroke-width=".25"/>
<path d="M145.3 107.1l.5-.5 .5 1z" fill="#00f"/>
<path d="M145.3 107.1l.5-.5 .5 1z" fill="none" stroke="#00f" stroke-width=".25"/>
<path d="M146.3 106.1l.5-.5 .6 1z" fill="#00f"/>
<path d="M95.3 86.6h2v6h-2zM110.5 86.6h2.1v6h-2.1zM125.8 86.6h2v6h-2zM141 86.6h2.1v6h-2.1zM139.5 104.8h5.1M146.3 106.1l.5-.5 .6 1z" fill="none" stroke="#00f" stroke-width=".25"/>
<path d="M96.3 84.5v2M96.3 92.7v2M111.5 84.5v2M111.5 92.7v2M126.8 84.5v2M126.8 92.7v2M142 84.5v2M142 92.7v2" fill="none" stroke="#000" stroke-width=".25"/>
<path d="M95 79.5h2.5M96.3 79.5v2.5M110.2 79.5h2.6M111.5 79.5v2.5M125.5 79.5h2.5M126.8 79.5v2.5M140.7 79.5h2.6M142 79.5v2.5" fill="none" stroke="#800000" stroke-width=".25"/>
<path d="M96.3 82v2.5M96.3 94.7v2.5M111.5 82v2.5M111.5 94.7v2.5M126.8 82v2.5M126.8 94.7v2.5M142 82v2.5M142 94.7v2.5M96.3 109.9v7.6l-2.6 2.6M111.5 109.9v7.6l-2.5 2.6M126.8 109.9v7.6l-2.6 2.6M142 109.9v7.6l-2.5 2.6" fill="none" stroke="#000080" stroke-width=".25"/>
<path d="M78.5 120.1h61" fill="none" stroke="#000080" stroke-width=".76"/>
<use href="#words"/>
</svg>
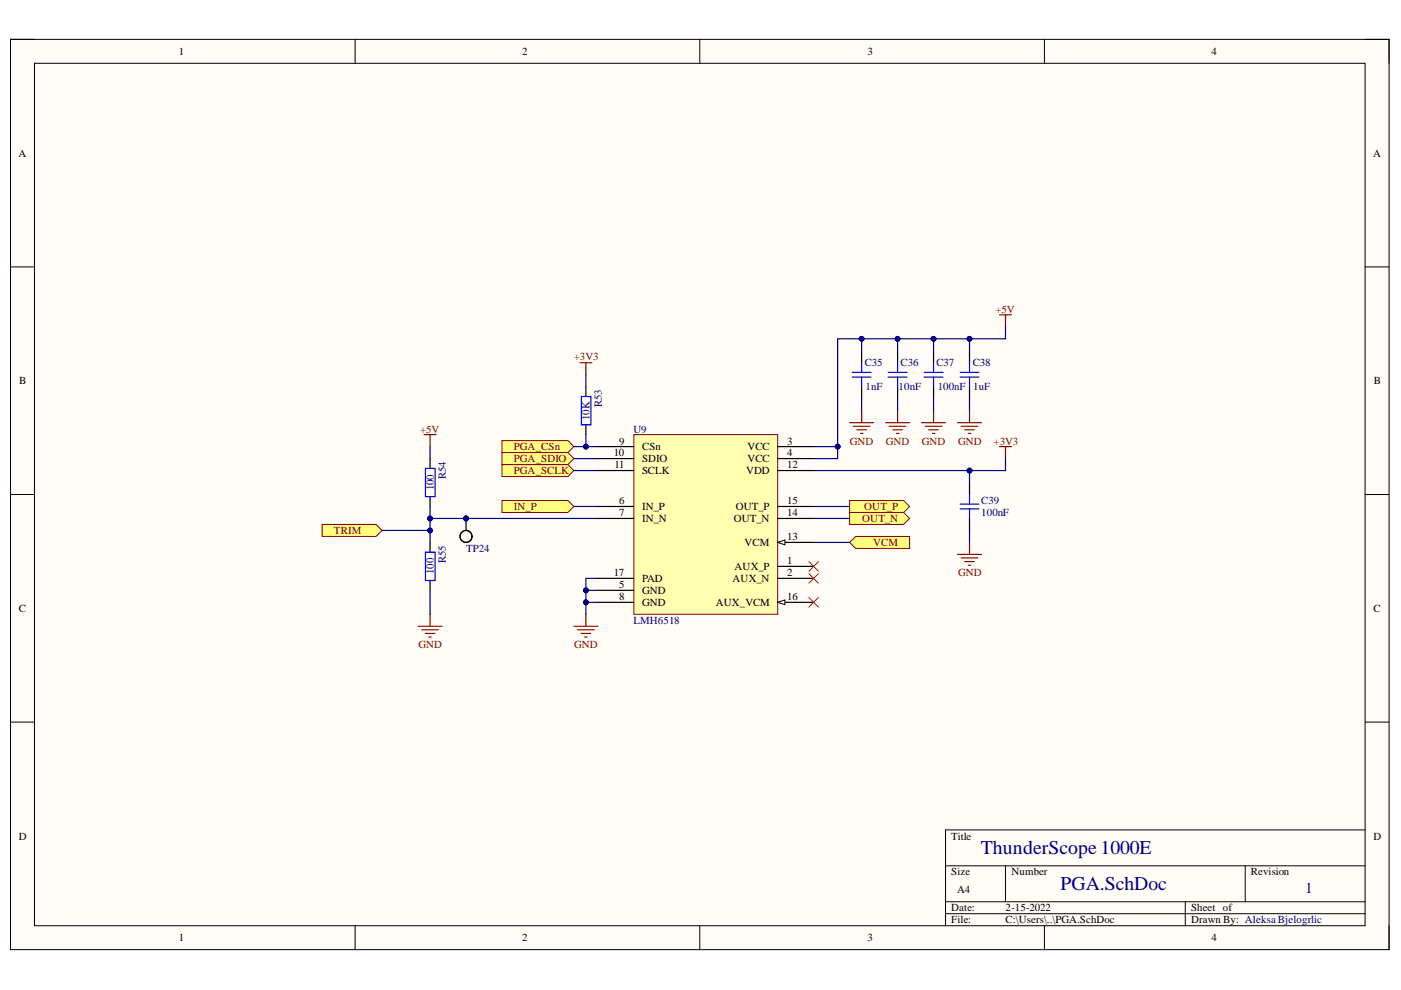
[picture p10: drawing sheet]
<svg xmlns="http://www.w3.org/2000/svg" width="297mm" height="210mm" viewBox="0 0 297 210" stroke-linecap="round" stroke-linejoin="round" font-family="sans-serif">
<defs><g id="words">
<g font-size="4.1" fill="#000080">
<text x="207.9" y="181.1">ThunderScope1000E</text>
<text x="224.9" y="188.8">PGA.SchDoc</text>
</g>
<text font-size="3.2" fill="#000080" x="276.7" y="189.3">1</text>
<g font-size="2.3">
<text x="37.9" y="11.7">1</text>
<text x="110.7" y="11.7">2</text>
<text x="183.9" y="11.7">3</text>
<text x="256.8" y="11.7">4</text>
<text x="3.9" y="33.3">A</text>
<text x="291.1" y="33.3">A</text>
<text x="4.1" y="81.5">B</text>
<text x="291.3" y="81.5">B</text>
<text x="131.3" y="94.2">9</text>
<text x="136.1" y="95.5">CSn</text>
<text x="158.5" y="95.5">VCC</text>
<text x="166.9" y="94.2">3</text>
<text x="130.1" y="96.8">10</text>
<text x="130.3" y="99.3">11</text>
<text x="136.1" y="98">SDIO</text>
<text x="136.1" y="100.6">SCLK</text>
<text x="158.2" y="100.6">VDD</text>
<text x="158.5" y="98">VCC</text>
<text x="166.9" y="99.3">12</text>
<text x="166.9" y="96.8">4</text>
<text x="131.3" y="106.9">6</text>
<text x="166.9" y="106.9">15</text>
<text x="131.3" y="109.5">7</text>
<text x="136.1" y="108.2">IN_P</text>
<text x="136.1" y="110.7">IN_N</text>
<text x="155.6" y="110.7">OUT_N</text>
<text x="156" y="108.2">OUT_P</text>
<text x="166.9" y="109.5">14</text>
<text x="157.9" y="115.8">VCM</text>
<text x="166.9" y="114.5">13</text>
<text x="166.9" y="119.6">1</text>
<text x="130.1" y="122.1">17</text>
<text x="131.3" y="124.7">5</text>
<text x="136.1" y="125.9">GND</text>
<text x="136.1" y="123.4">PAD</text>
<text x="155.3" y="123.4">AUX_N</text>
<text x="155.7" y="120.9">AUX_P</text>
<text x="166.9" y="122.1">2</text>
<text x="4" y="129.7">C</text>
<text x="131.3" y="127.2">8</text>
<text x="136.1" y="128.5">GND</text>
<text x="151.8" y="128.5">AUX_VCM</text>
<text x="166.9" y="127.2">16</text>
<text x="291.2" y="129.7">C</text>
<text x="4" y="178">D</text>
<text x="201.7" y="178">Title</text>
<text x="291.2" y="178">D</text>
<text x="201.7" y="185.6">Size</text>
<text x="214.5" y="185.6">Number</text>
<text x="265.2" y="185.6">Revision</text>
<text x="203" y="189.4">A4</text>
<text x="201.7" y="193.2">Date:</text>
<text x="201.7" y="195.8">File:</text>
<text x="213.2" y="193.2">2-15-2022</text>
<text x="213.2" y="195.8">C:\Users\..\PGA.SchDoc</text>
<text x="252.5" y="193.2">Sheet of</text>
<text x="252.5" y="195.8">Drawn By: Aleksa Bjelogrlic</text>
<text x="37.9" y="199.6">1</text>
<text x="110.7" y="199.6">2</text>
<text x="183.9" y="199.6">3</text>
<text x="256.8" y="199.6">4</text>
</g>
<g font-size="2.3" fill="#800000">
<text x="211.1" y="66.3">+5V</text>
<text x="121.7" y="76.4">+3V3</text>
<text x="89.1" y="91.7">+5V</text>
<text x="109" y="95.5">PGA_CSn</text>
<text x="180.2" y="94.2">GND</text>
<text x="187.8" y="94.2">GND</text>
<text x="195.4" y="94.2">GND</text>
<text x="203.1" y="94.2">GND</text>
<text x="210.7" y="94.2">+3V3</text>
<text x="109" y="100.6">PGA_SCLK</text>
<text x="109" y="98">PGA_SDIO</text>
<text x="70.8" y="113.3">TRIM</text>
<text x="109" y="108.2">IN_P</text>
<text x="182.8" y="110.7">OUT_N</text>
<text x="183.2" y="108.2">OUT_P</text>
<text x="185.1" y="115.8">VCM</text>
<text x="203.1" y="122.1">GND</text>
<text x="88.7" y="137.4">GND</text>
<text x="121.7" y="137.4">GND</text>
</g>
<g font-size="2.3" fill="#000080">
<text x="183.3" y="77.7">C35</text>
<text x="190.9" y="77.7">C36</text>
<text x="198.6" y="77.7">C37</text>
<text x="206.3" y="77.7">C38</text>
<text x="183.5" y="82.7">1nF</text>
<text x="190.5" y="82.7">10nF</text>
<text x="198.8" y="82.7">100nF</text>
<text x="206.3" y="82.7">1uF</text>
<text x="125" y="89.1" transform="rotate(-90 125 89.1)">10K</text>
<text x="127.6" y="86.4" transform="rotate(-90 127.6 86.4)">R53</text>
<text x="134.3" y="91.7">U9</text>
<text x="94.5" y="101.6" transform="rotate(-90 94.5 101.6)">R54</text>
<text x="92" y="104" transform="rotate(-90 92 104)">100</text>
<text x="208" y="106.9">C39</text>
<text x="208" y="109.5">100nF</text>
<text x="94.5" y="119.4" transform="rotate(-90 94.5 119.4)">R55</text>
<text x="98.8" y="117.1">TP24</text>
<text x="92" y="121.8" transform="rotate(-90 92 121.8)">100</text>
<text x="134.3" y="132.3">LMH6518</text>
</g>
</g></defs>
<path d="M2.2 8.3h292.3v193h-292.3z" fill-rule="evenodd" fill="#fffcf8"/>
<path d="M2.2 8.3h292.3v193h-292.3z" fill="none" stroke="#000" stroke-width=".21"/>
<path d="M7.3 13.4h282.1v182.9h-282.1z" fill-rule="evenodd" fill="#fffcf8"/>
<g fill="none" stroke="#000" stroke-width=".21">
<path d="M2.2 8.3h5.1M7.3 13.4h282.1v182.9h-282.1zM75.3 8.3v5.1M148.4 8.3v5.1M221.4 8.3v5.1M289.4 8.3h5.1v5.1M2.2 56.6h5.1M289.4 56.6h5.1M2.2 104.8h5.1M289.4 104.9h5.1M2.2 153.1h5.1M289.4 153.1h5.1"/>
<path d="M289.4 176h-88.9v20.3M75.3 196.3v5M148.4 196.3v5M200.5 183.6h88.9M200.5 191.2h88.9M200.5 193.7h88.9M213.2 183.6v7.6M221.4 196.3v5M251.3 191.2v5.1M264 183.6v7.6M294.5 196.3v5"/>
</g>
<path d="M134.4 92.1h30.5v38.1h-30.5z" fill-rule="evenodd" fill="#ffffb0"/>
<path d="M134.4 92.1h30.5v38.1h-30.5z" fill="none" stroke="#800000" stroke-width=".21"/>
<path d="M126.8 94.7h7.6M126.8 97.2h7.6M126.8 99.8h7.6M164.9 99.8h7.6M164.9 115h7.6" fill="none" stroke="#000" stroke-width=".25"/>
<path d="M164.9 115l1.5-.5v1z" fill="#f8fcff"/>
<path d="M164.9 115l1.5-.5v1z" fill="none" stroke="#000" stroke-width=".21"/>
<path d="M164.9 109.9h7.6M164.9 107.4h7.6M164.9 120.1h7.6M164.9 122.6h7.6M164.9 127.7h7.6" fill="none" stroke="#000" stroke-width=".25"/>
<path d="M164.9 127.7l1.5-.5v1z" fill="#f8fcff"/>
<path d="M164.9 127.7l1.5-.5v1z" fill="none" stroke="#000" stroke-width=".21"/>
<path d="M164.9 94.7h7.6M164.9 97.2h7.6M126.8 107.4h7.6M126.8 109.9h7.6M126.8 127.7h7.6M126.8 125.2h7.6M126.8 122.6h7.6" fill="none" stroke="#000" stroke-width=".25"/>
<path d="M106.4 93.4h14l1.3 1.3-1.3 1.3h-14z" fill-rule="evenodd" fill="#ffff80"/>
<path d="M106.4 93.4h14l1.3 1.3-1.3 1.3h-14z" fill="none" stroke="#800000" stroke-width=".21"/>
<path d="M124.2 82v2M124.2 90.2v1.9" fill="none" stroke="#000" stroke-width=".25"/>
<path d="M123.2 84.1h2.1v6h-2.1z" fill="none" stroke="#00f" stroke-width=".25"/>
<path d="M122.9 76.9h2.6M124.2 76.9v2.6" fill="none" stroke="#800000" stroke-width=".25"/>
<path d="M106.4 98.5h14l1.3 1.3-1.3 1.2h-14z" fill-rule="evenodd" fill="#ffff80"/>
<path d="M106.4 98.5h14l1.3 1.3-1.3 1.2h-14z" fill="none" stroke="#800000" stroke-width=".21"/>
<path d="M106.4 96h14l1.3 1.2-1.3 1.3h-14z" fill-rule="evenodd" fill="#ffff80"/>
<path d="M106.4 96h14l1.3 1.2-1.3 1.3h-14z" fill="none" stroke="#800000" stroke-width=".21"/>
<path d="M106.4 106.1h14l1.3 1.3-1.3 1.3h-14z" fill-rule="evenodd" fill="#ffff80"/>
<path d="M106.4 106.1h14l1.3 1.3-1.3 1.3h-14z" fill="none" stroke="#800000" stroke-width=".21"/>
<path d="M121.7 132.8h5.1M122.4 133.5h3.6M123.2 134.3h2M124 135.1h.5M124.2 130.2v2.6" fill="none" stroke="#800000" stroke-width=".25"/>
<path d="M180.1 115l1.3-1.3h11.4v2.6h-11.4z" fill-rule="evenodd" fill="#ffff80"/>
<path d="M180.1 115l1.3-1.3h11.4v2.6h-11.4z" fill="none" stroke="#800000" stroke-width=".21"/>
<path d="M180.1 106.1h11.5l1.2 1.3-1.2 1.3h-11.5z" fill-rule="evenodd" fill="#ffff80"/>
<path d="M180.1 106.1h11.5l1.2 1.3-1.2 1.3h-11.5z" fill="none" stroke="#800000" stroke-width=".21"/>
<path d="M180.1 108.7h11.5l1.2 1.2-1.2 1.3h-11.5z" fill-rule="evenodd" fill="#ffff80"/>
<path d="M180.1 108.7h11.5l1.2 1.2-1.2 1.3h-11.5z" fill="none" stroke="#800000" stroke-width=".21"/>
<g fill="none" stroke="#000" stroke-width=".25">
<path d="M182.7 74.4v2.5M190.3 74.4v2.5M197.9 74.4v2.5M205.6 74.4v2.5M91.2 97.2v2M182.7 82v2.5M190.3 82v2.5M197.9 82v2.5M205.6 82v2.5M91.2 105.4v2M91.2 115v2M205.6 102.3v2.6"/>
<path d="M205.6 109.9v2.6M91.2 123.2v2"/>
</g>
<g fill="none" stroke="#00f" stroke-width=".25">
<path d="M180.7 79.9h4M180.7 79h4M182.7 76.9v2.1M182.7 79.9v2.1M188.3 79.9h4M188.3 79h4M190.3 76.9v2.1M190.3 79.9v2.1M195.9 79.9h4M195.9 79h4M197.9 76.9v2.1M197.9 79.9v2.1"/>
<path d="M203.6 79.9h4M203.6 79h4M205.6 76.9v2.1M205.6 79.9v2.1M90.2 99.3h2v6h-2zM90.2 117.1h2v6h-2zM203.6 107.9h4M203.6 106.9h4M205.6 104.9v2M205.6 107.9v2"/>
</g>
<g fill="none" stroke="#800000" stroke-width=".25">
<path d="M211.9 66.8h2.5M213.2 66.8v2.5M89.9 92.1h2.6M91.2 92.1v2.6M180.1 89.6h5.1M180.9 90.4h3.6M181.7 91.1h2M182.4 91.9h.5M182.7 87.1v2.5M187.8 89.6h5M188.5 90.4h3.6M189.3 91.1h2"/>
<path d="M190.1 91.9h.5M190.3 87.1v2.5M195.4 89.6h5.1M196.2 90.4h3.5M196.9 91.1h2M197.7 91.9h.5M197.9 87.1v2.5M203 89.6h5.1M203.8 90.4h3.5M204.5 91.1h2.1M205.3 91.9h.5M205.6 87.1v2.5"/>
<path d="M211.9 94.7h2.5M213.2 94.7v2.5M203 117.5h5.1M203.8 118.3h3.5M204.5 119.1h2.1M205.3 119.8h.5M205.6 115v2.5M88.6 132.8h5.1M89.4 133.5h3.6M90.2 134.3h2M90.9 135.1h.5M91.2 130.2v2.6"/>
</g>
<path d="M171.5 119.1l2 2M173.5 119.1l-2 2M171.5 121.6l2 2M171.5 126.7l2 2M173.5 121.6l-2 2M173.5 126.7l-2 2" fill="none" stroke="#f00" stroke-width=".21"/>
<path d="M68.3 111.2h11.4l1.3 1.3-1.3 1.2h-11.4z" fill-rule="evenodd" fill="#ffff80"/>
<path d="M68.3 111.2h11.4l1.3 1.3-1.3 1.2h-11.4z" fill="none" stroke="#800000" stroke-width=".21"/>
<path d="M205.6 71.8v2.6" fill="none" stroke="#000080" stroke-width=".25"/>
<circle cx="205.6" cy="71.8" r=".51" fill="#000080"/>
<circle cx="205.6" cy="71.8" r=".51" fill="none" stroke="#000080" stroke-width=".21"/>
<path d="M81 112.5h10.2" fill="none" stroke="#000080" stroke-width=".25"/>
<circle cx="91.2" cy="112.5" r=".51" fill="#000080"/>
<circle cx="91.2" cy="112.5" r=".51" fill="none" stroke="#000080" stroke-width=".21"/>
<path d="M91.2 109.9h35.6" fill="none" stroke="#000080" stroke-width=".25"/>
<circle cx="98.8" cy="109.9" r=".51" fill="#000080"/>
<circle cx="98.8" cy="109.9" r=".51" fill="none" stroke="#000080" stroke-width=".21"/>
<circle cx="91.2" cy="109.9" r=".51" fill="#000080"/>
<circle cx="91.2" cy="109.9" r=".51" fill="none" stroke="#000080" stroke-width=".21"/>
<path d="M121.7 94.7h5.1M121.7 99.8h5.1M121.7 97.2h5.1M121.7 107.4h5.1" fill="none" stroke="#000080" stroke-width=".25"/>
<circle cx="124.2" cy="94.7" r=".51" fill="#000080"/>
<circle cx="124.2" cy="94.7" r=".51" fill="none" stroke="#000080" stroke-width=".21"/>
<path d="M126.8 122.6h-2.6v5.1h2.6" fill="none" stroke="#000080" stroke-width=".25"/>
<circle cx="124.2" cy="125.2" r=".51" fill="#000080"/>
<circle cx="124.2" cy="125.2" r=".51" fill="none" stroke="#000080" stroke-width=".21"/>
<circle cx="124.2" cy="127.7" r=".51" fill="#000080"/>
<circle cx="124.2" cy="127.7" r=".51" fill="none" stroke="#000080" stroke-width=".21"/>
<path d="M124.2 125.2h2.6" fill="none" stroke="#000080" stroke-width=".25"/>
<circle cx="124.2" cy="125.2" r=".51" fill="#000080"/>
<circle cx="124.2" cy="125.2" r=".51" fill="none" stroke="#000080" stroke-width=".21"/>
<path d="M213.2 97.2v2.6h-40.7M172.5 115h7.6M172.5 109.9h7.6M172.5 107.4h7.6" fill="none" stroke="#000080" stroke-width=".25"/>
<circle cx="205.6" cy="99.8" r=".51" fill="#000080"/>
<circle cx="205.6" cy="99.8" r=".51" fill="none" stroke="#000080" stroke-width=".21"/>
<path d="M182.7 71.8h-5.1v25.4h-5.1" fill="none" stroke="#000080" stroke-width=".25"/>
<circle cx="182.7" cy="71.8" r=".51" fill="#000080"/>
<circle cx="182.7" cy="71.8" r=".51" fill="none" stroke="#000080" stroke-width=".21"/>
<circle cx="177.6" cy="94.7" r=".51" fill="#000080"/>
<circle cx="177.6" cy="94.7" r=".51" fill="none" stroke="#000080" stroke-width=".21"/>
<path d="M172.5 94.7h5.1" fill="none" stroke="#000080" stroke-width=".25"/>
<circle cx="177.6" cy="94.7" r=".51" fill="#000080"/>
<circle cx="177.6" cy="94.7" r=".51" fill="none" stroke="#000080" stroke-width=".21"/>
<path d="M190.3 71.8h-7.6v2.6" fill="none" stroke="#000080" stroke-width=".25"/>
<circle cx="182.7" cy="71.8" r=".51" fill="#000080"/>
<circle cx="182.7" cy="71.8" r=".51" fill="none" stroke="#000080" stroke-width=".21"/>
<circle cx="190.3" cy="71.8" r=".51" fill="#000080"/>
<circle cx="190.3" cy="71.8" r=".51" fill="none" stroke="#000080" stroke-width=".21"/>
<path d="M197.9 71.8h-7.6v2.6" fill="none" stroke="#000080" stroke-width=".25"/>
<circle cx="190.3" cy="71.8" r=".51" fill="#000080"/>
<circle cx="190.3" cy="71.8" r=".51" fill="none" stroke="#000080" stroke-width=".21"/>
<circle cx="197.9" cy="71.8" r=".51" fill="#000080"/>
<circle cx="197.9" cy="71.8" r=".51" fill="none" stroke="#000080" stroke-width=".21"/>
<path d="M213.2 69.3v2.5h-15.3v2.6" fill="none" stroke="#000080" stroke-width=".25"/>
<circle cx="197.9" cy="71.8" r=".51" fill="#000080"/>
<circle cx="197.9" cy="71.8" r=".51" fill="none" stroke="#000080" stroke-width=".21"/>
<circle cx="205.6" cy="71.8" r=".51" fill="#000080"/>
<circle cx="205.6" cy="71.8" r=".51" fill="none" stroke="#000080" stroke-width=".21"/>
<path d="M91.2 107.4v7.6M91.2 125.2v5" fill="none" stroke="#000080" stroke-width=".25"/>
<circle cx="91.2" cy="112.5" r=".51" fill="#000080"/>
<circle cx="91.2" cy="112.5" r=".51" fill="none" stroke="#000080" stroke-width=".21"/>
<circle cx="91.2" cy="109.9" r=".51" fill="#000080"/>
<circle cx="91.2" cy="109.9" r=".51" fill="none" stroke="#000080" stroke-width=".21"/>
<path d="M91.2 94.7v2.5M124.2 127.7v2.5" fill="none" stroke="#000080" stroke-width=".25"/>
<circle cx="124.2" cy="127.7" r=".51" fill="#000080"/>
<circle cx="124.2" cy="127.7" r=".51" fill="none" stroke="#000080" stroke-width=".21"/>
<path d="M124.2 92.1v2.6" fill="none" stroke="#000080" stroke-width=".25"/>
<circle cx="124.2" cy="94.7" r=".51" fill="#000080"/>
<circle cx="124.2" cy="94.7" r=".51" fill="none" stroke="#000080" stroke-width=".21"/>
<path d="M124.2 79.5v2.5M182.7 84.5v2.6M190.3 84.5v2.6M197.9 84.5v2.6M205.6 99.8v2.5M205.6 112.5v2.5" fill="none" stroke="#000080" stroke-width=".25"/>
<circle cx="205.6" cy="99.8" r=".51" fill="#000080"/>
<circle cx="205.6" cy="99.8" r=".51" fill="none" stroke="#000080" stroke-width=".21"/>
<path d="M205.6 84.5v2.6" fill="none" stroke="#000080" stroke-width=".25"/>
<circle cx="98.8" cy="109.9" r=".51" fill="#000080"/>
<circle cx="98.8" cy="109.9" r=".51" fill="none" stroke="#000080" stroke-width=".21"/>
<path d="M98.8 109.9v2.6" fill="none" stroke="#000" stroke-width=".25"/>
<circle cx="98.8" cy="109.9" r=".51" fill="#000080"/>
<circle cx="98.8" cy="109.9" r=".51" fill="none" stroke="#000080" stroke-width=".21"/>
<circle cx="98.8" cy="113.7" r="1.27" fill="none" stroke="#000" stroke-width=".25"/>
<use href="#words"/>
</svg>
